# 
# ******************************************************************************
# *                                                                            *
# *                   Copyright (C) 2004-2010, Nangate Inc.                    *
# *                           All rights reserved.                             *
# *                                                                            *
# * Nangate and the Nangate logo are trademarks of Nangate Inc.                *
# *                                                                            *
# * All trademarks, logos, software marks, and trade names (collectively the   *
# * "Marks") in this program are proprietary to Nangate or other respective    *
# * owners that have granted Nangate the right and license to use such Marks.  *
# * You are not permitted to use the Marks without the prior written consent   *
# * of Nangate or such third party that may own the Marks.                     *
# *                                                                            *
# * This file has been provided pursuant to a License Agreement containing     *
# * restrictions on its use. This file contains valuable trade secrets and     *
# * proprietary information of Nangate Inc., and is protected by U.S. and      *
# * international laws and/or treaties.                                        *
# *                                                                            *
# * The copyright notice(s) in this file does not indicate actual or intended  *
# * publication of this file.                                                  *
# *                                                                            *
# *     NGLibraryCreator, v2010.08-HR32-SP3-2010-08-05 - build 1009061800      *
# *                                                                            *
# ******************************************************************************
# 
# 
# Running on brazil06.nangate.com.br for user Giancarlo Franciscatto (gfr).
# Local time is now Fri, 3 Dec 2010, 19:32:18.
# Main process id is 27821.

VERSION 5.6 ;
BUSBITCHARS "[]" ;
DIVIDERCHAR "/" ;

UNITS
  DATABASE MICRONS 2000 ;
END UNITS

MANUFACTURINGGRID 0.0050 ;

LAYER poly
  TYPE MASTERSLICE ;
END poly

LAYER active
  TYPE MASTERSLICE ;
END active

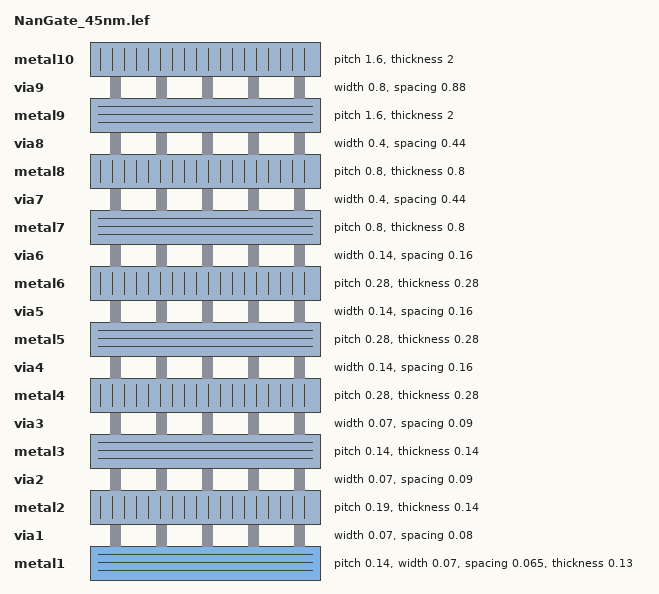
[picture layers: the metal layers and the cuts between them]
LAYER metal1
  TYPE ROUTING ;
  SPACING 0.065 ;
  WIDTH 0.07 ;
  PITCH 0.14 ;
  DIRECTION HORIZONTAL ;
  OFFSET 0.095 0.07 ;
  RESISTANCE RPERSQ 0.38 ;
  THICKNESS 0.13 ;
  HEIGHT 0.37 ;
  CAPACITANCE CPERSQDIST 7.7161e-05 ;
  EDGECAPACITANCE 2.7365e-05 ;
END metal1

LAYER via1
  TYPE CUT ;
  SPACING 0.08 ;
  WIDTH 0.07 ;
  RESISTANCE 5 ;
END via1

LAYER metal2
  TYPE ROUTING ;
  SPACINGTABLE 
    PARALLELRUNLENGTH    0.0000     0.3000     0.9000     1.8000     2.7000     4.0000     
      WIDTH 0.0000       0.0700     0.0700     0.0700     0.0700     0.0700     0.0700     
      WIDTH 0.0900       0.0700     0.0900     0.0900     0.0900     0.0900     0.0900     
      WIDTH 0.2700       0.0700     0.0900     0.2700     0.2700     0.2700     0.2700     
      WIDTH 0.5000       0.0700     0.0900     0.2700     0.5000     0.5000     0.5000     
      WIDTH 0.9000       0.0700     0.0900     0.2700     0.5000     0.9000     0.9000     
      WIDTH 1.5000       0.0700     0.0900     0.2700     0.5000     0.9000     1.5000      ;
  WIDTH 0.07 ;
  PITCH 0.19 ;
  DIRECTION VERTICAL ;
  OFFSET 0.095 0.07 ;
  RESISTANCE RPERSQ 0.25 ;
  THICKNESS 0.14 ;
  HEIGHT 0.62 ;
  CAPACITANCE CPERSQDIST 4.0896e-05 ;
  EDGECAPACITANCE 2.5157e-05 ;
END metal2

LAYER via2
  TYPE CUT ;
  SPACING 0.09 ;
  WIDTH 0.07 ;
  RESISTANCE 5 ;
END via2

LAYER metal3
  TYPE ROUTING ;
  SPACINGTABLE 
    PARALLELRUNLENGTH    0.0000     0.3000     0.9000     1.8000     2.7000     4.0000     
      WIDTH 0.0000       0.0700     0.0700     0.0700     0.0700     0.0700     0.0700     
      WIDTH 0.0900       0.0700     0.0900     0.0900     0.0900     0.0900     0.0900     
      WIDTH 0.2700       0.0700     0.0900     0.2700     0.2700     0.2700     0.2700     
      WIDTH 0.5000       0.0700     0.0900     0.2700     0.5000     0.5000     0.5000     
      WIDTH 0.9000       0.0700     0.0900     0.2700     0.5000     0.9000     0.9000     
      WIDTH 1.5000       0.0700     0.0900     0.2700     0.5000     0.9000     1.5000      ;
  WIDTH 0.07 ;
  PITCH 0.14 ;
  DIRECTION HORIZONTAL ;
  OFFSET 0.095 0.07 ;
  RESISTANCE RPERSQ 0.25 ;
  THICKNESS 0.14 ;
  HEIGHT 0.88 ;
  CAPACITANCE CPERSQDIST 2.7745e-05 ;
  EDGECAPACITANCE 2.5157e-05 ;
END metal3

LAYER via3
  TYPE CUT ;
  SPACING 0.09 ;
  WIDTH 0.07 ;
  RESISTANCE 5 ;
END via3

LAYER metal4
  TYPE ROUTING ;
  SPACINGTABLE 
    PARALLELRUNLENGTH    0.0000     0.9000     1.8000     2.7000     4.0000     
      WIDTH 0.0000       0.1400     0.1400     0.1400     0.1400     0.1400     
      WIDTH 0.2700       0.1400     0.2700     0.2700     0.2700     0.2700     
      WIDTH 0.5000       0.1400     0.2700     0.5000     0.5000     0.5000     
      WIDTH 0.9000       0.1400     0.2700     0.5000     0.9000     0.9000     
      WIDTH 1.5000       0.1400     0.2700     0.5000     0.9000     1.5000      ;
  WIDTH 0.14 ;
  PITCH 0.28 ;
  DIRECTION VERTICAL ;
  OFFSET 0.095 0.07 ;
  RESISTANCE RPERSQ 0.21 ;
  THICKNESS 0.28 ;
  HEIGHT 1.14 ;
  CAPACITANCE CPERSQDIST 2.0743e-05 ;
  EDGECAPACITANCE 3.0908e-05 ;
END metal4

LAYER via4
  TYPE CUT ;
  SPACING 0.16 ;
  WIDTH 0.14 ;
  RESISTANCE 3 ;
END via4

LAYER metal5
  TYPE ROUTING ;
  SPACINGTABLE 
    PARALLELRUNLENGTH    0.0000     0.9000     1.8000     2.7000     4.0000     
      WIDTH 0.0000       0.1400     0.1400     0.1400     0.1400     0.1400     
      WIDTH 0.2700       0.1400     0.2700     0.2700     0.2700     0.2700     
      WIDTH 0.5000       0.1400     0.2700     0.5000     0.5000     0.5000     
      WIDTH 0.9000       0.1400     0.2700     0.5000     0.9000     0.9000     
      WIDTH 1.5000       0.1400     0.2700     0.5000     0.9000     1.5000      ;
  WIDTH 0.14 ;
  PITCH 0.28 ;
  DIRECTION HORIZONTAL ;
  OFFSET 0.095 0.07 ;
  RESISTANCE RPERSQ 0.21 ;
  THICKNESS 0.28 ;
  HEIGHT 1.71 ;
  CAPACITANCE CPERSQDIST 1.3527e-05 ;
  EDGECAPACITANCE 2.3863e-06 ;
END metal5

LAYER via5
  TYPE CUT ;
  SPACING 0.16 ;
  WIDTH 0.14 ;
  RESISTANCE 3 ;
END via5

LAYER metal6
  TYPE ROUTING ;
  SPACINGTABLE 
    PARALLELRUNLENGTH    0.0000     0.9000     1.8000     2.7000     4.0000     
      WIDTH 0.0000       0.1400     0.1400     0.1400     0.1400     0.1400     
      WIDTH 0.2700       0.1400     0.2700     0.2700     0.2700     0.2700     
      WIDTH 0.5000       0.1400     0.2700     0.5000     0.5000     0.5000     
      WIDTH 0.9000       0.1400     0.2700     0.5000     0.9000     0.9000     
      WIDTH 1.5000       0.1400     0.2700     0.5000     0.9000     1.5000      ;
  WIDTH 0.14 ;
  PITCH 0.28 ;
  DIRECTION VERTICAL ;
  OFFSET 0.095 0.07 ;
  RESISTANCE RPERSQ 0.21 ;
  THICKNESS 0.28 ;
  HEIGHT 2.28 ;
  CAPACITANCE CPERSQDIST 1.0036e-05 ;
  EDGECAPACITANCE 2.3863e-05 ;
END metal6

LAYER via6
  TYPE CUT ;
  SPACING 0.16 ;
  WIDTH 0.14 ;
  RESISTANCE 3 ;
END via6

LAYER metal7
  TYPE ROUTING ;
  SPACINGTABLE 
    PARALLELRUNLENGTH    0.0000     1.8000     2.7000     4.0000     
      WIDTH 0.0000       0.4000     0.4000     0.4000     0.4000     
      WIDTH 0.5000       0.4000     0.5000     0.5000     0.5000     
      WIDTH 0.9000       0.4000     0.5000     0.9000     0.9000     
      WIDTH 1.5000       0.4000     0.5000     0.9000     1.5000      ;
  WIDTH 0.4 ;
  PITCH 0.8 ;
  DIRECTION HORIZONTAL ;
  OFFSET 0.095 0.07 ;
  RESISTANCE RPERSQ 0.075 ;
  THICKNESS 0.8 ;
  HEIGHT 2.85 ;
  CAPACITANCE CPERSQDIST 7.9771e-06 ;
  EDGECAPACITANCE 3.2577e-05 ;
END metal7

LAYER via7
  TYPE CUT ;
  SPACING 0.44 ;
  WIDTH 0.4 ;
  RESISTANCE 1 ;
END via7

LAYER metal8
  TYPE ROUTING ;
  SPACINGTABLE 
    PARALLELRUNLENGTH    0.0000     1.8000     2.7000     4.0000     
      WIDTH 0.0000       0.4000     0.4000     0.4000     0.4000     
      WIDTH 0.5000       0.4000     0.5000     0.5000     0.5000     
      WIDTH 0.9000       0.4000     0.5000     0.9000     0.9000     
      WIDTH 1.5000       0.4000     0.5000     0.9000     1.5000      ;
  WIDTH 0.4 ;
  PITCH 0.8 ;
  DIRECTION VERTICAL ;
  OFFSET 0.095 0.07 ;
  RESISTANCE RPERSQ 0.075 ;
  THICKNESS 0.8 ;
  HEIGHT 4.47 ;
  CAPACITANCE CPERSQDIST 5.0391e-06 ;
  EDGECAPACITANCE 2.3932e-05 ;
END metal8

LAYER via8
  TYPE CUT ;
  SPACING 0.44 ;
  WIDTH 0.4 ;
  RESISTANCE 1 ;
END via8

LAYER metal9
  TYPE ROUTING ;
  SPACINGTABLE 
    PARALLELRUNLENGTH    0.0000     2.7000     4.0000     
      WIDTH 0.0000       0.8000     0.8000     0.8000     
      WIDTH 0.9000       0.8000     0.9000     0.9000     
      WIDTH 1.5000       0.8000     0.9000     1.5000      ;
  WIDTH 0.8 ;
  PITCH 1.6 ;
  DIRECTION HORIZONTAL ;
  OFFSET 0.095 0.07 ;
  RESISTANCE RPERSQ 0.03 ;
  THICKNESS 2 ;
  HEIGHT 6.09 ;
  CAPACITANCE CPERSQDIST 3.6827e-06 ;
  EDGECAPACITANCE 3.0803e-05 ;
END metal9

LAYER via9
  TYPE CUT ;
  SPACING 0.88 ;
  WIDTH 0.8 ;
  RESISTANCE 0.5 ;
END via9

LAYER metal10
  TYPE ROUTING ;
  SPACINGTABLE 
    PARALLELRUNLENGTH    0.0000     2.7000     4.0000     
      WIDTH 0.0000       0.8000     0.8000     0.8000     
      WIDTH 0.9000       0.8000     0.9000     0.9000     
      WIDTH 1.5000       0.8000     0.9000     1.5000      ;
  WIDTH 0.8 ;
  PITCH 1.6 ;
  DIRECTION VERTICAL ;
  OFFSET 0.095 0.07 ;
  RESISTANCE RPERSQ 0.03 ;
  THICKNESS 2 ;
  HEIGHT 10.09 ;
  CAPACITANCE CPERSQDIST 2.2124e-06 ;
  EDGECAPACITANCE 2.3667e-05 ;
END metal10

LAYER OVERLAP
  TYPE OVERLAP ;
END OVERLAP

VIA via1_4 DEFAULT
  LAYER via1 ;
    RECT -0.035 -0.035 0.035 0.035 ;
  LAYER metal1 ;
    RECT -0.035 -0.07 0.035 0.07 ;
  LAYER metal2 ;
    RECT -0.035 -0.07 0.035 0.07 ;
END via1_4

VIA via1_0 DEFAULT
  LAYER via1 ;
    RECT -0.035 -0.035 0.035 0.035 ;
  LAYER metal1 ;
    RECT -0.07 -0.07 0.07 0.07 ;
  LAYER metal2 ;
    RECT -0.07 -0.07 0.07 0.07 ;
END via1_0

VIA via1_1 DEFAULT
  LAYER via1 ;
    RECT -0.035 -0.035 0.035 0.035 ;
  LAYER metal1 ;
    RECT -0.07 -0.07 0.07 0.07 ;
  LAYER metal2 ;
    RECT -0.035 -0.07 0.035 0.07 ;
END via1_1

VIA via1_2 DEFAULT
  LAYER via1 ;
    RECT -0.035 -0.035 0.035 0.035 ;
  LAYER metal1 ;
    RECT -0.07 -0.07 0.07 0.07 ;
  LAYER metal2 ;
    RECT -0.07 -0.035 0.07 0.035 ;
END via1_2

VIA via1_3 DEFAULT
  LAYER via1 ;
    RECT -0.035 -0.035 0.035 0.035 ;
  LAYER metal1 ;
    RECT -0.035 -0.07 0.035 0.07 ;
  LAYER metal2 ;
    RECT -0.07 -0.07 0.07 0.07 ;
END via1_3

VIA via1_5 DEFAULT
  LAYER via1 ;
    RECT -0.035 -0.035 0.035 0.035 ;
  LAYER metal1 ;
    RECT -0.035 -0.07 0.035 0.07 ;
  LAYER metal2 ;
    RECT -0.07 -0.035 0.07 0.035 ;
END via1_5

VIA via1_6 DEFAULT
  LAYER via1 ;
    RECT -0.035 -0.035 0.035 0.035 ;
  LAYER metal1 ;
    RECT -0.07 -0.035 0.07 0.035 ;
  LAYER metal2 ;
    RECT -0.07 -0.07 0.07 0.07 ;
END via1_6

VIA via1_7 DEFAULT
  LAYER via1 ;
    RECT -0.035 -0.035 0.035 0.035 ;
  LAYER metal1 ;
    RECT -0.07 -0.035 0.07 0.035 ;
  LAYER metal2 ;
    RECT -0.035 -0.07 0.035 0.07 ;
END via1_7

VIA via1_8 DEFAULT
  LAYER via1 ;
    RECT -0.035 -0.035 0.035 0.035 ;
  LAYER metal1 ;
    RECT -0.07 -0.035 0.07 0.035 ;
  LAYER metal2 ;
    RECT -0.07 -0.035 0.07 0.035 ;
END via1_8

VIA via2_8 DEFAULT
  LAYER via2 ;
    RECT -0.035 -0.035 0.035 0.035 ;
  LAYER metal2 ;
    RECT -0.07 -0.035 0.07 0.035 ;
  LAYER metal3 ;
    RECT -0.07 -0.035 0.07 0.035 ;
END via2_8

VIA via2_4 DEFAULT
  LAYER via2 ;
    RECT -0.035 -0.035 0.035 0.035 ;
  LAYER metal2 ;
    RECT -0.035 -0.07 0.035 0.07 ;
  LAYER metal3 ;
    RECT -0.035 -0.07 0.035 0.07 ;
END via2_4

VIA via2_5 DEFAULT
  LAYER via2 ;
    RECT -0.035 -0.035 0.035 0.035 ;
  LAYER metal2 ;
    RECT -0.035 -0.07 0.035 0.07 ;
  LAYER metal3 ;
    RECT -0.07 -0.035 0.07 0.035 ;
END via2_5

VIA via2_7 DEFAULT
  LAYER via2 ;
    RECT -0.035 -0.035 0.035 0.035 ;
  LAYER metal2 ;
    RECT -0.07 -0.035 0.07 0.035 ;
  LAYER metal3 ;
    RECT -0.035 -0.07 0.035 0.07 ;
END via2_7

VIA via2_6 DEFAULT
  LAYER via2 ;
    RECT -0.035 -0.035 0.035 0.035 ;
  LAYER metal2 ;
    RECT -0.07 -0.035 0.07 0.035 ;
  LAYER metal3 ;
    RECT -0.07 -0.07 0.07 0.07 ;
END via2_6

VIA via2_0 DEFAULT
  LAYER via2 ;
    RECT -0.035 -0.035 0.035 0.035 ;
  LAYER metal2 ;
    RECT -0.07 -0.07 0.07 0.07 ;
  LAYER metal3 ;
    RECT -0.07 -0.07 0.07 0.07 ;
END via2_0

VIA via2_1 DEFAULT
  LAYER via2 ;
    RECT -0.035 -0.035 0.035 0.035 ;
  LAYER metal2 ;
    RECT -0.07 -0.07 0.07 0.07 ;
  LAYER metal3 ;
    RECT -0.035 -0.07 0.035 0.07 ;
END via2_1

VIA via2_2 DEFAULT
  LAYER via2 ;
    RECT -0.035 -0.035 0.035 0.035 ;
  LAYER metal2 ;
    RECT -0.07 -0.07 0.07 0.07 ;
  LAYER metal3 ;
    RECT -0.07 -0.035 0.07 0.035 ;
END via2_2

VIA via2_3 DEFAULT
  LAYER via2 ;
    RECT -0.035 -0.035 0.035 0.035 ;
  LAYER metal2 ;
    RECT -0.035 -0.07 0.035 0.07 ;
  LAYER metal3 ;
    RECT -0.07 -0.07 0.07 0.07 ;
END via2_3

VIA via3_2 DEFAULT
  LAYER via3 ;
    RECT -0.035 -0.035 0.035 0.035 ;
  LAYER metal3 ;
    RECT -0.07 -0.035 0.07 0.035 ;
  LAYER metal4 ;
    RECT -0.07 -0.07 0.07 0.07 ;
END via3_2

VIA via3_0 DEFAULT
  LAYER via3 ;
    RECT -0.035 -0.035 0.035 0.035 ;
  LAYER metal3 ;
    RECT -0.07 -0.07 0.07 0.07 ;
  LAYER metal4 ;
    RECT -0.07 -0.07 0.07 0.07 ;
END via3_0

VIA via3_1 DEFAULT
  LAYER via3 ;
    RECT -0.035 -0.035 0.035 0.035 ;
  LAYER metal3 ;
    RECT -0.035 -0.07 0.035 0.07 ;
  LAYER metal4 ;
    RECT -0.07 -0.07 0.07 0.07 ;
END via3_1

VIA via4_0 DEFAULT
  LAYER via4 ;
    RECT -0.07 -0.07 0.07 0.07 ;
  LAYER metal4 ;
    RECT -0.07 -0.07 0.07 0.07 ;
  LAYER metal5 ;
    RECT -0.07 -0.07 0.07 0.07 ;
END via4_0

VIA via5_0 DEFAULT
  LAYER via5 ;
    RECT -0.07 -0.07 0.07 0.07 ;
  LAYER metal5 ;
    RECT -0.07 -0.07 0.07 0.07 ;
  LAYER metal6 ;
    RECT -0.07 -0.07 0.07 0.07 ;
END via5_0

VIA via6_0 DEFAULT
  LAYER via6 ;
    RECT -0.07 -0.07 0.07 0.07 ;
  LAYER metal6 ;
    RECT -0.07 -0.07 0.07 0.07 ;
  LAYER metal7 ;
    RECT -0.2 -0.2 0.2 0.2 ;
END via6_0

VIA via7_0 DEFAULT
  LAYER via7 ;
    RECT -0.2 -0.2 0.2 0.2 ;
  LAYER metal7 ;
    RECT -0.2 -0.2 0.2 0.2 ;
  LAYER metal8 ;
    RECT -0.2 -0.2 0.2 0.2 ;
END via7_0

VIA via8_0 DEFAULT
  LAYER via8 ;
    RECT -0.2 -0.2 0.2 0.2 ;
  LAYER metal8 ;
    RECT -0.2 -0.2 0.2 0.2 ;
  LAYER metal9 ;
    RECT -0.4 -0.4 0.4 0.4 ;
END via8_0

VIA via9_0 DEFAULT
  LAYER via9 ;
    RECT -0.4 -0.4 0.4 0.4 ;
  LAYER metal9 ;
    RECT -0.4 -0.4 0.4 0.4 ;
  LAYER metal10 ;
    RECT -0.4 -0.4 0.4 0.4 ;
END via9_0

VIARULE Via1Array-0 GENERATE
  LAYER metal1 ;
    ENCLOSURE 0.035 0.035 ;
  LAYER metal2 ;
    ENCLOSURE 0.035 0.035 ;
  LAYER via1 ;
    RECT -0.035 -0.035 0.035 0.035 ;
    SPACING 0.15 BY 0.15 ;
END Via1Array-0

VIARULE Via1Array-1 GENERATE
  LAYER metal1 ;
    ENCLOSURE 0 0.035 ;
  LAYER metal2 ;
    ENCLOSURE 0 0.035 ;
  LAYER via1 ;
    RECT -0.035 -0.035 0.035 0.035 ;
    SPACING 0.15 BY 0.15 ;
END Via1Array-1

VIARULE Via1Array-2 GENERATE
  LAYER metal1 ;
    ENCLOSURE 0.035 0 ;
  LAYER metal2 ;
    ENCLOSURE 0.035 0 ;
  LAYER via1 ;
    RECT -0.035 -0.035 0.035 0.035 ;
    SPACING 0.15 BY 0.15 ;
END Via1Array-2

VIARULE Via1Array-3 GENERATE
  LAYER metal1 ;
    ENCLOSURE 0 0.035 ;
  LAYER metal2 ;
    ENCLOSURE 0.035 0 ;
  LAYER via1 ;
    RECT -0.035 -0.035 0.035 0.035 ;
    SPACING 0.15 BY 0.15 ;
END Via1Array-3

VIARULE Via1Array-4 GENERATE
  LAYER metal1 ;
    ENCLOSURE 0.035 0 ;
  LAYER metal2 ;
    ENCLOSURE 0 0.035 ;
  LAYER via1 ;
    RECT -0.035 -0.035 0.035 0.035 ;
    SPACING 0.15 BY 0.15 ;
END Via1Array-4

VIARULE Via2Array-0 GENERATE
  LAYER metal2 ;
    ENCLOSURE 0.035 0.035 ;
  LAYER metal3 ;
    ENCLOSURE 0.035 0.035 ;
  LAYER via2 ;
    RECT -0.035 -0.035 0.035 0.035 ;
    SPACING 0.16 BY 0.16 ;
END Via2Array-0

VIARULE Via2Array-1 GENERATE
  LAYER metal2 ;
    ENCLOSURE 0 0.035 ;
  LAYER metal3 ;
    ENCLOSURE 0 0.035 ;
  LAYER via2 ;
    RECT -0.035 -0.035 0.035 0.035 ;
    SPACING 0.16 BY 0.16 ;
END Via2Array-1

VIARULE Via2Array-2 GENERATE
  LAYER metal2 ;
    ENCLOSURE 0.035 0 ;
  LAYER metal3 ;
    ENCLOSURE 0.035 0 ;
  LAYER via2 ;
    RECT -0.035 -0.035 0.035 0.035 ;
    SPACING 0.16 BY 0.16 ;
END Via2Array-2

VIARULE Via2Array-3 GENERATE
  LAYER metal2 ;
    ENCLOSURE 0 0.035 ;
  LAYER metal3 ;
    ENCLOSURE 0.035 0 ;
  LAYER via2 ;
    RECT -0.035 -0.035 0.035 0.035 ;
    SPACING 0.16 BY 0.16 ;
END Via2Array-3

VIARULE Via2Array-4 GENERATE
  LAYER metal2 ;
    ENCLOSURE 0.035 0 ;
  LAYER metal3 ;
    ENCLOSURE 0 0.035 ;
  LAYER via2 ;
    RECT -0.035 -0.035 0.035 0.035 ;
    SPACING 0.16 BY 0.16 ;
END Via2Array-4

VIARULE Via3Array-0 GENERATE
  LAYER metal3 ;
    ENCLOSURE 0.035 0.035 ;
  LAYER metal4 ;
    ENCLOSURE 0.035 0.035 ;
  LAYER via3 ;
    RECT -0.035 -0.035 0.035 0.035 ;
    SPACING 0.16 BY 0.16 ;
END Via3Array-0

VIARULE Via3Array-1 GENERATE
  LAYER metal3 ;
    ENCLOSURE 0 0.035 ;
  LAYER metal4 ;
    ENCLOSURE 0.035 0.035 ;
  LAYER via3 ;
    RECT -0.035 -0.035 0.035 0.035 ;
    SPACING 0.16 BY 0.16 ;
END Via3Array-1

VIARULE Via3Array-2 GENERATE
  LAYER metal3 ;
    ENCLOSURE 0.035 0 ;
  LAYER metal4 ;
    ENCLOSURE 0.035 0.035 ;
  LAYER via3 ;
    RECT -0.035 -0.035 0.035 0.035 ;
    SPACING 0.16 BY 0.16 ;
END Via3Array-2

VIARULE Via4Array-0 GENERATE
  LAYER metal4 ;
    ENCLOSURE 0 0 ;
  LAYER metal5 ;
    ENCLOSURE 0 0 ;
  LAYER via4 ;
    RECT -0.07 -0.07 0.07 0.07 ;
    SPACING 0.3 BY 0.3 ;
END Via4Array-0

VIARULE Via5Array-0 GENERATE
  LAYER metal5 ;
    ENCLOSURE 0 0 ;
  LAYER metal6 ;
    ENCLOSURE 0 0 ;
  LAYER via5 ;
    RECT -0.07 -0.07 0.07 0.07 ;
    SPACING 0.3 BY 0.3 ;
END Via5Array-0

VIARULE Via6Array-0 GENERATE
  LAYER metal6 ;
    ENCLOSURE 0 0 ;
  LAYER metal7 ;
    ENCLOSURE 0.13 0.13 ;
  LAYER via6 ;
    RECT -0.07 -0.07 0.07 0.07 ;
    SPACING 0.3 BY 0.3 ;
END Via6Array-0

VIARULE Via7Array-0 GENERATE
  LAYER metal7 ;
    ENCLOSURE 0 0 ;
  LAYER metal8 ;
    ENCLOSURE 0 0 ;
  LAYER via7 ;
    RECT -0.2 -0.2 0.2 0.2 ;
    SPACING 0.84 BY 0.84 ;
END Via7Array-0

VIARULE Via8Array-0 GENERATE
  LAYER metal8 ;
    ENCLOSURE 0 0 ;
  LAYER metal9 ;
    ENCLOSURE 0.2 0.2 ;
  LAYER via8 ;
    RECT -0.2 -0.2 0.2 0.2 ;
    SPACING 0.84 BY 0.84 ;
END Via8Array-0

VIARULE Via9Array-0 GENERATE
  LAYER metal10 ;
    ENCLOSURE 0 0 ;
  LAYER metal9 ;
    ENCLOSURE 0 0 ;
  LAYER via9 ;
    RECT -0.4 -0.4 0.4 0.4 ;
    SPACING 1.68 BY 1.68 ;
END Via9Array-0

SPACING
  SAMENET metal1 metal1 0.065 ;
  SAMENET metal2 metal2 0.07 ;
  SAMENET metal3 metal3 0.07 ;
  SAMENET metal4 metal4 0.14 ;
  SAMENET metal5 metal5 0.14 ;
  SAMENET metal6 metal6 0.14 ;
  SAMENET metal7 metal7 0.4 ;
  SAMENET metal8 metal8 0.4 ;
  SAMENET metal9 metal9 0.8 ;
  SAMENET metal10 metal10 0.8 ;
  SAMENET via1 via1 0.08 ;
  SAMENET via2 via2 0.09 ;
  SAMENET via3 via3 0.09 ;
  SAMENET via4 via4 0.16 ;
  SAMENET via5 via5 0.16 ;
  SAMENET via6 via6 0.16 ;
  SAMENET via7 via7 0.44 ;
  SAMENET via8 via8 0.44 ;
  SAMENET via9 via9 0.88 ;
  SAMENET via1 via2 0.0 STACK ;
  SAMENET via2 via3 0.0 STACK ;
  SAMENET via3 via4 0.0 STACK ;
  SAMENET via4 via5 0.0 STACK ;
  SAMENET via5 via6 0.0 STACK ;
  SAMENET via6 via7 0.0 STACK ;
  SAMENET via7 via8 0.0 STACK ;
  SAMENET via8 via9 0.0 STACK ;
END SPACING

SITE FreePDK45_38x28_10R_NP_162NW_34O
  SYMMETRY y ;
  CLASS core ;
  SIZE 0.19 BY 1.4 ;
END FreePDK45_38x28_10R_NP_162NW_34O


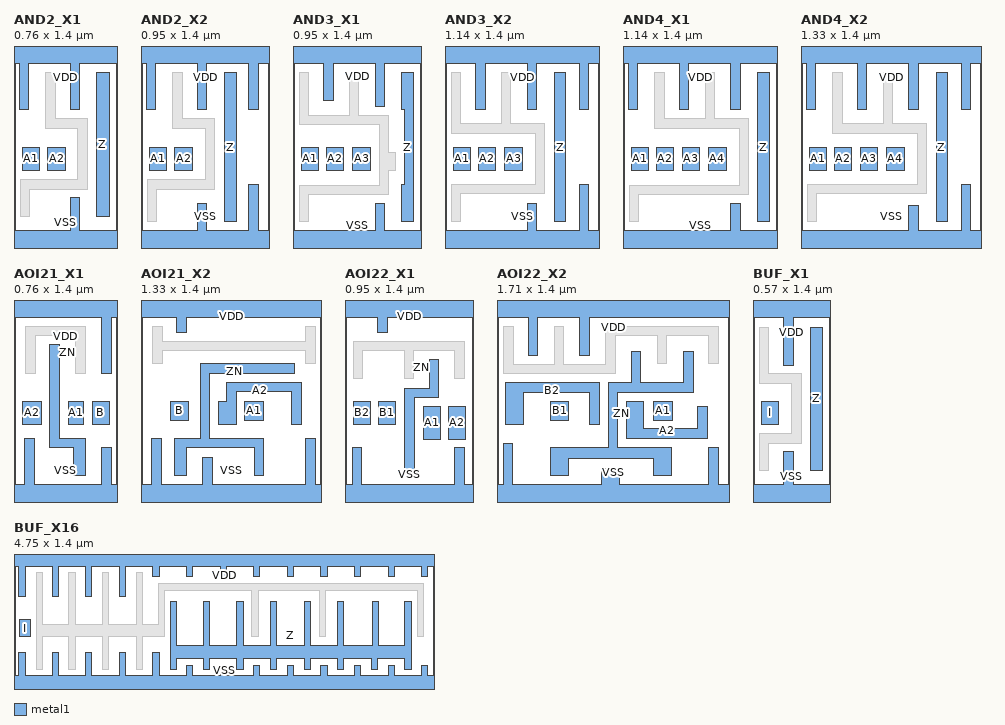
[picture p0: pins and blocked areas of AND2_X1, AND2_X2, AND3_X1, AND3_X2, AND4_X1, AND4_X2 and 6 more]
MACRO AND2_X1
  CLASS core ;
  FOREIGN AND2_X1 0.0 0.0 ;
  ORIGIN 0 0 ;
  SYMMETRY X Y ;
  SITE FreePDK45_38x28_10R_NP_162NW_34O ;
  SIZE 0.76 BY 1.4 ;
  PIN A1
    DIRECTION INPUT ;
    ANTENNAPARTIALMETALAREA 0.021875 LAYER metal1 ;
    ANTENNAPARTIALMETALSIDEAREA 0.078 LAYER metal1 ;
    ANTENNAGATEAREA 0.02625 ;
    PORT
      LAYER metal1 ;
        POLYGON 0.06 0.525 0.185 0.525 0.185 0.7 0.06 0.7  ;
    END
  END A1
  PIN A2
    DIRECTION INPUT ;
    ANTENNAPARTIALMETALAREA 0.02275 LAYER metal1 ;
    ANTENNAPARTIALMETALSIDEAREA 0.0793 LAYER metal1 ;
    ANTENNAGATEAREA 0.02625 ;
    PORT
      LAYER metal1 ;
        POLYGON 0.25 0.525 0.38 0.525 0.38 0.7 0.25 0.7  ;
    END
  END A2
  PIN Z
    DIRECTION OUTPUT ;
    ANTENNAPARTIALMETALAREA 0.0954 LAYER metal1 ;
    ANTENNAPARTIALMETALSIDEAREA 0.299 LAYER metal1 ;
    ANTENNADIFFAREA 0.109725 ;
    PORT
      LAYER metal1 ;
        POLYGON 0.61 0.19 0.7 0.19 0.7 1.25 0.61 1.25  ;
    END
  END Z
  PIN VDD
    DIRECTION INOUT ;
    USE power ;
    SHAPE ABUTMENT ;
    PORT
      LAYER metal1 ;
        POLYGON 0 1.315 0.04 1.315 0.04 0.975 0.11 0.975 0.11 1.315 0.415 1.315 0.415 0.975 0.485 0.975 0.485 1.315 0.54 1.315 0.76 1.315 0.76 1.485 0.54 1.485 0 1.485  ;
    END
  END VDD
  PIN VSS
    DIRECTION INOUT ;
    USE ground ;
    SHAPE ABUTMENT ;
    PORT
      LAYER metal1 ;
        POLYGON 0 -0.085 0.76 -0.085 0.76 0.085 0.485 0.085 0.485 0.325 0.415 0.325 0.415 0.085 0 0.085  ;
    END
  END VSS
  OBS
      LAYER metal1 ;
        POLYGON 0.235 0.84 0.47 0.84 0.47 0.46 0.045 0.46 0.045 0.19 0.115 0.19 0.115 0.39 0.54 0.39 0.54 0.91 0.305 0.91 0.305 1.25 0.235 1.25  ;
  END
END AND2_X1

MACRO AND2_X2
  CLASS core ;
  FOREIGN AND2_X2 0.0 0.0 ;
  ORIGIN 0 0 ;
  SYMMETRY X Y ;
  SITE FreePDK45_38x28_10R_NP_162NW_34O ;
  SIZE 0.95 BY 1.4 ;
  PIN A1
    DIRECTION INPUT ;
    ANTENNAPARTIALMETALAREA 0.021875 LAYER metal1 ;
    ANTENNAPARTIALMETALSIDEAREA 0.078 LAYER metal1 ;
    ANTENNAGATEAREA 0.05225 ;
    PORT
      LAYER metal1 ;
        POLYGON 0.06 0.525 0.185 0.525 0.185 0.7 0.06 0.7  ;
    END
  END A1
  PIN A2
    DIRECTION INPUT ;
    ANTENNAPARTIALMETALAREA 0.02275 LAYER metal1 ;
    ANTENNAPARTIALMETALSIDEAREA 0.0793 LAYER metal1 ;
    ANTENNAGATEAREA 0.05225 ;
    PORT
      LAYER metal1 ;
        POLYGON 0.25 0.525 0.38 0.525 0.38 0.7 0.25 0.7  ;
    END
  END A2
  PIN Z
    DIRECTION OUTPUT ;
    ANTENNAPARTIALMETALAREA 0.0935 LAYER metal1 ;
    ANTENNAPARTIALMETALSIDEAREA 0.3081 LAYER metal1 ;
    ANTENNADIFFAREA 0.1463 ;
    PORT
      LAYER metal1 ;
        POLYGON 0.615 0.15 0.7 0.15 0.7 1.25 0.615 1.25  ;
    END
  END Z
  PIN VDD
    DIRECTION INOUT ;
    USE power ;
    SHAPE ABUTMENT ;
    PORT
      LAYER metal1 ;
        POLYGON 0 1.315 0.04 1.315 0.04 0.975 0.11 0.975 0.11 1.315 0.415 1.315 0.415 0.975 0.485 0.975 0.485 1.315 0.545 1.315 0.795 1.315 0.795 0.975 0.865 0.975 0.865 1.315 0.95 1.315 0.95 1.485 0.545 1.485 0 1.485  ;
    END
  END VDD
  PIN VSS
    DIRECTION INOUT ;
    USE ground ;
    SHAPE ABUTMENT ;
    PORT
      LAYER metal1 ;
        POLYGON 0 -0.085 0.95 -0.085 0.95 0.085 0.865 0.085 0.865 0.425 0.795 0.425 0.795 0.085 0.485 0.085 0.485 0.285 0.415 0.285 0.415 0.085 0 0.085  ;
    END
  END VSS
  OBS
      LAYER metal1 ;
        POLYGON 0.235 0.84 0.475 0.84 0.475 0.46 0.045 0.46 0.045 0.15 0.115 0.15 0.115 0.39 0.545 0.39 0.545 0.91 0.305 0.91 0.305 1.25 0.235 1.25  ;
  END
END AND2_X2

MACRO AND3_X1
  CLASS core ;
  FOREIGN AND3_X1 0.0 0.0 ;
  ORIGIN 0 0 ;
  SYMMETRY X Y ;
  SITE FreePDK45_38x28_10R_NP_162NW_34O ;
  SIZE 0.95 BY 1.4 ;
  PIN A1
    DIRECTION INPUT ;
    ANTENNAPARTIALMETALAREA 0.021875 LAYER metal1 ;
    ANTENNAPARTIALMETALSIDEAREA 0.078 LAYER metal1 ;
    ANTENNAGATEAREA 0.02625 ;
    PORT
      LAYER metal1 ;
        POLYGON 0.06 0.525 0.185 0.525 0.185 0.7 0.06 0.7  ;
    END
  END A1
  PIN A2
    DIRECTION INPUT ;
    ANTENNAPARTIALMETALAREA 0.021875 LAYER metal1 ;
    ANTENNAPARTIALMETALSIDEAREA 0.078 LAYER metal1 ;
    ANTENNAGATEAREA 0.02625 ;
    PORT
      LAYER metal1 ;
        POLYGON 0.25 0.525 0.375 0.525 0.375 0.7 0.25 0.7  ;
    END
  END A2
  PIN A3
    DIRECTION INPUT ;
    ANTENNAPARTIALMETALAREA 0.02275 LAYER metal1 ;
    ANTENNAPARTIALMETALSIDEAREA 0.0793 LAYER metal1 ;
    ANTENNAGATEAREA 0.02625 ;
    PORT
      LAYER metal1 ;
        POLYGON 0.44 0.525 0.57 0.525 0.57 0.7 0.44 0.7  ;
    END
  END A3
  PIN Z
    DIRECTION OUTPUT ;
    ANTENNAPARTIALMETALAREA 0.088 LAYER metal1 ;
    ANTENNAPARTIALMETALSIDEAREA 0.3146 LAYER metal1 ;
    ANTENNADIFFAREA 0.109725 ;
    PORT
      LAYER metal1 ;
        POLYGON 0.8 0.975 0.82 0.975 0.82 0.425 0.8 0.425 0.8 0.15 0.89 0.15 0.89 1.25 0.8 1.25  ;
    END
  END Z
  PIN VDD
    DIRECTION INOUT ;
    USE power ;
    SHAPE ABUTMENT ;
    PORT
      LAYER metal1 ;
        POLYGON 0 1.315 0.225 1.315 0.225 1.04 0.295 1.04 0.295 1.315 0.605 1.315 0.605 1 0.675 1 0.675 1.315 0.755 1.315 0.95 1.315 0.95 1.485 0.755 1.485 0 1.485  ;
    END
  END VDD
  PIN VSS
    DIRECTION INOUT ;
    USE ground ;
    SHAPE ABUTMENT ;
    PORT
      LAYER metal1 ;
        POLYGON 0 -0.085 0.95 -0.085 0.95 0.085 0.675 0.085 0.675 0.285 0.605 0.285 0.605 0.085 0 0.085  ;
    END
  END VSS
  OBS
      LAYER metal1 ;
        POLYGON 0.045 0.865 0.635 0.865 0.635 0.42 0.045 0.42 0.045 0.15 0.115 0.15 0.115 0.35 0.705 0.35 0.705 0.525 0.755 0.525 0.755 0.66 0.705 0.66 0.705 0.935 0.485 0.935 0.485 1.25 0.415 1.25 0.415 0.935 0.115 0.935 0.115 1.25 0.045 1.25  ;
  END
END AND3_X1

MACRO AND3_X2
  CLASS core ;
  FOREIGN AND3_X2 0.0 0.0 ;
  ORIGIN 0 0 ;
  SYMMETRY X Y ;
  SITE FreePDK45_38x28_10R_NP_162NW_34O ;
  SIZE 1.14 BY 1.4 ;
  PIN A1
    DIRECTION INPUT ;
    ANTENNAPARTIALMETALAREA 0.021875 LAYER metal1 ;
    ANTENNAPARTIALMETALSIDEAREA 0.078 LAYER metal1 ;
    ANTENNAGATEAREA 0.05225 ;
    PORT
      LAYER metal1 ;
        POLYGON 0.06 0.525 0.185 0.525 0.185 0.7 0.06 0.7  ;
    END
  END A1
  PIN A2
    DIRECTION INPUT ;
    ANTENNAPARTIALMETALAREA 0.021875 LAYER metal1 ;
    ANTENNAPARTIALMETALSIDEAREA 0.078 LAYER metal1 ;
    ANTENNAGATEAREA 0.05225 ;
    PORT
      LAYER metal1 ;
        POLYGON 0.25 0.525 0.375 0.525 0.375 0.7 0.25 0.7  ;
    END
  END A2
  PIN A3
    DIRECTION INPUT ;
    ANTENNAPARTIALMETALAREA 0.02275 LAYER metal1 ;
    ANTENNAPARTIALMETALSIDEAREA 0.0793 LAYER metal1 ;
    ANTENNAGATEAREA 0.05225 ;
    PORT
      LAYER metal1 ;
        POLYGON 0.44 0.525 0.57 0.525 0.57 0.7 0.44 0.7  ;
    END
  END A3
  PIN Z
    DIRECTION OUTPUT ;
    ANTENNAPARTIALMETALAREA 0.0935 LAYER metal1 ;
    ANTENNAPARTIALMETALSIDEAREA 0.3081 LAYER metal1 ;
    ANTENNADIFFAREA 0.1463 ;
    PORT
      LAYER metal1 ;
        POLYGON 0.805 0.15 0.89 0.15 0.89 1.25 0.805 1.25  ;
    END
  END Z
  PIN VDD
    DIRECTION INOUT ;
    USE power ;
    SHAPE ABUTMENT ;
    PORT
      LAYER metal1 ;
        POLYGON 0 1.315 0.225 1.315 0.225 0.975 0.295 0.975 0.295 1.315 0.605 1.315 0.605 0.975 0.675 0.975 0.675 1.315 0.735 1.315 0.99 1.315 0.99 0.975 1.06 0.975 1.06 1.315 1.14 1.315 1.14 1.485 0.735 1.485 0 1.485  ;
    END
  END VDD
  PIN VSS
    DIRECTION INOUT ;
    USE ground ;
    SHAPE ABUTMENT ;
    PORT
      LAYER metal1 ;
        POLYGON 0 -0.085 1.14 -0.085 1.14 0.085 1.06 0.085 1.06 0.425 0.99 0.425 0.99 0.085 0.675 0.085 0.675 0.285 0.605 0.285 0.605 0.085 0 0.085  ;
    END
  END VSS
  OBS
      LAYER metal1 ;
        POLYGON 0.045 0.8 0.665 0.8 0.665 0.425 0.045 0.425 0.045 0.15 0.115 0.15 0.115 0.355 0.735 0.355 0.735 0.87 0.485 0.87 0.485 1.25 0.415 1.25 0.415 0.87 0.115 0.87 0.115 1.25 0.045 1.25  ;
  END
END AND3_X2

MACRO AND4_X1
  CLASS core ;
  FOREIGN AND4_X1 0.0 0.0 ;
  ORIGIN 0 0 ;
  SYMMETRY X Y ;
  SITE FreePDK45_38x28_10R_NP_162NW_34O ;
  SIZE 1.14 BY 1.4 ;
  PIN A1
    DIRECTION INPUT ;
    ANTENNAPARTIALMETALAREA 0.021875 LAYER metal1 ;
    ANTENNAPARTIALMETALSIDEAREA 0.078 LAYER metal1 ;
    ANTENNAGATEAREA 0.02625 ;
    PORT
      LAYER metal1 ;
        POLYGON 0.06 0.525 0.185 0.525 0.185 0.7 0.06 0.7  ;
    END
  END A1
  PIN A2
    DIRECTION INPUT ;
    ANTENNAPARTIALMETALAREA 0.021875 LAYER metal1 ;
    ANTENNAPARTIALMETALSIDEAREA 0.078 LAYER metal1 ;
    ANTENNAGATEAREA 0.02625 ;
    PORT
      LAYER metal1 ;
        POLYGON 0.25 0.525 0.375 0.525 0.375 0.7 0.25 0.7  ;
    END
  END A2
  PIN A3
    DIRECTION INPUT ;
    ANTENNAPARTIALMETALAREA 0.021875 LAYER metal1 ;
    ANTENNAPARTIALMETALSIDEAREA 0.078 LAYER metal1 ;
    ANTENNAGATEAREA 0.02625 ;
    PORT
      LAYER metal1 ;
        POLYGON 0.44 0.525 0.565 0.525 0.565 0.7 0.44 0.7  ;
    END
  END A3
  PIN A4
    DIRECTION INPUT ;
    ANTENNAPARTIALMETALAREA 0.02275 LAYER metal1 ;
    ANTENNAPARTIALMETALSIDEAREA 0.0793 LAYER metal1 ;
    ANTENNAGATEAREA 0.02625 ;
    PORT
      LAYER metal1 ;
        POLYGON 0.63 0.525 0.76 0.525 0.76 0.7 0.63 0.7  ;
    END
  END A4
  PIN Z
    DIRECTION OUTPUT ;
    ANTENNAPARTIALMETALAREA 0.099 LAYER metal1 ;
    ANTENNAPARTIALMETALSIDEAREA 0.3094 LAYER metal1 ;
    ANTENNADIFFAREA 0.109725 ;
    PORT
      LAYER metal1 ;
        POLYGON 0.99 0.15 1.08 0.15 1.08 1.25 0.99 1.25  ;
    END
  END Z
  PIN VDD
    DIRECTION INOUT ;
    USE power ;
    SHAPE ABUTMENT ;
    PORT
      LAYER metal1 ;
        POLYGON 0 1.315 0.04 1.315 0.04 0.975 0.11 0.975 0.11 1.315 0.415 1.315 0.415 0.975 0.485 0.975 0.485 1.315 0.795 1.315 0.795 0.975 0.865 0.975 0.865 1.315 0.925 1.315 1.14 1.315 1.14 1.485 0.925 1.485 0 1.485  ;
    END
  END VDD
  PIN VSS
    DIRECTION INOUT ;
    USE ground ;
    SHAPE ABUTMENT ;
    PORT
      LAYER metal1 ;
        POLYGON 0 -0.085 1.14 -0.085 1.14 0.085 0.865 0.085 0.865 0.285 0.795 0.285 0.795 0.085 0 0.085  ;
    END
  END VSS
  OBS
      LAYER metal1 ;
        POLYGON 0.235 0.84 0.855 0.84 0.855 0.42 0.045 0.42 0.045 0.15 0.115 0.15 0.115 0.35 0.925 0.35 0.925 0.91 0.675 0.91 0.675 1.25 0.605 1.25 0.605 0.91 0.305 0.91 0.305 1.25 0.235 1.25  ;
  END
END AND4_X1

MACRO AND4_X2
  CLASS core ;
  FOREIGN AND4_X2 0.0 0.0 ;
  ORIGIN 0 0 ;
  SYMMETRY X Y ;
  SITE FreePDK45_38x28_10R_NP_162NW_34O ;
  SIZE 1.33 BY 1.4 ;
  PIN A1
    DIRECTION INPUT ;
    ANTENNAPARTIALMETALAREA 0.021875 LAYER metal1 ;
    ANTENNAPARTIALMETALSIDEAREA 0.078 LAYER metal1 ;
    ANTENNAGATEAREA 0.05225 ;
    PORT
      LAYER metal1 ;
        POLYGON 0.06 0.525 0.185 0.525 0.185 0.7 0.06 0.7  ;
    END
  END A1
  PIN A2
    DIRECTION INPUT ;
    ANTENNAPARTIALMETALAREA 0.021875 LAYER metal1 ;
    ANTENNAPARTIALMETALSIDEAREA 0.078 LAYER metal1 ;
    ANTENNAGATEAREA 0.05225 ;
    PORT
      LAYER metal1 ;
        POLYGON 0.25 0.525 0.375 0.525 0.375 0.7 0.25 0.7  ;
    END
  END A2
  PIN A3
    DIRECTION INPUT ;
    ANTENNAPARTIALMETALAREA 0.021875 LAYER metal1 ;
    ANTENNAPARTIALMETALSIDEAREA 0.078 LAYER metal1 ;
    ANTENNAGATEAREA 0.05225 ;
    PORT
      LAYER metal1 ;
        POLYGON 0.44 0.525 0.565 0.525 0.565 0.7 0.44 0.7  ;
    END
  END A3
  PIN A4
    DIRECTION INPUT ;
    ANTENNAPARTIALMETALAREA 0.02275 LAYER metal1 ;
    ANTENNAPARTIALMETALSIDEAREA 0.0793 LAYER metal1 ;
    ANTENNAGATEAREA 0.05225 ;
    PORT
      LAYER metal1 ;
        POLYGON 0.63 0.525 0.76 0.525 0.76 0.7 0.63 0.7  ;
    END
  END A4
  PIN Z
    DIRECTION OUTPUT ;
    ANTENNAPARTIALMETALAREA 0.0935 LAYER metal1 ;
    ANTENNAPARTIALMETALSIDEAREA 0.3081 LAYER metal1 ;
    ANTENNADIFFAREA 0.1463 ;
    PORT
      LAYER metal1 ;
        POLYGON 0.995 0.15 1.08 0.15 1.08 1.25 0.995 1.25  ;
    END
  END Z
  PIN VDD
    DIRECTION INOUT ;
    USE power ;
    SHAPE ABUTMENT ;
    PORT
      LAYER metal1 ;
        POLYGON 0 1.315 0.04 1.315 0.04 0.975 0.11 0.975 0.11 1.315 0.415 1.315 0.415 0.975 0.485 0.975 0.485 1.315 0.795 1.315 0.795 0.975 0.865 0.975 0.865 1.315 0.925 1.315 1.18 1.315 1.18 0.975 1.25 0.975 1.25 1.315 1.33 1.315 1.33 1.485 0.925 1.485 0 1.485  ;
    END
  END VDD
  PIN VSS
    DIRECTION INOUT ;
    USE ground ;
    SHAPE ABUTMENT ;
    PORT
      LAYER metal1 ;
        POLYGON 0 -0.085 1.33 -0.085 1.33 0.085 1.25 0.085 1.25 0.425 1.18 0.425 1.18 0.085 0.865 0.085 0.865 0.27 0.795 0.27 0.795 0.085 0 0.085  ;
    END
  END VSS
  OBS
      LAYER metal1 ;
        POLYGON 0.235 0.8 0.855 0.8 0.855 0.425 0.045 0.425 0.045 0.15 0.115 0.15 0.115 0.355 0.925 0.355 0.925 0.87 0.675 0.87 0.675 1.25 0.605 1.25 0.605 0.87 0.305 0.87 0.305 1.25 0.235 1.25  ;
  END
END AND4_X2

MACRO AOI21_X1
  CLASS core ;
  FOREIGN AOI21_X1 0.0 0.0 ;
  ORIGIN 0 0 ;
  SYMMETRY X Y ;
  SITE FreePDK45_38x28_10R_NP_162NW_34O ;
  SIZE 0.76 BY 1.4 ;
  PIN B
    DIRECTION INPUT ;
    ANTENNAPARTIALMETALAREA 0.021875 LAYER metal1 ;
    ANTENNAPARTIALMETALSIDEAREA 0.078 LAYER metal1 ;
    ANTENNAGATEAREA 0.05225 ;
    PORT
      LAYER metal1 ;
        POLYGON 0.575 0.525 0.7 0.525 0.7 0.7 0.575 0.7  ;
    END
  END B
  PIN A1
    DIRECTION INPUT ;
    ANTENNAPARTIALMETALAREA 0.01925 LAYER metal1 ;
    ANTENNAPARTIALMETALSIDEAREA 0.0741 LAYER metal1 ;
    ANTENNAGATEAREA 0.05225 ;
    PORT
      LAYER metal1 ;
        POLYGON 0.4 0.525 0.51 0.525 0.51 0.7 0.4 0.7  ;
    END
  END A1
  PIN A2
    DIRECTION INPUT ;
    ANTENNAPARTIALMETALAREA 0.0245 LAYER metal1 ;
    ANTENNAPARTIALMETALSIDEAREA 0.0819 LAYER metal1 ;
    ANTENNAGATEAREA 0.05225 ;
    PORT
      LAYER metal1 ;
        POLYGON 0.06 0.525 0.2 0.525 0.2 0.7 0.06 0.7  ;
    END
  END A2
  PIN ZN
    DIRECTION OUTPUT ;
    ANTENNAPARTIALMETALAREA 0.083925 LAYER metal1 ;
    ANTENNAPARTIALMETALSIDEAREA 0.3185 LAYER metal1 ;
    ANTENNADIFFAREA 0.1463 ;
    PORT
      LAYER metal1 ;
        POLYGON 0.265 0.355 0.44 0.355 0.44 0.15 0.525 0.15 0.525 0.425 0.335 0.425 0.335 1.115 0.265 1.115  ;
    END
  END ZN
  PIN VDD
    DIRECTION INOUT ;
    USE power ;
    SHAPE ABUTMENT ;
    PORT
      LAYER metal1 ;
        POLYGON 0 1.315 0.525 1.315 0.645 1.315 0.645 0.905 0.715 0.905 0.715 1.315 0.76 1.315 0.76 1.485 0.525 1.485 0 1.485  ;
    END
  END VDD
  PIN VSS
    DIRECTION INOUT ;
    USE ground ;
    SHAPE ABUTMENT ;
    PORT
      LAYER metal1 ;
        POLYGON 0 -0.085 0.76 -0.085 0.76 0.085 0.715 0.085 0.715 0.355 0.645 0.355 0.645 0.085 0.15 0.085 0.15 0.425 0.08 0.425 0.08 0.085 0 0.085  ;
    END
  END VSS
  OBS
      LAYER metal1 ;
        POLYGON 0.085 0.905 0.155 0.905 0.155 1.18 0.455 1.18 0.455 0.905 0.525 0.905 0.525 1.25 0.085 1.25  ;
  END
END AOI21_X1

MACRO AOI21_X2
  CLASS core ;
  FOREIGN AOI21_X2 0.0 0.0 ;
  ORIGIN 0 0 ;
  SYMMETRY X Y ;
  SITE FreePDK45_38x28_10R_NP_162NW_34O ;
  SIZE 1.33 BY 1.4 ;
  PIN B
    DIRECTION INPUT ;
    ANTENNAPARTIALMETALAREA 0.0189 LAYER metal1 ;
    ANTENNAPARTIALMETALSIDEAREA 0.0715 LAYER metal1 ;
    ANTENNAGATEAREA 0.1045 ;
    PORT
      LAYER metal1 ;
        POLYGON 0.215 0.56 0.35 0.56 0.35 0.7 0.215 0.7  ;
    END
  END B
  PIN A1
    DIRECTION INPUT ;
    ANTENNAPARTIALMETALAREA 0.0189 LAYER metal1 ;
    ANTENNAPARTIALMETALSIDEAREA 0.0715 LAYER metal1 ;
    ANTENNAGATEAREA 0.1045 ;
    PORT
      LAYER metal1 ;
        POLYGON 0.765 0.56 0.9 0.56 0.9 0.7 0.765 0.7  ;
    END
  END A1
  PIN A2
    DIRECTION INPUT ;
    ANTENNAPARTIALMETALAREA 0.0833 LAYER metal1 ;
    ANTENNAPARTIALMETALSIDEAREA 0.3042 LAYER metal1 ;
    ANTENNAGATEAREA 0.1045 ;
    PORT
      LAYER metal1 ;
        POLYGON 0.57 0.525 0.7 0.525 0.7 0.77 1.11 0.77 1.11 0.525 1.18 0.525 1.18 0.84 0.63 0.84 0.63 0.7 0.57 0.7  ;
    END
  END A2
  PIN ZN
    DIRECTION OUTPUT ;
    ANTENNAPARTIALMETALAREA 0.159875 LAYER metal1 ;
    ANTENNAPARTIALMETALSIDEAREA 0.6006 LAYER metal1 ;
    ANTENNADIFFAREA 0.2926 ;
    PORT
      LAYER metal1 ;
        POLYGON 0.505 0.905 1.13 0.905 1.13 0.975 0.435 0.975 0.435 0.425 0.25 0.425 0.25 0.15 0.335 0.15 0.335 0.355 0.835 0.355 0.835 0.15 0.905 0.15 0.905 0.425 0.505 0.425  ;
    END
  END ZN
  PIN VDD
    DIRECTION INOUT ;
    USE power ;
    SHAPE ABUTMENT ;
    PORT
      LAYER metal1 ;
        POLYGON 0 1.315 0.265 1.315 0.265 1.205 0.335 1.205 0.335 1.315 1.285 1.315 1.33 1.315 1.33 1.485 1.285 1.485 0 1.485  ;
    END
  END VDD
  PIN VSS
    DIRECTION INOUT ;
    USE ground ;
    SHAPE ABUTMENT ;
    PORT
      LAYER metal1 ;
        POLYGON 0 -0.085 1.33 -0.085 1.33 0.085 1.285 0.085 1.285 0.425 1.215 0.425 1.215 0.085 0.525 0.085 0.525 0.285 0.455 0.285 0.455 0.085 0.15 0.085 0.15 0.425 0.08 0.425 0.08 0.085 0 0.085  ;
    END
  END VSS
  OBS
      LAYER metal1 ;
        POLYGON 0.085 0.975 0.155 0.975 0.155 1.07 1.215 1.07 1.215 0.975 1.285 0.975 1.285 1.25 1.215 1.25 1.215 1.14 0.155 1.14 0.155 1.25 0.085 1.25  ;
  END
END AOI21_X2

MACRO AOI22_X1
  CLASS core ;
  FOREIGN AOI22_X1 0.0 0.0 ;
  ORIGIN 0 0 ;
  SYMMETRY X Y ;
  SITE FreePDK45_38x28_10R_NP_162NW_34O ;
  SIZE 0.95 BY 1.4 ;
  PIN A1
    DIRECTION INPUT ;
    ANTENNAPARTIALMETALAREA 0.03 LAYER metal1 ;
    ANTENNAPARTIALMETALSIDEAREA 0.0949 LAYER metal1 ;
    ANTENNAGATEAREA 0.05225 ;
    PORT
      LAYER metal1 ;
        POLYGON 0.575 0.42 0.7 0.42 0.7 0.66 0.575 0.66  ;
    END
  END A1
  PIN A2
    DIRECTION INPUT ;
    ANTENNAPARTIALMETALAREA 0.03 LAYER metal1 ;
    ANTENNAPARTIALMETALSIDEAREA 0.0949 LAYER metal1 ;
    ANTENNAGATEAREA 0.05225 ;
    PORT
      LAYER metal1 ;
        POLYGON 0.765 0.42 0.89 0.42 0.89 0.66 0.765 0.66  ;
    END
  END A2
  PIN B1
    DIRECTION INPUT ;
    ANTENNAPARTIALMETALAREA 0.021875 LAYER metal1 ;
    ANTENNAPARTIALMETALSIDEAREA 0.078 LAYER metal1 ;
    ANTENNAGATEAREA 0.05225 ;
    PORT
      LAYER metal1 ;
        POLYGON 0.25 0.525 0.375 0.525 0.375 0.7 0.25 0.7  ;
    END
  END B1
  PIN B2
    DIRECTION INPUT ;
    ANTENNAPARTIALMETALAREA 0.021875 LAYER metal1 ;
    ANTENNAPARTIALMETALSIDEAREA 0.078 LAYER metal1 ;
    ANTENNAGATEAREA 0.05225 ;
    PORT
      LAYER metal1 ;
        POLYGON 0.06 0.525 0.185 0.525 0.185 0.7 0.06 0.7  ;
    END
  END B2
  PIN ZN
    DIRECTION OUTPUT ;
    ANTENNAPARTIALMETALAREA 0.07245 LAYER metal1 ;
    ANTENNAPARTIALMETALSIDEAREA 0.2873 LAYER metal1 ;
    ANTENNADIFFAREA 0.1463 ;
    PORT
      LAYER metal1 ;
        POLYGON 0.44 0.15 0.51 0.15 0.51 0.725 0.69 0.725 0.69 1.005 0.62 1.005 0.62 0.795 0.44 0.795  ;
    END
  END ZN
  PIN VDD
    DIRECTION INOUT ;
    USE power ;
    SHAPE ABUTMENT ;
    PORT
      LAYER metal1 ;
        POLYGON 0 1.315 0.24 1.315 0.24 1.205 0.31 1.205 0.31 1.315 0.88 1.315 0.95 1.315 0.95 1.485 0.88 1.485 0 1.485  ;
    END
  END VDD
  PIN VSS
    DIRECTION INOUT ;
    USE ground ;
    SHAPE ABUTMENT ;
    PORT
      LAYER metal1 ;
        POLYGON 0 -0.085 0.95 -0.085 0.95 0.085 0.88 0.085 0.88 0.355 0.81 0.355 0.81 0.085 0.125 0.085 0.125 0.355 0.055 0.355 0.055 0.085 0 0.085  ;
    END
  END VSS
  OBS
      LAYER metal1 ;
        POLYGON 0.06 0.865 0.13 0.865 0.13 1.07 0.435 1.07 0.435 0.865 0.505 0.865 0.505 1.07 0.81 1.07 0.81 0.865 0.88 0.865 0.88 1.14 0.06 1.14  ;
  END
END AOI22_X1

MACRO AOI22_X2
  CLASS core ;
  FOREIGN AOI22_X2 0.0 0.0 ;
  ORIGIN 0 0 ;
  SYMMETRY X Y ;
  SITE FreePDK45_38x28_10R_NP_162NW_34O ;
  SIZE 1.71 BY 1.4 ;
  PIN A1
    DIRECTION INPUT ;
    ANTENNAPARTIALMETALAREA 0.0189 LAYER metal1 ;
    ANTENNAPARTIALMETALSIDEAREA 0.0715 LAYER metal1 ;
    ANTENNAGATEAREA 0.1045 ;
    PORT
      LAYER metal1 ;
        POLYGON 1.155 0.56 1.29 0.56 1.29 0.7 1.155 0.7  ;
    END
  END A1
  PIN A2
    DIRECTION INPUT ;
    ANTENNAPARTIALMETALAREA 0.078825 LAYER metal1 ;
    ANTENNAPARTIALMETALSIDEAREA 0.2691 LAYER metal1 ;
    ANTENNAGATEAREA 0.1045 ;
    PORT
      LAYER metal1 ;
        POLYGON 0.955 0.425 1.55 0.425 1.55 0.66 1.48 0.66 1.48 0.495 1.08 0.495 1.08 0.7 0.955 0.7  ;
    END
  END A2
  PIN B1
    DIRECTION INPUT ;
    ANTENNAPARTIALMETALAREA 0.0189 LAYER metal1 ;
    ANTENNAPARTIALMETALSIDEAREA 0.0715 LAYER metal1 ;
    ANTENNAGATEAREA 0.1045 ;
    PORT
      LAYER metal1 ;
        POLYGON 0.395 0.56 0.53 0.56 0.53 0.7 0.395 0.7  ;
    END
  END B1
  PIN B2
    DIRECTION INPUT ;
    ANTENNAPARTIALMETALAREA 0.09785 LAYER metal1 ;
    ANTENNAPARTIALMETALSIDEAREA 0.3237 LAYER metal1 ;
    ANTENNAGATEAREA 0.1045 ;
    PORT
      LAYER metal1 ;
        POLYGON 0.06 0.525 0.195 0.525 0.195 0.765 0.685 0.765 0.685 0.525 0.755 0.525 0.755 0.835 0.06 0.835  ;
    END
  END B2
  PIN ZN
    DIRECTION OUTPUT ;
    ANTENNAPARTIALMETALAREA 0.2065 LAYER metal1 ;
    ANTENNAPARTIALMETALSIDEAREA 0.7072 LAYER metal1 ;
    ANTENNADIFFAREA 0.2926 ;
    PORT
      LAYER metal1 ;
        POLYGON 0.89 0.765 1.445 0.765 1.445 1.065 1.375 1.065 1.375 0.835 1.06 0.835 1.06 1.065 0.99 1.065 0.99 0.835 0.82 0.835 0.82 0.355 0.395 0.355 0.395 0.15 0.53 0.15 0.53 0.28 1.15 0.28 1.15 0.15 1.285 0.15 1.285 0.355 0.89 0.355  ;
    END
  END ZN
  PIN VDD
    DIRECTION INOUT ;
    USE power ;
    SHAPE ABUTMENT ;
    PORT
      LAYER metal1 ;
        POLYGON 0 1.315 0.23 1.315 0.23 1.035 0.3 1.035 0.3 1.315 0.61 1.315 0.61 1.035 0.68 1.035 0.68 1.315 1.63 1.315 1.71 1.315 1.71 1.485 1.63 1.485 0 1.485  ;
    END
  END VDD
  PIN VSS
    DIRECTION INOUT ;
    USE ground ;
    SHAPE ABUTMENT ;
    PORT
      LAYER metal1 ;
        POLYGON 0 -0.085 1.71 -0.085 1.71 0.085 1.63 0.085 1.63 0.36 1.56 0.36 1.56 0.085 0.905 0.085 0.905 0.205 0.77 0.205 0.77 0.085 0.115 0.085 0.115 0.39 0.045 0.39 0.045 0.085 0 0.085  ;
    END
  END VSS
  OBS
      LAYER metal1 ;
        POLYGON 0.05 0.9 0.87 0.9 0.87 1.18 1.18 1.18 1.18 0.975 1.25 0.975 1.25 1.18 1.56 1.18 1.56 0.975 1.63 0.975 1.63 1.25 0.8 1.25 0.8 0.97 0.49 0.97 0.49 1.25 0.42 1.25 0.42 0.97 0.12 0.97 0.12 1.25 0.05 1.25  ;
  END
END AOI22_X2

MACRO BUF_X1
  CLASS core ;
  FOREIGN BUF_X1 0.0 0.0 ;
  ORIGIN 0 0 ;
  SYMMETRY X Y ;
  SITE FreePDK45_38x28_10R_NP_162NW_34O ;
  SIZE 0.57 BY 1.4 ;
  PIN I
    DIRECTION INPUT ;
    ANTENNAPARTIALMETALAREA 0.02275 LAYER metal1 ;
    ANTENNAPARTIALMETALSIDEAREA 0.0793 LAYER metal1 ;
    ANTENNAGATEAREA 0.02625 ;
    PORT
      LAYER metal1 ;
        POLYGON 0.06 0.525 0.19 0.525 0.19 0.7 0.06 0.7  ;
    END
  END I
  PIN Z
    DIRECTION OUTPUT ;
    ANTENNAPARTIALMETALAREA 0.0945 LAYER metal1 ;
    ANTENNAPARTIALMETALSIDEAREA 0.2964 LAYER metal1 ;
    ANTENNADIFFAREA 0.109725 ;
    PORT
      LAYER metal1 ;
        POLYGON 0.42 0.19 0.51 0.19 0.51 1.24 0.42 1.24  ;
    END
  END Z
  PIN VDD
    DIRECTION INOUT ;
    USE power ;
    SHAPE ABUTMENT ;
    PORT
      LAYER metal1 ;
        POLYGON 0 1.315 0.225 1.315 0.225 0.965 0.295 0.965 0.295 1.315 0.355 1.315 0.57 1.315 0.57 1.485 0.355 1.485 0 1.485  ;
    END
  END VDD
  PIN VSS
    DIRECTION INOUT ;
    USE ground ;
    SHAPE ABUTMENT ;
    PORT
      LAYER metal1 ;
        POLYGON 0 -0.085 0.57 -0.085 0.57 0.085 0.295 0.085 0.295 0.325 0.225 0.325 0.225 0.085 0 0.085  ;
    END
  END VSS
  OBS
      LAYER metal1 ;
        POLYGON 0.045 0.83 0.285 0.83 0.285 0.46 0.045 0.46 0.045 0.19 0.115 0.19 0.115 0.39 0.355 0.39 0.355 0.9 0.115 0.9 0.115 1.24 0.045 1.24  ;
  END
END BUF_X1

MACRO BUF_X16
  CLASS core ;
  FOREIGN BUF_X16 0.0 0.0 ;
  ORIGIN 0 0 ;
  SYMMETRY X Y ;
  SITE FreePDK45_38x28_10R_NP_162NW_34O ;
  SIZE 4.75 BY 1.4 ;
  PIN I
    DIRECTION INPUT ;
    ANTENNAPARTIALMETALAREA 0.02375 LAYER metal1 ;
    ANTENNAPARTIALMETALSIDEAREA 0.0819 LAYER metal1 ;
    ANTENNAGATEAREA 0.418 ;
    PORT
      LAYER metal1 ;
        POLYGON 0.06 0.525 0.185 0.525 0.185 0.715 0.06 0.715  ;
    END
  END I
  PIN Z
    DIRECTION OUTPUT ;
    ANTENNAPARTIALMETALAREA 0.7364 LAYER metal1 ;
    ANTENNAPARTIALMETALSIDEAREA 2.0644 LAYER metal1 ;
    ANTENNADIFFAREA 1.1704 ;
    PORT
      LAYER metal1 ;
        POLYGON 1.77 0.15 1.84 0.15 1.84 0.28 2.14 0.28 2.14 0.15 2.21 0.15 2.21 0.28 2.52 0.28 2.52 0.15 2.59 0.15 2.59 0.28 2.9 0.28 2.9 0.15 2.97 0.15 2.97 0.28 3.28 0.28 3.28 0.15 3.35 0.15 3.35 0.28 3.66 0.28 3.66 0.15 3.73 0.15 3.73 0.28 4.04 0.28 4.04 0.15 4.11 0.15 4.11 0.28 4.42 0.28 4.42 0.15 4.49 0.15 4.49 0.925 4.42 0.925 4.42 0.42 4.12 0.42 4.12 0.925 4.05 0.925 4.05 0.42 3.73 0.42 3.73 0.925 3.66 0.925 3.66 0.42 3.35 0.42 3.35 0.925 3.28 0.925 3.28 0.42 2.97 0.42 2.97 0.925 2.9 0.925 2.9 0.42 2.59 0.42 2.59 0.925 2.52 0.925 2.52 0.42 2.21 0.42 2.21 0.925 2.14 0.925 2.14 0.42 1.84 0.42 1.84 0.925 1.77 0.925  ;
    END
  END Z
  PIN VDD
    DIRECTION INOUT ;
    USE power ;
    SHAPE ABUTMENT ;
    PORT
      LAYER metal1 ;
        POLYGON 0 1.315 0.055 1.315 0.055 0.975 0.125 0.975 0.125 1.315 0.43 1.315 0.43 0.975 0.5 0.975 0.5 1.315 0.81 1.315 0.81 0.975 0.88 0.975 0.88 1.315 1.19 1.315 1.19 0.975 1.26 0.975 1.26 1.315 1.57 1.315 1.57 1.205 1.64 1.205 1.64 1.315 1.95 1.315 1.95 1.205 2.02 1.205 2.02 1.315 2.33 1.315 2.33 1.205 2.4 1.205 2.4 1.315 2.71 1.315 2.71 1.205 2.78 1.205 2.78 1.315 3.09 1.315 3.09 1.205 3.16 1.205 3.16 1.315 3.47 1.315 3.47 1.205 3.54 1.205 3.54 1.315 3.85 1.315 3.85 1.205 3.92 1.205 3.92 1.315 4.23 1.315 4.23 1.205 4.3 1.205 4.3 1.315 4.61 1.315 4.61 1.205 4.63 1.205 4.68 1.205 4.68 1.315 4.75 1.315 4.75 1.485 4.63 1.485 0 1.485  ;
    END
  END VDD
  PIN VSS
    DIRECTION INOUT ;
    USE ground ;
    SHAPE ABUTMENT ;
    PORT
      LAYER metal1 ;
        POLYGON 0 -0.085 4.75 -0.085 4.75 0.085 4.68 0.085 4.68 0.2 4.61 0.2 4.61 0.085 4.3 0.085 4.3 0.2 4.23 0.2 4.23 0.085 3.92 0.085 3.92 0.2 3.85 0.2 3.85 0.085 3.54 0.085 3.54 0.2 3.47 0.2 3.47 0.085 3.16 0.085 3.16 0.2 3.09 0.2 3.09 0.085 2.78 0.085 2.78 0.2 2.71 0.2 2.71 0.085 2.4 0.085 2.4 0.2 2.33 0.2 2.33 0.085 2.02 0.085 2.02 0.2 1.95 0.2 1.95 0.085 1.64 0.085 1.64 0.34 1.57 0.34 1.57 0.085 1.26 0.085 1.26 0.34 1.19 0.34 1.19 0.085 0.88 0.085 0.88 0.34 0.81 0.34 0.81 0.085 0.5 0.085 0.5 0.34 0.43 0.34 0.43 0.085 0.125 0.085 0.125 0.34 0.055 0.34 0.055 0.085 0 0.085  ;
    END
  END VSS
  OBS
      LAYER metal1 ;
        POLYGON 0.25 0.15 0.32 0.15 0.32 0.525 0.62 0.525 0.62 0.15 0.69 0.15 0.69 0.525 1 0.525 1 0.15 1.07 0.15 1.07 0.525 1.38 0.525 1.38 0.15 1.45 0.15 1.45 0.525 1.705 0.525 1.705 1.05 2.69 1.05 2.69 0.525 2.76 0.525 2.76 1.05 3.45 1.05 3.45 0.525 3.52 0.525 3.52 1.05 4.56 1.05 4.56 0.525 4.63 0.525 4.63 1.12 1.635 1.12 1.635 0.66 1.45 0.66 1.45 1.25 1.38 1.25 1.38 0.66 1.07 0.66 1.07 1.25 1 1.25 1 0.66 0.69 0.66 0.69 1.25 0.62 1.25 0.62 0.66 0.32 0.66 0.32 1.25 0.25 1.25  ;
  END
END BUF_X16

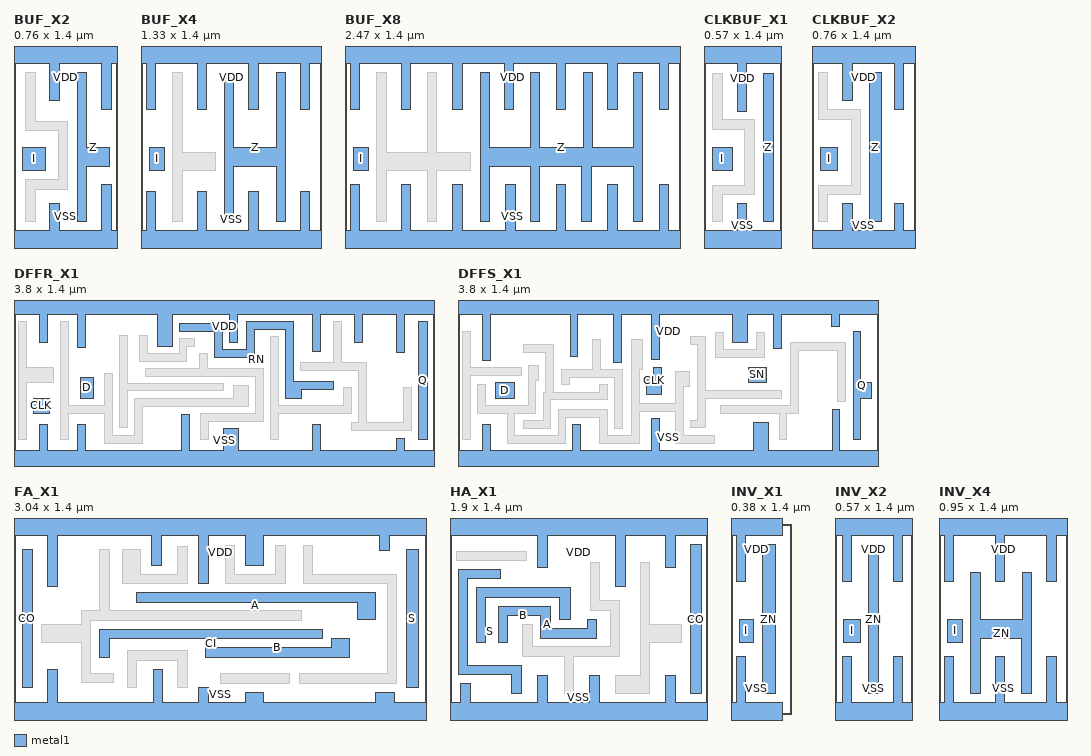
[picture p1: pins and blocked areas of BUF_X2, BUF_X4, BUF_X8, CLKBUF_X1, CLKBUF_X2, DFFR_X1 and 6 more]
MACRO BUF_X2
  CLASS core ;
  FOREIGN BUF_X2 0.0 0.0 ;
  ORIGIN 0 0 ;
  SYMMETRY X Y ;
  SITE FreePDK45_38x28_10R_NP_162NW_34O ;
  SIZE 0.76 BY 1.4 ;
  PIN I
    DIRECTION INPUT ;
    ANTENNAPARTIALMETALAREA 0.02975 LAYER metal1 ;
    ANTENNAPARTIALMETALSIDEAREA 0.0897 LAYER metal1 ;
    ANTENNAGATEAREA 0.05225 ;
    PORT
      LAYER metal1 ;
        POLYGON 0.06 0.525 0.23 0.525 0.23 0.7 0.06 0.7  ;
    END
  END I
  PIN Z
    DIRECTION OUTPUT ;
    ANTENNAPARTIALMETALAREA 0.1001 LAYER metal1 ;
    ANTENNAPARTIALMETALSIDEAREA 0.3471 LAYER metal1 ;
    ANTENNADIFFAREA 0.1463 ;
    PORT
      LAYER metal1 ;
        POLYGON 0.465 0.15 0.535 0.15 0.535 0.56 0.7 0.56 0.7 0.7 0.535 0.7 0.535 1.25 0.465 1.25  ;
    END
  END Z
  PIN VDD
    DIRECTION INOUT ;
    USE power ;
    SHAPE ABUTMENT ;
    PORT
      LAYER metal1 ;
        POLYGON 0 1.315 0.265 1.315 0.265 1.04 0.335 1.04 0.335 1.315 0.395 1.315 0.645 1.315 0.645 0.975 0.715 0.975 0.715 1.315 0.76 1.315 0.76 1.485 0.395 1.485 0 1.485  ;
    END
  END VDD
  PIN VSS
    DIRECTION INOUT ;
    USE ground ;
    SHAPE ABUTMENT ;
    PORT
      LAYER metal1 ;
        POLYGON 0 -0.085 0.76 -0.085 0.76 0.085 0.715 0.085 0.715 0.425 0.645 0.425 0.645 0.085 0.335 0.085 0.335 0.285 0.265 0.285 0.265 0.085 0 0.085  ;
    END
  END VSS
  OBS
      LAYER metal1 ;
        POLYGON 0.085 0.82 0.325 0.82 0.325 0.46 0.085 0.46 0.085 0.15 0.155 0.15 0.155 0.39 0.395 0.39 0.395 0.89 0.155 0.89 0.155 1.25 0.085 1.25  ;
  END
END BUF_X2

MACRO BUF_X4
  CLASS core ;
  FOREIGN BUF_X4 0.0 0.0 ;
  ORIGIN 0 0 ;
  SYMMETRY X Y ;
  SITE FreePDK45_38x28_10R_NP_162NW_34O ;
  SIZE 1.33 BY 1.4 ;
  PIN I
    DIRECTION INPUT ;
    ANTENNAPARTIALMETALAREA 0.01925 LAYER metal1 ;
    ANTENNAPARTIALMETALSIDEAREA 0.0741 LAYER metal1 ;
    ANTENNAGATEAREA 0.1045 ;
    PORT
      LAYER metal1 ;
        POLYGON 0.06 0.525 0.17 0.525 0.17 0.7 0.06 0.7  ;
    END
  END I
  PIN Z
    DIRECTION OUTPUT ;
    ANTENNAPARTIALMETALAREA 0.1974 LAYER metal1 ;
    ANTENNAPARTIALMETALSIDEAREA 0.6526 LAYER metal1 ;
    ANTENNADIFFAREA 0.2926 ;
    PORT
      LAYER metal1 ;
        POLYGON 0.615 0.15 0.685 0.15 0.685 0.56 0.995 0.56 0.995 0.15 1.065 0.15 1.065 1.25 0.995 1.25 0.995 0.7 0.685 0.7 0.685 1.25 0.615 1.25  ;
    END
  END Z
  PIN VDD
    DIRECTION INOUT ;
    USE power ;
    SHAPE ABUTMENT ;
    PORT
      LAYER metal1 ;
        POLYGON 0 1.315 0.04 1.315 0.04 0.975 0.11 0.975 0.11 1.315 0.415 1.315 0.415 0.975 0.485 0.975 0.485 1.315 0.55 1.315 0.795 1.315 0.795 0.975 0.865 0.975 0.865 1.315 1.175 1.315 1.175 0.975 1.245 0.975 1.245 1.315 1.33 1.315 1.33 1.485 0.55 1.485 0 1.485  ;
    END
  END VDD
  PIN VSS
    DIRECTION INOUT ;
    USE ground ;
    SHAPE ABUTMENT ;
    PORT
      LAYER metal1 ;
        POLYGON 0 -0.085 1.33 -0.085 1.33 0.085 1.245 0.085 1.245 0.37 1.175 0.37 1.175 0.085 0.865 0.085 0.865 0.37 0.795 0.37 0.795 0.085 0.485 0.085 0.485 0.37 0.415 0.37 0.415 0.085 0.11 0.085 0.11 0.37 0.04 0.37 0.04 0.085 0 0.085  ;
    END
  END VSS
  OBS
      LAYER metal1 ;
        POLYGON 0.235 0.15 0.305 0.15 0.305 0.525 0.55 0.525 0.55 0.66 0.305 0.66 0.305 1.25 0.235 1.25  ;
  END
END BUF_X4

MACRO BUF_X8
  CLASS core ;
  FOREIGN BUF_X8 0.0 0.0 ;
  ORIGIN 0 0 ;
  SYMMETRY X Y ;
  SITE FreePDK45_38x28_10R_NP_162NW_34O ;
  SIZE 2.47 BY 1.4 ;
  PIN I
    DIRECTION INPUT ;
    ANTENNAPARTIALMETALAREA 0.01925 LAYER metal1 ;
    ANTENNAPARTIALMETALSIDEAREA 0.0741 LAYER metal1 ;
    ANTENNAGATEAREA 0.209 ;
    PORT
      LAYER metal1 ;
        POLYGON 0.06 0.525 0.17 0.525 0.17 0.7 0.06 0.7  ;
    END
  END I
  PIN Z
    DIRECTION OUTPUT ;
    ANTENNAPARTIALMETALAREA 0.4368 LAYER metal1 ;
    ANTENNAPARTIALMETALSIDEAREA 1.3468 LAYER metal1 ;
    ANTENNADIFFAREA 0.5852 ;
    PORT
      LAYER metal1 ;
        POLYGON 0.995 0.15 1.065 0.15 1.065 0.56 1.365 0.56 1.365 0.15 1.435 0.15 1.435 0.56 1.745 0.56 1.745 0.15 1.815 0.15 1.815 0.56 2.125 0.56 2.125 0.15 2.195 0.15 2.195 1.25 2.125 1.25 2.125 0.7 1.825 0.7 1.825 1.25 1.755 1.25 1.755 0.7 1.435 0.7 1.435 1.25 1.365 1.25 1.365 0.7 1.065 0.7 1.065 1.25 0.995 1.25  ;
    END
  END Z
  PIN VDD
    DIRECTION INOUT ;
    USE power ;
    SHAPE ABUTMENT ;
    PORT
      LAYER metal1 ;
        POLYGON 0 1.315 0.04 1.315 0.04 0.975 0.11 0.975 0.11 1.315 0.415 1.315 0.415 0.975 0.485 0.975 0.485 1.315 0.795 1.315 0.795 0.975 0.865 0.975 0.865 1.315 0.925 1.315 1.175 1.315 1.175 0.975 1.245 0.975 1.245 1.315 1.555 1.315 1.555 0.975 1.625 0.975 1.625 1.315 1.935 1.315 1.935 0.975 2.005 0.975 2.005 1.315 2.315 1.315 2.315 0.975 2.385 0.975 2.385 1.315 2.47 1.315 2.47 1.485 0.925 1.485 0 1.485  ;
    END
  END VDD
  PIN VSS
    DIRECTION INOUT ;
    USE ground ;
    SHAPE ABUTMENT ;
    PORT
      LAYER metal1 ;
        POLYGON 0 -0.085 2.47 -0.085 2.47 0.085 2.385 0.085 2.385 0.425 2.315 0.425 2.315 0.085 2.005 0.085 2.005 0.425 1.935 0.425 1.935 0.085 1.625 0.085 1.625 0.425 1.555 0.425 1.555 0.085 1.255 0.085 1.255 0.425 1.185 0.425 1.185 0.085 0.865 0.085 0.865 0.425 0.795 0.425 0.795 0.085 0.485 0.085 0.485 0.425 0.415 0.425 0.415 0.085 0.11 0.085 0.11 0.425 0.04 0.425 0.04 0.085 0 0.085  ;
    END
  END VSS
  OBS
      LAYER metal1 ;
        POLYGON 0.235 0.15 0.305 0.15 0.305 0.525 0.605 0.525 0.605 0.15 0.675 0.15 0.675 0.525 0.925 0.525 0.925 0.66 0.675 0.66 0.675 1.25 0.605 1.25 0.605 0.66 0.305 0.66 0.305 1.25 0.235 1.25  ;
  END
END BUF_X8

MACRO CLKBUF_X1
  CLASS core ;
  FOREIGN CLKBUF_X1 0.0 0.0 ;
  ORIGIN 0 0 ;
  SYMMETRY X Y ;
  SITE FreePDK45_38x28_10R_NP_162NW_34O ;
  SIZE 0.57 BY 1.4 ;
  PIN I
    DIRECTION INPUT ;
    ANTENNAPARTIALMETALAREA 0.02625 LAYER metal1 ;
    ANTENNAPARTIALMETALSIDEAREA 0.0845 LAYER metal1 ;
    ANTENNAGATEAREA 0.0205 ;
    PORT
      LAYER metal1 ;
        POLYGON 0.06 0.525 0.21 0.525 0.21 0.7 0.06 0.7  ;
    END
  END I
  PIN Z
    DIRECTION OUTPUT ;
    ANTENNAPARTIALMETALAREA 0.0763 LAYER metal1 ;
    ANTENNAPARTIALMETALSIDEAREA 0.3016 LAYER metal1 ;
    ANTENNADIFFAREA 0.086625 ;
    PORT
      LAYER metal1 ;
        POLYGON 0.44 0.15 0.51 0.15 0.51 1.24 0.44 1.24  ;
    END
  END Z
  PIN VDD
    DIRECTION INOUT ;
    USE power ;
    SHAPE ABUTMENT ;
    PORT
      LAYER metal1 ;
        POLYGON 0 1.315 0.245 1.315 0.245 0.965 0.315 0.965 0.315 1.315 0.37 1.315 0.57 1.315 0.57 1.485 0.37 1.485 0 1.485  ;
    END
  END VDD
  PIN VSS
    DIRECTION INOUT ;
    USE ground ;
    SHAPE ABUTMENT ;
    PORT
      LAYER metal1 ;
        POLYGON 0 -0.085 0.57 -0.085 0.57 0.085 0.315 0.085 0.315 0.285 0.245 0.285 0.245 0.085 0 0.085  ;
    END
  END VSS
  OBS
      LAYER metal1 ;
        POLYGON 0.065 0.83 0.3 0.83 0.3 0.42 0.065 0.42 0.065 0.15 0.135 0.15 0.135 0.35 0.37 0.35 0.37 0.9 0.135 0.9 0.135 1.24 0.065 1.24  ;
  END
END CLKBUF_X1

MACRO CLKBUF_X2
  CLASS core ;
  FOREIGN CLKBUF_X2 0.0 0.0 ;
  ORIGIN 0 0 ;
  SYMMETRY X Y ;
  SITE FreePDK45_38x28_10R_NP_162NW_34O ;
  SIZE 0.76 BY 1.4 ;
  PIN I
    DIRECTION INPUT ;
    ANTENNAPARTIALMETALAREA 0.02275 LAYER metal1 ;
    ANTENNAPARTIALMETALSIDEAREA 0.0793 LAYER metal1 ;
    ANTENNAGATEAREA 0.04125 ;
    PORT
      LAYER metal1 ;
        POLYGON 0.06 0.525 0.19 0.525 0.19 0.7 0.06 0.7  ;
    END
  END I
  PIN Z
    DIRECTION OUTPUT ;
    ANTENNAPARTIALMETALAREA 0.0935 LAYER metal1 ;
    ANTENNAPARTIALMETALSIDEAREA 0.3081 LAYER metal1 ;
    ANTENNADIFFAREA 0.1155 ;
    PORT
      LAYER metal1 ;
        POLYGON 0.425 0.15 0.51 0.15 0.51 1.25 0.425 1.25  ;
    END
  END Z
  PIN VDD
    DIRECTION INOUT ;
    USE power ;
    SHAPE ABUTMENT ;
    PORT
      LAYER metal1 ;
        POLYGON 0 1.315 0.225 1.315 0.225 1.04 0.295 1.04 0.295 1.315 0.36 1.315 0.605 1.315 0.605 0.975 0.675 0.975 0.675 1.315 0.76 1.315 0.76 1.485 0.36 1.485 0 1.485  ;
    END
  END VDD
  PIN VSS
    DIRECTION INOUT ;
    USE ground ;
    SHAPE ABUTMENT ;
    PORT
      LAYER metal1 ;
        POLYGON 0 -0.085 0.76 -0.085 0.76 0.085 0.675 0.085 0.675 0.285 0.605 0.285 0.605 0.085 0.295 0.085 0.295 0.285 0.225 0.285 0.225 0.085 0 0.085  ;
    END
  END VSS
  OBS
      LAYER metal1 ;
        POLYGON 0.045 0.905 0.29 0.905 0.29 0.42 0.045 0.42 0.045 0.15 0.115 0.15 0.115 0.35 0.36 0.35 0.36 0.975 0.115 0.975 0.115 1.25 0.045 1.25  ;
  END
END CLKBUF_X2

MACRO DFFR_X1
  CLASS core ;
  FOREIGN DFFR_X1 0.0 0.0 ;
  ORIGIN 0 0 ;
  SYMMETRY X Y ;
  SITE FreePDK45_38x28_10R_NP_162NW_34O ;
  SIZE 3.8 BY 1.4 ;
  PIN D
    DIRECTION INPUT ;
    ANTENNAPARTIALMETALAREA 0.0222 LAYER metal1 ;
    ANTENNAPARTIALMETALSIDEAREA 0.0793 LAYER metal1 ;
    ANTENNAGATEAREA 0.03475 ;
    PORT
      LAYER metal1 ;
        POLYGON 0.6 0.56 0.72 0.56 0.72 0.745 0.6 0.745  ;
    END
  END D
  PIN RN
    DIRECTION INPUT ;
    ANTENNAPARTIALMETALAREA 0.181 LAYER metal1 ;
    ANTENNAPARTIALMETALSIDEAREA 0.6682 LAYER metal1 ;
    ANTENNAGATEAREA 0.03525 ;
    PORT
      LAYER metal1 ;
        POLYGON 1.495 1.165 1.63 1.165 1.815 1.165 1.815 0.93 2.175 0.93 2.175 1.18 2.255 1.18 2.455 1.18 2.455 0.56 2.6 0.56 2.6 0.64 2.89 0.64 2.89 0.71 2.525 0.71 2.525 1.25 2.255 1.25 2.105 1.25 2.105 1 1.885 1 1.885 1.235 1.63 1.235 1.495 1.235  ;
    END
  END RN
  PIN CLK
    DIRECTION INPUT ;
    ANTENNAPARTIALMETALAREA 0.0203 LAYER metal1 ;
    ANTENNAPARTIALMETALSIDEAREA 0.0741 LAYER metal1 ;
    ANTENNAGATEAREA 0.02625 ;
    PORT
      LAYER metal1 ;
        POLYGON 0.175 0.42 0.32 0.42 0.32 0.56 0.175 0.56  ;
    END
  END CLK
  PIN Q
    DIRECTION OUTPUT ;
    ANTENNAPARTIALMETALAREA 0.0852 LAYER metal1 ;
    ANTENNAPARTIALMETALSIDEAREA 0.2977 LAYER metal1 ;
    ANTENNADIFFAREA 0.109725 ;
    PORT
      LAYER metal1 ;
        POLYGON 3.66 0.185 3.74 0.185 3.74 1.25 3.66 1.25  ;
    END
  END Q
  PIN VDD
    DIRECTION INOUT ;
    USE power ;
    SHAPE ABUTMENT ;
    PORT
      LAYER metal1 ;
        POLYGON 0 1.315 0.23 1.315 0.23 1.065 0.3 1.065 0.3 1.315 0.355 1.315 0.575 1.315 0.575 1.015 0.645 1.015 0.645 1.315 1.295 1.315 1.295 1.03 1.43 1.03 1.43 1.315 1.63 1.315 1.95 1.315 1.95 1.065 2.02 1.065 2.02 1.315 2.255 1.315 2.7 1.315 2.7 0.98 2.77 0.98 2.77 1.315 3.08 1.315 3.08 1.065 3.15 1.065 3.15 1.315 3.465 1.315 3.465 0.975 3.535 0.975 3.535 1.315 3.595 1.315 3.8 1.315 3.8 1.485 3.595 1.485 2.255 1.485 1.63 1.485 0.355 1.485 0 1.485  ;
    END
  END VDD
  PIN VSS
    DIRECTION INOUT ;
    USE ground ;
    SHAPE ABUTMENT ;
    PORT
      LAYER metal1 ;
        POLYGON 0 -0.085 3.8 -0.085 3.8 0.085 3.535 0.085 3.535 0.195 3.465 0.195 3.465 0.085 2.77 0.085 2.77 0.32 2.7 0.32 2.7 0.085 2.03 0.085 2.03 0.285 1.895 0.285 1.895 0.085 1.585 0.085 1.585 0.41 1.515 0.41 1.515 0.085 0.645 0.085 0.645 0.32 0.575 0.32 0.575 0.085 0.3 0.085 0.3 0.32 0.23 0.32 0.23 0.085 0 0.085  ;
    END
  END VSS
  OBS
      LAYER metal1 ;
        POLYGON 0.04 0.185 0.11 0.185 0.11 0.7 0.355 0.7 0.355 0.835 0.11 0.835 0.11 1.25 0.04 1.25  ;
        POLYGON 1.135 0.895 1.565 0.895 1.565 1.025 1.63 1.025 1.63 1.095 1.495 1.095 1.495 0.965 1.205 0.965 1.205 1.125 1.135 1.125  ;
        POLYGON 0.955 0.29 1.025 0.29 1.025 0.625 1.895 0.625 1.895 0.695 1.025 0.695 1.025 1.125 0.955 1.125  ;
        POLYGON 0.42 0.185 0.49 0.185 0.49 0.425 0.82 0.425 0.82 0.15 1.16 0.15 1.16 0.485 2.12 0.485 2.12 0.67 1.985 0.67 1.985 0.555 1.09 0.555 1.09 0.22 0.89 0.22 0.89 0.785 0.82 0.785 0.82 0.495 0.49 0.495 0.49 1.25 0.42 1.25  ;
        POLYGON 1.19 0.76 2.185 0.76 2.185 0.42 1.69 0.42 1.69 0.185 1.76 0.185 1.76 0.35 2.255 0.35 2.255 0.83 1.75 0.83 1.75 0.96 1.68 0.96 1.68 0.83 1.19 0.83  ;
        POLYGON 2.32 0.185 2.39 0.185 2.39 0.425 3.05 0.425 3.05 0.66 2.98 0.66 2.98 0.495 2.39 0.495 2.39 1.115 2.32 1.115  ;
        POLYGON 2.59 0.81 3.115 0.81 3.115 0.335 3.05 0.335 3.05 0.265 3.595 0.265 3.595 0.66 3.525 0.66 3.525 0.335 3.185 0.335 3.185 0.88 2.96 0.88 2.96 1.25 2.89 1.25 2.89 0.88 2.59 0.88  ;
  END
END DFFR_X1

MACRO DFFS_X1
  CLASS core ;
  FOREIGN DFFS_X1 0.0 0.0 ;
  ORIGIN 0 0 ;
  SYMMETRY X Y ;
  SITE FreePDK45_38x28_10R_NP_162NW_34O ;
  SIZE 3.8 BY 1.4 ;
  PIN D
    DIRECTION INPUT ;
    ANTENNAPARTIALMETALAREA 0.0238 LAYER metal1 ;
    ANTENNAPARTIALMETALSIDEAREA 0.0806 LAYER metal1 ;
    ANTENNAGATEAREA 0.03475 ;
    PORT
      LAYER metal1 ;
        POLYGON 0.34 0.56 0.51 0.56 0.51 0.7 0.34 0.7  ;
    END
  END D
  PIN SN
    DIRECTION INPUT ;
    ANTENNAPARTIALMETALAREA 0.0231 LAYER metal1 ;
    ANTENNAPARTIALMETALSIDEAREA 0.0793 LAYER metal1 ;
    ANTENNAGATEAREA 0.03525 ;
    PORT
      LAYER metal1 ;
        POLYGON 2.625 0.7 2.79 0.7 2.79 0.84 2.625 0.84  ;
    END
  END SN
  PIN CLK
    DIRECTION INPUT ;
    ANTENNAPARTIALMETALAREA 0.026275 LAYER metal1 ;
    ANTENNAPARTIALMETALSIDEAREA 0.1001 LAYER metal1 ;
    ANTENNAGATEAREA 0.02625 ;
    PORT
      LAYER metal1 ;
        POLYGON 1.705 0.59 1.84 0.59 1.84 0.84 1.77 0.84 1.77 0.725 1.705 0.725  ;
    END
  END CLK
  PIN Q
    DIRECTION OUTPUT ;
    ANTENNAPARTIALMETALAREA 0.08155 LAYER metal1 ;
    ANTENNAPARTIALMETALSIDEAREA 0.2964 LAYER metal1 ;
    ANTENNADIFFAREA 0.109725 ;
    PORT
      LAYER metal1 ;
        POLYGON 3.575 0.185 3.645 0.185 3.645 0.56 3.74 0.56 3.74 0.7 3.645 0.7 3.645 1.16 3.575 1.16  ;
    END
  END Q
  PIN VDD
    DIRECTION INOUT ;
    USE power ;
    SHAPE ABUTMENT ;
    PORT
      LAYER metal1 ;
        POLYGON 0 1.315 0.225 1.315 0.225 0.9 0.295 0.9 0.295 1.315 0.57 1.315 1.015 1.315 1.015 0.94 1.085 0.94 1.085 1.315 1.41 1.315 1.41 0.885 1.48 0.885 1.48 1.315 1.485 1.315 1.755 1.315 1.755 0.905 1.825 0.905 1.825 1.315 2.48 1.315 2.48 1.065 2.615 1.065 2.615 1.315 2.77 1.315 2.855 1.315 2.855 1.005 2.925 1.005 2.925 1.315 3.38 1.315 3.38 1.205 3.45 1.205 3.45 1.315 3.505 1.315 3.8 1.315 3.8 1.485 3.505 1.485 2.925 1.485 2.77 1.485 1.485 1.485 0.57 1.485 0 1.485  ;
    END
  END VDD
  PIN VSS
    DIRECTION INOUT ;
    USE ground ;
    SHAPE ABUTMENT ;
    PORT
      LAYER metal1 ;
        POLYGON 0 -0.085 3.8 -0.085 3.8 0.085 3.455 0.085 3.455 0.46 3.385 0.46 3.385 0.085 2.805 0.085 2.805 0.34 2.67 0.34 2.67 0.085 1.82 0.085 1.82 0.375 1.75 0.375 1.75 0.085 1.11 0.085 1.11 0.32 1.04 0.32 1.04 0.085 0.295 0.085 0.295 0.32 0.225 0.32 0.225 0.085 0 0.085  ;
    END
  END VSS
  OBS
      LAYER metal1 ;
        POLYGON 0.04 0.185 0.11 0.185 0.11 0.765 0.57 0.765 0.57 0.835 0.11 0.835 0.11 1.16 0.04 1.16  ;
        POLYGON 0.59 0.975 0.795 0.975 0.795 0.615 0.77 0.615 0.77 0.355 0.59 0.355 0.59 0.285 0.84 0.285 0.84 0.545 1.35 0.545 1.35 0.685 1.28 0.685 1.28 0.615 0.865 0.615 0.865 1.045 0.59 1.045  ;
        POLYGON 0.94 0.685 1.01 0.685 1.01 0.75 1.415 0.75 1.415 0.285 1.485 0.285 1.485 0.82 1.29 0.82 1.29 1.09 1.22 1.09 1.22 0.82 0.94 0.82  ;
        POLYGON 0.175 0.42 0.445 0.42 0.445 0.15 0.975 0.15 0.975 0.385 1.28 0.385 1.28 0.15 1.64 0.15 1.64 0.44 1.97 0.44 1.97 0.15 2.32 0.15 2.32 0.22 2.04 0.22 2.04 0.665 2.095 0.665 2.095 0.8 1.97 0.8 1.97 0.51 1.64 0.51 1.64 0.815 1.67 0.815 1.67 1.09 1.57 1.09 1.57 0.22 1.35 0.22 1.35 0.455 0.905 0.455 0.905 0.22 0.515 0.22 0.515 0.42 0.705 0.42 0.705 0.72 0.73 0.72 0.73 0.855 0.635 0.855 0.635 0.49 0.245 0.49 0.245 0.685 0.175 0.685  ;
        POLYGON 2.33 0.93 2.77 0.93 2.77 1.15 2.7 1.15 2.7 1 2.4 1 2.4 1.15 2.33 1.15  ;
        POLYGON 2.105 1.045 2.17 1.045 2.17 0.36 2.105 0.36 2.105 0.29 2.24 0.29 2.24 0.56 2.925 0.56 2.925 0.63 2.24 0.63 2.24 1.115 2.105 1.115  ;
        POLYGON 2.375 0.42 2.905 0.42 2.905 0.185 2.975 0.185 2.975 0.42 3.08 0.42 3.08 0.995 3.435 0.995 3.435 0.525 3.505 0.525 3.505 1.065 3.01 1.065 3.01 0.49 2.375 0.49  ;
  END
END DFFS_X1

MACRO FA_X1
  CLASS core ;
  FOREIGN FA_X1 0.0 0.0 ;
  ORIGIN 0 0 ;
  SYMMETRY X Y ;
  SITE FreePDK45_38x28_10R_NP_162NW_34O ;
  SIZE 3.04 BY 1.4 ;
  PIN A
    DIRECTION INPUT ;
    ANTENNAPARTIALMETALAREA 0.1391 LAYER metal1 ;
    ANTENNAPARTIALMETALSIDEAREA 0.507 LAYER metal1 ;
    ANTENNAGATEAREA 0.105 ;
    PORT
      LAYER metal1 ;
        POLYGON 0.905 0.825 2.115 0.825 2.53 0.825 2.53 0.7 2.66 0.7 2.66 0.895 2.115 0.895 0.905 0.895  ;
    END
  END A
  PIN B
    DIRECTION INPUT ;
    ANTENNAPARTIALMETALAREA 0.0833 LAYER metal1 ;
    ANTENNAPARTIALMETALSIDEAREA 0.312 LAYER metal1 ;
    ANTENNAGATEAREA 0.105 ;
    PORT
      LAYER metal1 ;
        POLYGON 1.41 0.42 2.03 0.42 2.47 0.42 2.47 0.56 2.34 0.56 2.34 0.49 2.03 0.49 1.41 0.49  ;
    END
  END B
  PIN CI
    DIRECTION INPUT ;
    ANTENNAPARTIALMETALAREA 0.1246 LAYER metal1 ;
    ANTENNAPARTIALMETALSIDEAREA 0.481 LAYER metal1 ;
    ANTENNAGATEAREA 0.07875 ;
    PORT
      LAYER metal1 ;
        POLYGON 0.63 0.42 0.7 0.42 0.7 0.555 1.275 0.555 2.03 0.555 2.275 0.555 2.275 0.625 2.03 0.625 1.275 0.625 0.63 0.625  ;
    END
  END CI
  PIN CO
    DIRECTION OUTPUT ;
    ANTENNAPARTIALMETALAREA 0.0765 LAYER metal1 ;
    ANTENNAPARTIALMETALSIDEAREA 0.2847 LAYER metal1 ;
    ANTENNADIFFAREA 0.109725 ;
    PORT
      LAYER metal1 ;
        POLYGON 0.06 0.195 0.135 0.195 0.135 1.215 0.06 1.215  ;
    END
  END CO
  PIN S
    DIRECTION OUTPUT ;
    ANTENNAPARTIALMETALAREA 0.0918 LAYER metal1 ;
    ANTENNAPARTIALMETALSIDEAREA 0.2886 LAYER metal1 ;
    ANTENNADIFFAREA 0.109725 ;
    PORT
      LAYER metal1 ;
        POLYGON 2.89 0.195 2.98 0.195 2.98 1.215 2.89 1.215  ;
    END
  END S
  PIN VDD
    DIRECTION INOUT ;
    USE power ;
    SHAPE ABUTMENT ;
    PORT
      LAYER metal1 ;
        POLYGON 0 1.315 0.25 1.315 0.25 0.94 0.32 0.94 0.32 1.315 1.015 1.315 1.015 1.095 1.085 1.095 1.085 1.315 1.275 1.315 1.36 1.315 1.36 0.965 1.43 0.965 1.43 1.315 1.705 1.315 1.705 1.095 1.84 1.095 1.84 1.315 2 1.315 2.115 1.315 2.695 1.315 2.695 1.205 2.765 1.205 2.765 1.315 2.82 1.315 3.04 1.315 3.04 1.485 2.82 1.485 2.115 1.485 2 1.485 1.275 1.485 0 1.485  ;
    END
  END VDD
  PIN VSS
    DIRECTION INOUT ;
    USE ground ;
    SHAPE ABUTMENT ;
    PORT
      LAYER metal1 ;
        POLYGON 0 -0.085 3.04 -0.085 3.04 0.085 2.8 0.085 2.8 0.16 2.665 0.16 2.665 0.085 1.84 0.085 1.84 0.16 1.705 0.16 1.705 0.085 1.43 0.085 1.43 0.195 1.36 0.195 1.36 0.085 1.095 0.085 1.095 0.33 1.025 0.33 1.025 0.085 0.32 0.085 0.32 0.33 0.25 0.33 0.25 0.085 0 0.085  ;
    END
  END VSS
  OBS
      LAYER metal1 ;
        POLYGON 0.835 0.195 0.905 0.195 0.905 0.395 1.205 0.395 1.205 0.195 1.275 0.195 1.275 0.465 0.835 0.465  ;
        POLYGON 0.8 0.96 1.275 0.96 1.275 1.235 1.205 1.235 1.205 1.03 0.935 1.03 0.935 1.215 0.8 1.215  ;
        POLYGON 1.555 0.96 2 0.96 2 1.24 1.93 1.24 1.93 1.03 1.625 1.03 1.625 1.24 1.555 1.24  ;
        POLYGON 1.52 0.225 2.03 0.225 2.03 0.295 1.52 0.295  ;
        POLYGON 0.565 0.69 2.115 0.69 2.115 0.76 0.7 0.76 0.7 1.215 0.63 1.215 0.63 0.76 0.495 0.76 0.495 0.66 0.205 0.66 0.205 0.525 0.495 0.525 0.495 0.23 0.735 0.23 0.735 0.3 0.565 0.3  ;
        POLYGON 2.13 0.96 2.75 0.96 2.75 0.295 2.1 0.295 2.1 0.225 2.82 0.225 2.82 1.03 2.2 1.03 2.2 1.24 2.13 1.24  ;
  END
END FA_X1

MACRO HA_X1
  CLASS core ;
  FOREIGN HA_X1 0.0 0.0 ;
  ORIGIN 0 0 ;
  SYMMETRY X Y ;
  SITE FreePDK45_38x28_10R_NP_162NW_34O ;
  SIZE 1.9 BY 1.4 ;
  PIN A
    DIRECTION INPUT ;
    ANTENNAPARTIALMETALAREA 0.0812 LAYER metal1 ;
    ANTENNAPARTIALMETALSIDEAREA 0.3198 LAYER metal1 ;
    ANTENNAGATEAREA 0.10475 ;
    PORT
      LAYER metal1 ;
        POLYGON 0.355 0.525 0.425 0.525 0.425 0.725 0.67 0.725 0.67 0.56 1.08 0.56 1.08 0.7 1.01 0.7 1.01 0.63 0.74 0.63 0.74 0.795 0.355 0.795  ;
    END
  END A
  PIN B
    DIRECTION INPUT ;
    ANTENNAPARTIALMETALAREA 0.0857 LAYER metal1 ;
    ANTENNAPARTIALMETALSIDEAREA 0.3276 LAYER metal1 ;
    ANTENNAGATEAREA 0.10475 ;
    PORT
      LAYER metal1 ;
        POLYGON 0.195 0.525 0.265 0.525 0.265 0.86 0.805 0.86 0.805 0.7 0.89 0.7 0.89 0.93 0.195 0.93  ;
    END
  END B
  PIN CO
    DIRECTION OUTPUT ;
    ANTENNAPARTIALMETALAREA 0.088 LAYER metal1 ;
    ANTENNAPARTIALMETALSIDEAREA 0.3068 LAYER metal1 ;
    ANTENNADIFFAREA 0.109725 ;
    PORT
      LAYER metal1 ;
        POLYGON 1.77 0.15 1.85 0.15 1.85 1.25 1.77 1.25  ;
    END
  END CO
  PIN S
    DIRECTION OUTPUT ;
    ANTENNAPARTIALMETALAREA 0.1085 LAYER metal1 ;
    ANTENNAPARTIALMETALSIDEAREA 0.4212 LAYER metal1 ;
    ANTENNADIFFAREA 0.1463 ;
    PORT
      LAYER metal1 ;
        POLYGON 0.06 0.29 0.455 0.29 0.455 0.15 0.525 0.15 0.525 0.36 0.13 0.36 0.13 0.995 0.37 0.995 0.37 1.065 0.06 1.065  ;
    END
  END S
  PIN VDD
    DIRECTION INOUT ;
    USE power ;
    SHAPE ABUTMENT ;
    PORT
      LAYER metal1 ;
        POLYGON 0 1.315 0.56 1.315 0.645 1.315 0.645 1.08 0.715 1.08 0.715 1.315 1.22 1.315 1.22 0.94 1.25 0.94 1.29 0.94 1.29 1.315 1.59 1.315 1.59 1.08 1.66 1.08 1.66 1.315 1.705 1.315 1.9 1.315 1.9 1.485 1.705 1.485 1.25 1.485 0.56 1.485 0 1.485  ;
    END
  END VDD
  PIN VSS
    DIRECTION INOUT ;
    USE ground ;
    SHAPE ABUTMENT ;
    PORT
      LAYER metal1 ;
        POLYGON 0 -0.085 1.9 -0.085 1.9 0.085 1.66 0.085 1.66 0.285 1.59 0.285 1.59 0.085 1.1 0.085 1.1 0.285 1.03 0.285 1.03 0.085 0.715 0.085 0.715 0.285 0.645 0.285 0.645 0.085 0.15 0.085 0.15 0.225 0.08 0.225 0.08 0.085 0 0.085  ;
    END
  END VSS
  OBS
      LAYER metal1 ;
        POLYGON 0.05 1.13 0.56 1.13 0.56 1.2 0.05 1.2  ;
        POLYGON 1.035 0.765 1.18 0.765 1.18 0.495 0.605 0.495 0.605 0.66 0.535 0.66 0.535 0.425 0.84 0.425 0.84 0.15 0.91 0.15 0.91 0.425 1.25 0.425 1.25 0.835 1.105 0.835 1.105 1.115 1.035 1.115  ;
        POLYGON 1.22 0.15 1.47 0.15 1.47 0.525 1.705 0.525 1.705 0.66 1.47 0.66 1.47 1.115 1.4 1.115 1.4 0.285 1.22 0.285  ;
  END
END HA_X1

MACRO INV_X1
  CLASS core ;
  FOREIGN INV_X1 0.0 0.0 ;
  ORIGIN 0 0 ;
  SYMMETRY X Y ;
  SITE FreePDK45_38x28_10R_NP_162NW_34O ;
  SIZE 0.38 BY 1.4 ;
  PIN I
    DIRECTION INPUT ;
    ANTENNAPARTIALMETALAREA 0.018375 LAYER metal1 ;
    ANTENNAPARTIALMETALSIDEAREA 0.0728 LAYER metal1 ;
    ANTENNAGATEAREA 0.05225 ;
    PORT
      LAYER metal1 ;
        POLYGON 0.06 0.525 0.165 0.525 0.165 0.7 0.06 0.7  ;
    END
  END I
  PIN ZN
    DIRECTION OUTPUT ;
    ANTENNAPARTIALMETALAREA 0.1045 LAYER metal1 ;
    ANTENNAPARTIALMETALSIDEAREA 0.3107 LAYER metal1 ;
    ANTENNADIFFAREA 0.109725 ;
    PORT
      LAYER metal1 ;
        POLYGON 0.23 0.15 0.325 0.15 0.325 1.25 0.23 1.25  ;
    END
  END ZN
  PIN VDD
    DIRECTION INOUT ;
    USE power ;
    SHAPE ABUTMENT ;
    PORT
      LAYER metal1 ;
        POLYGON 0 1.315 0.04 1.315 0.04 0.975 0.11 0.975 0.11 1.315 0.38 1.315 0.38 1.485 0 1.485  ;
    END
  END VDD
  PIN VSS
    DIRECTION INOUT ;
    USE ground ;
    SHAPE ABUTMENT ;
    PORT
      LAYER metal1 ;
        POLYGON 0 -0.085 0.38 -0.085 0.38 0.085 0.11 0.085 0.11 0.425 0.04 0.425 0.04 0.085 0 0.085  ;
    END
  END VSS
END INV_X1

MACRO INV_X2
  CLASS core ;
  FOREIGN INV_X2 0.0 0.0 ;
  ORIGIN 0 0 ;
  SYMMETRY X Y ;
  SITE FreePDK45_38x28_10R_NP_162NW_34O ;
  SIZE 0.57 BY 1.4 ;
  PIN I
    DIRECTION INPUT ;
    ANTENNAPARTIALMETALAREA 0.021875 LAYER metal1 ;
    ANTENNAPARTIALMETALSIDEAREA 0.078 LAYER metal1 ;
    ANTENNAGATEAREA 0.1045 ;
    PORT
      LAYER metal1 ;
        POLYGON 0.06 0.525 0.185 0.525 0.185 0.7 0.06 0.7  ;
    END
  END I
  PIN ZN
    DIRECTION OUTPUT ;
    ANTENNAPARTIALMETALAREA 0.077 LAYER metal1 ;
    ANTENNAPARTIALMETALSIDEAREA 0.3042 LAYER metal1 ;
    ANTENNADIFFAREA 0.1463 ;
    PORT
      LAYER metal1 ;
        POLYGON 0.25 0.15 0.32 0.15 0.32 1.25 0.25 1.25  ;
    END
  END ZN
  PIN VDD
    DIRECTION INOUT ;
    USE power ;
    SHAPE ABUTMENT ;
    PORT
      LAYER metal1 ;
        POLYGON 0 1.315 0.055 1.315 0.055 0.975 0.125 0.975 0.125 1.315 0.43 1.315 0.43 0.975 0.5 0.975 0.5 1.315 0.57 1.315 0.57 1.485 0 1.485  ;
    END
  END VDD
  PIN VSS
    DIRECTION INOUT ;
    USE ground ;
    SHAPE ABUTMENT ;
    PORT
      LAYER metal1 ;
        POLYGON 0 -0.085 0.57 -0.085 0.57 0.085 0.5 0.085 0.5 0.425 0.43 0.425 0.43 0.085 0.125 0.085 0.125 0.425 0.055 0.425 0.055 0.085 0 0.085  ;
    END
  END VSS
END INV_X2

MACRO INV_X4
  CLASS core ;
  FOREIGN INV_X4 0.0 0.0 ;
  ORIGIN 0 0 ;
  SYMMETRY X Y ;
  SITE FreePDK45_38x28_10R_NP_162NW_34O ;
  SIZE 0.95 BY 1.4 ;
  PIN I
    DIRECTION INPUT ;
    ANTENNAPARTIALMETALAREA 0.01925 LAYER metal1 ;
    ANTENNAPARTIALMETALSIDEAREA 0.0741 LAYER metal1 ;
    ANTENNAGATEAREA 0.209 ;
    PORT
      LAYER metal1 ;
        POLYGON 0.06 0.525 0.17 0.525 0.17 0.7 0.06 0.7  ;
    END
  END I
  PIN ZN
    DIRECTION OUTPUT ;
    ANTENNAPARTIALMETALAREA 0.17005 LAYER metal1 ;
    ANTENNAPARTIALMETALSIDEAREA 0.5434 LAYER metal1 ;
    ANTENNADIFFAREA 0.2926 ;
    PORT
      LAYER metal1 ;
        POLYGON 0.235 0.15 0.305 0.15 0.305 0.56 0.61 0.56 0.61 0.15 0.685 0.15 0.685 1.04 0.615 1.04 0.615 0.7 0.305 0.7 0.305 1.04 0.235 1.04  ;
    END
  END ZN
  PIN VDD
    DIRECTION INOUT ;
    USE power ;
    SHAPE ABUTMENT ;
    PORT
      LAYER metal1 ;
        POLYGON 0 1.315 0.04 1.315 0.04 0.98 0.11 0.98 0.11 1.315 0.415 1.315 0.415 0.98 0.485 0.98 0.485 1.315 0.795 1.315 0.795 0.98 0.865 0.98 0.865 1.315 0.95 1.315 0.95 1.485 0 1.485  ;
    END
  END VDD
  PIN VSS
    DIRECTION INOUT ;
    USE ground ;
    SHAPE ABUTMENT ;
    PORT
      LAYER metal1 ;
        POLYGON 0 -0.085 0.95 -0.085 0.95 0.085 0.865 0.085 0.865 0.425 0.795 0.425 0.795 0.085 0.485 0.085 0.485 0.425 0.415 0.425 0.415 0.085 0.11 0.085 0.11 0.425 0.04 0.425 0.04 0.085 0 0.085  ;
    END
  END VSS
END INV_X4

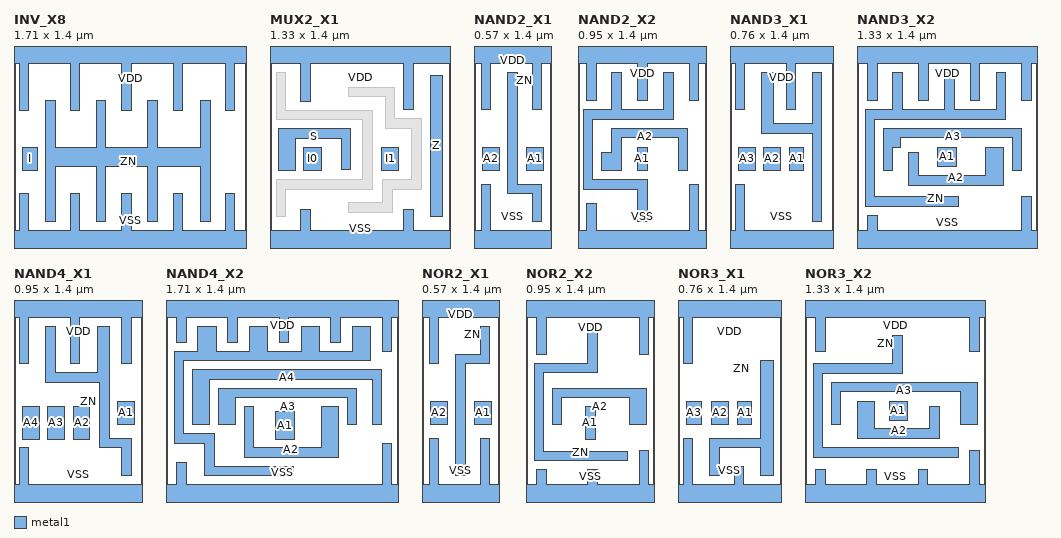
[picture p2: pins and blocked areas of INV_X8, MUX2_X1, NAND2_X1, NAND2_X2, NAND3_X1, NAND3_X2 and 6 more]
MACRO INV_X8
  CLASS core ;
  FOREIGN INV_X8 0.0 0.0 ;
  ORIGIN 0 0 ;
  SYMMETRY X Y ;
  SITE FreePDK45_38x28_10R_NP_162NW_34O ;
  SIZE 1.71 BY 1.4 ;
  PIN I
    DIRECTION INPUT ;
    ANTENNAPARTIALMETALAREA 0.01925 LAYER metal1 ;
    ANTENNAPARTIALMETALSIDEAREA 0.0741 LAYER metal1 ;
    ANTENNAGATEAREA 0.418 ;
    PORT
      LAYER metal1 ;
        POLYGON 0.06 0.525 0.17 0.525 0.17 0.7 0.06 0.7  ;
    END
  END I
  PIN ZN
    DIRECTION OUTPUT ;
    ANTENNAPARTIALMETALAREA 0.3794 LAYER metal1 ;
    ANTENNAPARTIALMETALSIDEAREA 1.131 LAYER metal1 ;
    ANTENNADIFFAREA 0.5852 ;
    PORT
      LAYER metal1 ;
        POLYGON 0.235 0.15 0.305 0.15 0.305 0.56 0.605 0.56 0.605 0.15 0.675 0.15 0.675 0.56 0.985 0.56 0.985 0.15 1.055 0.15 1.055 0.56 1.375 0.56 1.375 0.15 1.445 0.15 1.445 1.04 1.375 1.04 1.375 0.7 1.055 0.7 1.055 1.04 0.985 1.04 0.985 0.7 0.675 0.7 0.675 1.04 0.605 1.04 0.605 0.7 0.305 0.7 0.305 1.04 0.235 1.04  ;
    END
  END ZN
  PIN VDD
    DIRECTION INOUT ;
    USE power ;
    SHAPE ABUTMENT ;
    PORT
      LAYER metal1 ;
        POLYGON 0 1.315 0.04 1.315 0.04 0.97 0.11 0.97 0.11 1.315 0.415 1.315 0.415 0.97 0.485 0.97 0.485 1.315 0.795 1.315 0.795 0.97 0.865 0.97 0.865 1.315 1.175 1.315 1.175 0.97 1.245 0.97 1.245 1.315 1.555 1.315 1.555 0.97 1.625 0.97 1.625 1.315 1.71 1.315 1.71 1.485 0 1.485  ;
    END
  END VDD
  PIN VSS
    DIRECTION INOUT ;
    USE ground ;
    SHAPE ABUTMENT ;
    PORT
      LAYER metal1 ;
        POLYGON 0 -0.085 1.71 -0.085 1.71 0.085 1.625 0.085 1.625 0.36 1.555 0.36 1.555 0.085 1.245 0.085 1.245 0.36 1.175 0.36 1.175 0.085 0.865 0.085 0.865 0.36 0.795 0.36 0.795 0.085 0.485 0.085 0.485 0.36 0.415 0.36 0.415 0.085 0.11 0.085 0.11 0.36 0.04 0.36 0.04 0.085 0 0.085  ;
    END
  END VSS
END INV_X8

MACRO MUX2_X1
  CLASS core ;
  FOREIGN MUX2_X1 0.0 0.0 ;
  ORIGIN 0 0 ;
  SYMMETRY X Y ;
  SITE FreePDK45_38x28_10R_NP_162NW_34O ;
  SIZE 1.33 BY 1.4 ;
  PIN I0
    DIRECTION INPUT ;
    ANTENNAPARTIALMETALAREA 0.02275 LAYER metal1 ;
    ANTENNAPARTIALMETALSIDEAREA 0.0793 LAYER metal1 ;
    ANTENNAGATEAREA 0.02625 ;
    PORT
      LAYER metal1 ;
        POLYGON 0.25 0.525 0.38 0.525 0.38 0.7 0.25 0.7  ;
    END
  END I0
  PIN I1
    DIRECTION INPUT ;
    ANTENNAPARTIALMETALAREA 0.02275 LAYER metal1 ;
    ANTENNAPARTIALMETALSIDEAREA 0.0793 LAYER metal1 ;
    ANTENNAGATEAREA 0.02625 ;
    PORT
      LAYER metal1 ;
        POLYGON 0.82 0.525 0.95 0.525 0.95 0.7 0.82 0.7  ;
    END
  END I1
  PIN S
    DIRECTION INPUT ;
    ANTENNAPARTIALMETALAREA 0.08355 LAYER metal1 ;
    ANTENNAPARTIALMETALSIDEAREA 0.2795 LAYER metal1 ;
    ANTENNAGATEAREA 0.0525 ;
    PORT
      LAYER metal1 ;
        POLYGON 0.06 0.525 0.185 0.525 0.185 0.765 0.525 0.765 0.525 0.535 0.595 0.535 0.595 0.835 0.06 0.835  ;
    END
  END S
  PIN Z
    DIRECTION OUTPUT ;
    ANTENNAPARTIALMETALAREA 0.0936 LAYER metal1 ;
    ANTENNAPARTIALMETALSIDEAREA 0.2938 LAYER metal1 ;
    ANTENNADIFFAREA 0.109725 ;
    PORT
      LAYER metal1 ;
        POLYGON 1.18 0.19 1.27 0.19 1.27 1.23 1.18 1.23  ;
    END
  END Z
  PIN VDD
    DIRECTION INOUT ;
    USE power ;
    SHAPE ABUTMENT ;
    PORT
      LAYER metal1 ;
        POLYGON 0 1.315 0.225 1.315 0.225 1.035 0.295 1.035 0.295 1.315 0.985 1.315 0.985 0.975 1.055 0.975 1.055 1.315 1.115 1.315 1.33 1.315 1.33 1.485 1.115 1.485 0 1.485  ;
    END
  END VDD
  PIN VSS
    DIRECTION INOUT ;
    USE ground ;
    SHAPE ABUTMENT ;
    PORT
      LAYER metal1 ;
        POLYGON 0 -0.085 1.33 -0.085 1.33 0.085 1.055 0.085 1.055 0.24 0.985 0.24 0.985 0.085 0.295 0.085 0.295 0.24 0.225 0.24 0.225 0.085 0 0.085  ;
    END
  END VSS
  OBS
      LAYER metal1 ;
        POLYGON 0.045 0.9 0.685 0.9 0.685 0.46 0.045 0.46 0.045 0.19 0.115 0.19 0.115 0.39 0.755 0.39 0.755 0.97 0.115 0.97 0.115 1.25 0.045 1.25  ;
        POLYGON 0.58 1.07 0.85 1.07 0.85 0.84 1.045 0.84 1.045 0.46 0.83 0.46 0.83 0.29 0.58 0.29 0.58 0.22 0.9 0.22 0.9 0.39 1.115 0.39 1.115 0.91 0.92 0.91 0.92 1.14 0.58 1.14  ;
  END
END MUX2_X1

MACRO NAND2_X1
  CLASS core ;
  FOREIGN NAND2_X1 0.0 0.0 ;
  ORIGIN 0 0 ;
  SYMMETRY X Y ;
  SITE FreePDK45_38x28_10R_NP_162NW_34O ;
  SIZE 0.57 BY 1.4 ;
  PIN A1
    DIRECTION INPUT ;
    ANTENNAPARTIALMETALAREA 0.021875 LAYER metal1 ;
    ANTENNAPARTIALMETALSIDEAREA 0.078 LAYER metal1 ;
    ANTENNAGATEAREA 0.05225 ;
    PORT
      LAYER metal1 ;
        POLYGON 0.385 0.525 0.51 0.525 0.51 0.7 0.385 0.7  ;
    END
  END A1
  PIN A2
    DIRECTION INPUT ;
    ANTENNAPARTIALMETALAREA 0.021875 LAYER metal1 ;
    ANTENNAPARTIALMETALSIDEAREA 0.078 LAYER metal1 ;
    ANTENNAGATEAREA 0.05225 ;
    PORT
      LAYER metal1 ;
        POLYGON 0.06 0.525 0.185 0.525 0.185 0.7 0.06 0.7  ;
    END
  END A2
  PIN ZN
    DIRECTION OUTPUT ;
    ANTENNAPARTIALMETALAREA 0.0896 LAYER metal1 ;
    ANTENNAPARTIALMETALSIDEAREA 0.351 LAYER metal1 ;
    ANTENNADIFFAREA 0.131775 ;
    PORT
      LAYER metal1 ;
        POLYGON 0.25 0.355 0.43 0.355 0.43 0.15 0.5 0.15 0.5 0.425 0.32 0.425 0.32 1.25 0.25 1.25  ;
    END
  END ZN
  PIN VDD
    DIRECTION INOUT ;
    USE power ;
    SHAPE ABUTMENT ;
    PORT
      LAYER metal1 ;
        POLYGON 0 1.315 0.055 1.315 0.055 0.975 0.125 0.975 0.125 1.315 0.43 1.315 0.43 0.975 0.5 0.975 0.5 1.315 0.57 1.315 0.57 1.485 0 1.485  ;
    END
  END VDD
  PIN VSS
    DIRECTION INOUT ;
    USE ground ;
    SHAPE ABUTMENT ;
    PORT
      LAYER metal1 ;
        POLYGON 0 -0.085 0.57 -0.085 0.57 0.085 0.125 0.085 0.125 0.425 0.055 0.425 0.055 0.085 0 0.085  ;
    END
  END VSS
END NAND2_X1

MACRO NAND2_X2
  CLASS core ;
  FOREIGN NAND2_X2 0.0 0.0 ;
  ORIGIN 0 0 ;
  SYMMETRY X Y ;
  SITE FreePDK45_38x28_10R_NP_162NW_34O ;
  SIZE 0.95 BY 1.4 ;
  PIN A1
    DIRECTION INPUT ;
    ANTENNAPARTIALMETALAREA 0.01225 LAYER metal1 ;
    ANTENNAPARTIALMETALSIDEAREA 0.0637 LAYER metal1 ;
    ANTENNAGATEAREA 0.1045 ;
    PORT
      LAYER metal1 ;
        POLYGON 0.44 0.525 0.51 0.525 0.51 0.7 0.44 0.7  ;
    END
  END A1
  PIN A2
    DIRECTION INPUT ;
    ANTENNAPARTIALMETALAREA 0.083625 LAYER metal1 ;
    ANTENNAPARTIALMETALSIDEAREA 0.3107 LAYER metal1 ;
    ANTENNAGATEAREA 0.1045 ;
    PORT
      LAYER metal1 ;
        POLYGON 0.175 0.525 0.32 0.525 0.32 0.77 0.74 0.77 0.74 0.525 0.81 0.525 0.81 0.84 0.25 0.84 0.25 0.66 0.175 0.66  ;
    END
  END A2
  PIN ZN
    DIRECTION OUTPUT ;
    ANTENNAPARTIALMETALAREA 0.16555 LAYER metal1 ;
    ANTENNAPARTIALMETALSIDEAREA 0.6331 LAYER metal1 ;
    ANTENNADIFFAREA 0.2345 ;
    PORT
      LAYER metal1 ;
        POLYGON 0.11 0.905 0.7 0.905 0.7 1.25 0.63 1.25 0.63 0.975 0.32 0.975 0.32 1.25 0.25 1.25 0.25 0.975 0.04 0.975 0.04 0.39 0.44 0.39 0.44 0.15 0.51 0.15 0.51 0.46 0.11 0.46  ;
    END
  END ZN
  PIN VDD
    DIRECTION INOUT ;
    USE power ;
    SHAPE ABUTMENT ;
    PORT
      LAYER metal1 ;
        POLYGON 0 1.315 0.065 1.315 0.065 1.04 0.135 1.04 0.135 1.315 0.44 1.315 0.44 1.04 0.51 1.04 0.51 1.315 0.82 1.315 0.82 1.04 0.89 1.04 0.89 1.315 0.95 1.315 0.95 1.485 0 1.485  ;
    END
  END VDD
  PIN VSS
    DIRECTION INOUT ;
    USE ground ;
    SHAPE ABUTMENT ;
    PORT
      LAYER metal1 ;
        POLYGON 0 -0.085 0.95 -0.085 0.95 0.085 0.89 0.085 0.89 0.425 0.82 0.425 0.82 0.085 0.135 0.085 0.135 0.285 0.065 0.285 0.065 0.085 0 0.085  ;
    END
  END VSS
END NAND2_X2

MACRO NAND3_X1
  CLASS core ;
  FOREIGN NAND3_X1 0.0 0.0 ;
  ORIGIN 0 0 ;
  SYMMETRY X Y ;
  SITE FreePDK45_38x28_10R_NP_162NW_34O ;
  SIZE 0.76 BY 1.4 ;
  PIN A1
    DIRECTION INPUT ;
    ANTENNAPARTIALMETALAREA 0.0175 LAYER metal1 ;
    ANTENNAPARTIALMETALSIDEAREA 0.0715 LAYER metal1 ;
    ANTENNAGATEAREA 0.05225 ;
    PORT
      LAYER metal1 ;
        POLYGON 0.44 0.525 0.54 0.525 0.54 0.7 0.44 0.7  ;
    END
  END A1
  PIN A2
    DIRECTION INPUT ;
    ANTENNAPARTIALMETALAREA 0.021875 LAYER metal1 ;
    ANTENNAPARTIALMETALSIDEAREA 0.078 LAYER metal1 ;
    ANTENNAGATEAREA 0.05225 ;
    PORT
      LAYER metal1 ;
        POLYGON 0.25 0.525 0.375 0.525 0.375 0.7 0.25 0.7  ;
    END
  END A2
  PIN A3
    DIRECTION INPUT ;
    ANTENNAPARTIALMETALAREA 0.021875 LAYER metal1 ;
    ANTENNAPARTIALMETALSIDEAREA 0.078 LAYER metal1 ;
    ANTENNAGATEAREA 0.05225 ;
    PORT
      LAYER metal1 ;
        POLYGON 0.06 0.525 0.185 0.525 0.185 0.7 0.06 0.7  ;
    END
  END A3
  PIN ZN
    DIRECTION OUTPUT ;
    ANTENNAPARTIALMETALAREA 0.1352 LAYER metal1 ;
    ANTENNAPARTIALMETALSIDEAREA 0.4992 LAYER metal1 ;
    ANTENNADIFFAREA 0.197925 ;
    PORT
      LAYER metal1 ;
        POLYGON 0.235 0.8 0.605 0.8 0.605 0.15 0.675 0.15 0.675 1.25 0.605 1.25 0.605 0.87 0.32 0.87 0.32 1.25 0.235 1.25  ;
    END
  END ZN
  PIN VDD
    DIRECTION INOUT ;
    USE power ;
    SHAPE ABUTMENT ;
    PORT
      LAYER metal1 ;
        POLYGON 0 1.315 0.04 1.315 0.04 0.975 0.11 0.975 0.11 1.315 0.415 1.315 0.415 0.975 0.485 0.975 0.485 1.315 0.76 1.315 0.76 1.485 0 1.485  ;
    END
  END VDD
  PIN VSS
    DIRECTION INOUT ;
    USE ground ;
    SHAPE ABUTMENT ;
    PORT
      LAYER metal1 ;
        POLYGON 0 -0.085 0.76 -0.085 0.76 0.085 0.11 0.085 0.11 0.425 0.04 0.425 0.04 0.085 0 0.085  ;
    END
  END VSS
END NAND3_X1

MACRO NAND3_X2
  CLASS core ;
  FOREIGN NAND3_X2 0.0 0.0 ;
  ORIGIN 0 0 ;
  SYMMETRY X Y ;
  SITE FreePDK45_38x28_10R_NP_162NW_34O ;
  SIZE 1.33 BY 1.4 ;
  PIN A1
    DIRECTION INPUT ;
    ANTENNAPARTIALMETALAREA 0.0189 LAYER metal1 ;
    ANTENNAPARTIALMETALSIDEAREA 0.0715 LAYER metal1 ;
    ANTENNAGATEAREA 0.1045 ;
    PORT
      LAYER metal1 ;
        POLYGON 0.595 0.56 0.73 0.56 0.73 0.7 0.595 0.7  ;
    END
  END A1
  PIN A2
    DIRECTION INPUT ;
    ANTENNAPARTIALMETALAREA 0.0882 LAYER metal1 ;
    ANTENNAPARTIALMETALSIDEAREA 0.299 LAYER metal1 ;
    ANTENNAGATEAREA 0.1045 ;
    PORT
      LAYER metal1 ;
        POLYGON 0.38 0.42 1.08 0.42 1.08 0.7 0.95 0.7 0.95 0.49 0.45 0.49 0.45 0.66 0.38 0.66  ;
    END
  END A2
  PIN A3
    DIRECTION INPUT ;
    ANTENNAPARTIALMETALAREA 0.10955 LAYER metal1 ;
    ANTENNAPARTIALMETALSIDEAREA 0.4108 LAYER metal1 ;
    ANTENNAGATEAREA 0.1045 ;
    PORT
      LAYER metal1 ;
        POLYGON 0.195 0.525 0.265 0.525 0.265 0.7 0.32 0.7 0.32 0.77 1.145 0.77 1.145 0.525 1.215 0.525 1.215 0.84 0.195 0.84  ;
    END
  END A3
  PIN ZN
    DIRECTION OUTPUT ;
    ANTENNAPARTIALMETALAREA 0.2184 LAYER metal1 ;
    ANTENNAPARTIALMETALSIDEAREA 0.8294 LAYER metal1 ;
    ANTENNADIFFAREA 0.3227 ;
    PORT
      LAYER metal1 ;
        POLYGON 0.13 0.905 1.095 0.905 1.095 1.25 1.025 1.25 1.025 0.975 0.715 0.975 0.715 1.25 0.645 1.25 0.645 0.975 0.335 0.975 0.335 1.25 0.265 1.25 0.265 0.975 0.06 0.975 0.06 0.265 0.75 0.265 0.75 0.335 0.13 0.335  ;
    END
  END ZN
  PIN VDD
    DIRECTION INOUT ;
    USE power ;
    SHAPE ABUTMENT ;
    PORT
      LAYER metal1 ;
        POLYGON 0 1.315 0.08 1.315 0.08 1.04 0.15 1.04 0.15 1.315 0.455 1.315 0.455 1.04 0.525 1.04 0.525 1.315 0.835 1.315 0.835 1.04 0.905 1.04 0.905 1.315 1.215 1.315 1.215 1.04 1.285 1.04 1.285 1.315 1.33 1.315 1.33 1.485 0 1.485  ;
    END
  END VDD
  PIN VSS
    DIRECTION INOUT ;
    USE ground ;
    SHAPE ABUTMENT ;
    PORT
      LAYER metal1 ;
        POLYGON 0 -0.085 1.33 -0.085 1.33 0.085 1.285 0.085 1.285 0.335 1.215 0.335 1.215 0.085 0.15 0.085 0.15 0.195 0.08 0.195 0.08 0.085 0 0.085  ;
    END
  END VSS
END NAND3_X2

MACRO NAND4_X1
  CLASS core ;
  FOREIGN NAND4_X1 0.0 0.0 ;
  ORIGIN 0 0 ;
  SYMMETRY X Y ;
  SITE FreePDK45_38x28_10R_NP_162NW_34O ;
  SIZE 0.95 BY 1.4 ;
  PIN A1
    DIRECTION INPUT ;
    ANTENNAPARTIALMETALAREA 0.021875 LAYER metal1 ;
    ANTENNAPARTIALMETALSIDEAREA 0.078 LAYER metal1 ;
    ANTENNAGATEAREA 0.05225 ;
    PORT
      LAYER metal1 ;
        POLYGON 0.765 0.525 0.89 0.525 0.89 0.7 0.765 0.7  ;
    END
  END A1
  PIN A2
    DIRECTION INPUT ;
    ANTENNAPARTIALMETALAREA 0.0276 LAYER metal1 ;
    ANTENNAPARTIALMETALSIDEAREA 0.0923 LAYER metal1 ;
    ANTENNAGATEAREA 0.05225 ;
    PORT
      LAYER metal1 ;
        POLYGON 0.44 0.42 0.555 0.42 0.555 0.66 0.44 0.66  ;
    END
  END A2
  PIN A3
    DIRECTION INPUT ;
    ANTENNAPARTIALMETALAREA 0.03 LAYER metal1 ;
    ANTENNAPARTIALMETALSIDEAREA 0.0949 LAYER metal1 ;
    ANTENNAGATEAREA 0.05225 ;
    PORT
      LAYER metal1 ;
        POLYGON 0.25 0.42 0.375 0.42 0.375 0.66 0.25 0.66  ;
    END
  END A3
  PIN A4
    DIRECTION INPUT ;
    ANTENNAPARTIALMETALAREA 0.03 LAYER metal1 ;
    ANTENNAPARTIALMETALSIDEAREA 0.0949 LAYER metal1 ;
    ANTENNAGATEAREA 0.05225 ;
    PORT
      LAYER metal1 ;
        POLYGON 0.06 0.42 0.185 0.42 0.185 0.66 0.06 0.66  ;
    END
  END A4
  PIN ZN
    DIRECTION OUTPUT ;
    ANTENNAPARTIALMETALAREA 0.1451 LAYER metal1 ;
    ANTENNAPARTIALMETALSIDEAREA 0.5382 LAYER metal1 ;
    ANTENNADIFFAREA 0.219975 ;
    PORT
      LAYER metal1 ;
        POLYGON 0.235 0.84 0.63 0.84 0.63 0.355 0.795 0.355 0.795 0.15 0.865 0.15 0.865 0.425 0.7 0.425 0.7 1.25 0.615 1.25 0.615 0.91 0.305 0.91 0.305 1.25 0.235 1.25  ;
    END
  END ZN
  PIN VDD
    DIRECTION INOUT ;
    USE power ;
    SHAPE ABUTMENT ;
    PORT
      LAYER metal1 ;
        POLYGON 0 1.315 0.04 1.315 0.04 0.975 0.11 0.975 0.11 1.315 0.415 1.315 0.415 0.975 0.485 0.975 0.485 1.315 0.795 1.315 0.795 0.975 0.865 0.975 0.865 1.315 0.95 1.315 0.95 1.485 0 1.485  ;
    END
  END VDD
  PIN VSS
    DIRECTION INOUT ;
    USE ground ;
    SHAPE ABUTMENT ;
    PORT
      LAYER metal1 ;
        POLYGON 0 -0.085 0.95 -0.085 0.95 0.085 0.11 0.085 0.11 0.355 0.04 0.355 0.04 0.085 0 0.085  ;
    END
  END VSS
END NAND4_X1

MACRO NAND4_X2
  CLASS core ;
  FOREIGN NAND4_X2 0.0 0.0 ;
  ORIGIN 0 0 ;
  SYMMETRY X Y ;
  SITE FreePDK45_38x28_10R_NP_162NW_34O ;
  SIZE 1.71 BY 1.4 ;
  PIN A1
    DIRECTION INPUT ;
    ANTENNAPARTIALMETALAREA 0.027675 LAYER metal1 ;
    ANTENNAPARTIALMETALSIDEAREA 0.0884 LAYER metal1 ;
    ANTENNAGATEAREA 0.1045 ;
    PORT
      LAYER metal1 ;
        POLYGON 0.81 0.42 0.945 0.42 0.945 0.625 0.81 0.625  ;
    END
  END A1
  PIN A2
    DIRECTION INPUT ;
    ANTENNAPARTIALMETALAREA 0.108125 LAYER metal1 ;
    ANTENNAPARTIALMETALSIDEAREA 0.3575 LAYER metal1 ;
    ANTENNAGATEAREA 0.1045 ;
    PORT
      LAYER metal1 ;
        POLYGON 0.575 0.285 1.27 0.285 1.27 0.66 1.145 0.66 1.145 0.355 0.645 0.355 0.645 0.66 0.575 0.66  ;
    END
  END A2
  PIN A3
    DIRECTION INPUT ;
    ANTENNAPARTIALMETALAREA 0.10905 LAYER metal1 ;
    ANTENNAPARTIALMETALSIDEAREA 0.3861 LAYER metal1 ;
    ANTENNAGATEAREA 0.1045 ;
    PORT
      LAYER metal1 ;
        POLYGON 0.39 0.525 0.51 0.525 0.51 0.725 1.335 0.725 1.335 0.525 1.405 0.525 1.405 0.795 0.39 0.795  ;
    END
  END A3
  PIN A4
    DIRECTION INPUT ;
    ANTENNAPARTIALMETALAREA 0.162975 LAYER metal1 ;
    ANTENNAPARTIALMETALSIDEAREA 0.5551 LAYER metal1 ;
    ANTENNAGATEAREA 0.1045 ;
    PORT
      LAYER metal1 ;
        POLYGON 0.195 0.525 0.32 0.525 0.32 0.86 1.52 0.86 1.52 0.525 1.59 0.525 1.59 0.93 0.195 0.93  ;
    END
  END A4
  PIN ZN
    DIRECTION OUTPUT ;
    ANTENNAPARTIALMETALAREA 0.31725 LAYER metal1 ;
    ANTENNAPARTIALMETALSIDEAREA 1.0179 LAYER metal1 ;
    ANTENNADIFFAREA 0.4109 ;
    PORT
      LAYER metal1 ;
        POLYGON 0.13 0.995 1.51 0.995 1.51 1.25 1.375 1.25 1.375 1.065 1.13 1.065 1.13 1.25 0.995 1.25 0.995 1.065 0.75 1.065 0.75 1.25 0.615 1.25 0.615 1.065 0.37 1.065 0.37 1.25 0.235 1.25 0.235 1.065 0.06 1.065 0.06 0.39 0.285 0.39 0.285 0.15 0.94 0.15 0.94 0.22 0.355 0.22 0.355 0.46 0.13 0.46  ;
    END
  END ZN
  PIN VDD
    DIRECTION INOUT ;
    USE power ;
    SHAPE ABUTMENT ;
    PORT
      LAYER metal1 ;
        POLYGON 0 1.315 0.08 1.315 0.08 1.13 0.15 1.13 0.15 1.315 0.455 1.315 0.455 1.13 0.525 1.13 0.525 1.315 0.835 1.315 0.835 1.13 0.905 1.13 0.905 1.315 1.215 1.315 1.215 1.13 1.285 1.13 1.285 1.315 1.595 1.315 1.595 1.065 1.665 1.065 1.665 1.315 1.71 1.315 1.71 1.485 0 1.485  ;
    END
  END VDD
  PIN VSS
    DIRECTION INOUT ;
    USE ground ;
    SHAPE ABUTMENT ;
    PORT
      LAYER metal1 ;
        POLYGON 0 -0.085 1.71 -0.085 1.71 0.085 1.665 0.085 1.665 0.39 1.595 0.39 1.595 0.085 0.15 0.085 0.15 0.25 0.08 0.25 0.08 0.085 0 0.085  ;
    END
  END VSS
END NAND4_X2

MACRO NOR2_X1
  CLASS core ;
  FOREIGN NOR2_X1 0.0 0.0 ;
  ORIGIN 0 0 ;
  SYMMETRY X Y ;
  SITE FreePDK45_38x28_10R_NP_162NW_34O ;
  SIZE 0.57 BY 1.4 ;
  PIN A1
    DIRECTION INPUT ;
    ANTENNAPARTIALMETALAREA 0.021875 LAYER metal1 ;
    ANTENNAPARTIALMETALSIDEAREA 0.078 LAYER metal1 ;
    ANTENNAGATEAREA 0.05225 ;
    PORT
      LAYER metal1 ;
        POLYGON 0.385 0.525 0.51 0.525 0.51 0.7 0.385 0.7  ;
    END
  END A1
  PIN A2
    DIRECTION INPUT ;
    ANTENNAPARTIALMETALAREA 0.021875 LAYER metal1 ;
    ANTENNAPARTIALMETALSIDEAREA 0.078 LAYER metal1 ;
    ANTENNAGATEAREA 0.05225 ;
    PORT
      LAYER metal1 ;
        POLYGON 0.06 0.525 0.185 0.525 0.185 0.7 0.06 0.7  ;
    END
  END A2
  PIN ZN
    DIRECTION OUTPUT ;
    ANTENNAPARTIALMETALAREA 0.0896 LAYER metal1 ;
    ANTENNAPARTIALMETALSIDEAREA 0.351 LAYER metal1 ;
    ANTENNADIFFAREA 0.12425 ;
    PORT
      LAYER metal1 ;
        POLYGON 0.25 0.15 0.32 0.15 0.32 0.975 0.5 0.975 0.5 1.25 0.43 1.25 0.43 1.045 0.25 1.045  ;
    END
  END ZN
  PIN VDD
    DIRECTION INOUT ;
    USE power ;
    SHAPE ABUTMENT ;
    PORT
      LAYER metal1 ;
        POLYGON 0 1.315 0.055 1.315 0.055 0.975 0.125 0.975 0.125 1.315 0.57 1.315 0.57 1.485 0 1.485  ;
    END
  END VDD
  PIN VSS
    DIRECTION INOUT ;
    USE ground ;
    SHAPE ABUTMENT ;
    PORT
      LAYER metal1 ;
        POLYGON 0 -0.085 0.57 -0.085 0.57 0.085 0.5 0.085 0.5 0.425 0.43 0.425 0.43 0.085 0.125 0.085 0.125 0.425 0.055 0.425 0.055 0.085 0 0.085  ;
    END
  END VSS
END NOR2_X1

MACRO NOR2_X2
  CLASS core ;
  FOREIGN NOR2_X2 0.0 0.0 ;
  ORIGIN 0 0 ;
  SYMMETRY X Y ;
  SITE FreePDK45_38x28_10R_NP_162NW_34O ;
  SIZE 0.95 BY 1.4 ;
  PIN A1
    DIRECTION INPUT ;
    ANTENNAPARTIALMETALAREA 0.0168 LAYER metal1 ;
    ANTENNAPARTIALMETALSIDEAREA 0.0806 LAYER metal1 ;
    ANTENNAGATEAREA 0.1045 ;
    PORT
      LAYER metal1 ;
        POLYGON 0.44 0.42 0.51 0.42 0.51 0.66 0.44 0.66  ;
    END
  END A1
  PIN A2
    DIRECTION INPUT ;
    ANTENNAPARTIALMETALAREA 0.08865 LAYER metal1 ;
    ANTENNAPARTIALMETALSIDEAREA 0.3029 LAYER metal1 ;
    ANTENNAGATEAREA 0.1045 ;
    PORT
      LAYER metal1 ;
        POLYGON 0.195 0.525 0.265 0.525 0.265 0.725 0.76 0.725 0.76 0.525 0.89 0.525 0.89 0.795 0.195 0.795  ;
    END
  END A2
  PIN ZN
    DIRECTION OUTPUT ;
    ANTENNAPARTIALMETALAREA 0.14035 LAYER metal1 ;
    ANTENNAPARTIALMETALSIDEAREA 0.5395 LAYER metal1 ;
    ANTENNADIFFAREA 0.2044 ;
    PORT
      LAYER metal1 ;
        POLYGON 0.06 0.26 0.75 0.26 0.75 0.33 0.13 0.33 0.13 0.91 0.525 0.91 0.525 1.25 0.455 1.25 0.455 0.98 0.06 0.98  ;
    END
  END ZN
  PIN VDD
    DIRECTION INOUT ;
    USE power ;
    SHAPE ABUTMENT ;
    PORT
      LAYER metal1 ;
        POLYGON 0 1.315 0.08 1.315 0.08 1.045 0.15 1.045 0.15 1.315 0.835 1.315 0.835 1.045 0.905 1.045 0.905 1.315 0.95 1.315 0.95 1.485 0 1.485  ;
    END
  END VDD
  PIN VSS
    DIRECTION INOUT ;
    USE ground ;
    SHAPE ABUTMENT ;
    PORT
      LAYER metal1 ;
        POLYGON 0 -0.085 0.95 -0.085 0.95 0.085 0.905 0.085 0.905 0.335 0.835 0.335 0.835 0.085 0.525 0.085 0.525 0.195 0.455 0.195 0.455 0.085 0.15 0.085 0.15 0.195 0.08 0.195 0.08 0.085 0 0.085  ;
    END
  END VSS
END NOR2_X2

MACRO NOR3_X1
  CLASS core ;
  FOREIGN NOR3_X1 0.0 0.0 ;
  ORIGIN 0 0 ;
  SYMMETRY X Y ;
  SITE FreePDK45_38x28_10R_NP_162NW_34O ;
  SIZE 0.76 BY 1.4 ;
  PIN A1
    DIRECTION INPUT ;
    ANTENNAPARTIALMETALAREA 0.018375 LAYER metal1 ;
    ANTENNAPARTIALMETALSIDEAREA 0.0728 LAYER metal1 ;
    ANTENNAGATEAREA 0.05225 ;
    PORT
      LAYER metal1 ;
        POLYGON 0.44 0.525 0.545 0.525 0.545 0.7 0.44 0.7  ;
    END
  END A1
  PIN A2
    DIRECTION INPUT ;
    ANTENNAPARTIALMETALAREA 0.021875 LAYER metal1 ;
    ANTENNAPARTIALMETALSIDEAREA 0.078 LAYER metal1 ;
    ANTENNAGATEAREA 0.05225 ;
    PORT
      LAYER metal1 ;
        POLYGON 0.25 0.525 0.375 0.525 0.375 0.7 0.25 0.7  ;
    END
  END A2
  PIN A3
    DIRECTION INPUT ;
    ANTENNAPARTIALMETALAREA 0.020125 LAYER metal1 ;
    ANTENNAPARTIALMETALSIDEAREA 0.0754 LAYER metal1 ;
    ANTENNAGATEAREA 0.05225 ;
    PORT
      LAYER metal1 ;
        POLYGON 0.06 0.525 0.175 0.525 0.175 0.7 0.06 0.7  ;
    END
  END A3
  PIN ZN
    DIRECTION OUTPUT ;
    ANTENNAPARTIALMETALAREA 0.1171 LAYER metal1 ;
    ANTENNAPARTIALMETALSIDEAREA 0.3952 LAYER metal1 ;
    ANTENNADIFFAREA 0.167825 ;
    PORT
      LAYER metal1 ;
        POLYGON 0.235 0.15 0.305 0.15 0.305 0.355 0.61 0.355 0.61 0.15 0.7 0.15 0.7 1 0.61 1 0.61 0.425 0.235 0.425  ;
    END
  END ZN
  PIN VDD
    DIRECTION INOUT ;
    USE power ;
    SHAPE ABUTMENT ;
    PORT
      LAYER metal1 ;
        POLYGON 0 1.315 0.04 1.315 0.04 0.975 0.11 0.975 0.11 1.315 0.76 1.315 0.76 1.485 0 1.485  ;
    END
  END VDD
  PIN VSS
    DIRECTION INOUT ;
    USE ground ;
    SHAPE ABUTMENT ;
    PORT
      LAYER metal1 ;
        POLYGON 0 -0.085 0.76 -0.085 0.76 0.085 0.485 0.085 0.485 0.22 0.415 0.22 0.415 0.085 0.11 0.085 0.11 0.425 0.04 0.425 0.04 0.085 0 0.085  ;
    END
  END VSS
END NOR3_X1

MACRO NOR3_X2
  CLASS core ;
  FOREIGN NOR3_X2 0.0 0.0 ;
  ORIGIN 0 0 ;
  SYMMETRY X Y ;
  SITE FreePDK45_38x28_10R_NP_162NW_34O ;
  SIZE 1.33 BY 1.4 ;
  PIN A1
    DIRECTION INPUT ;
    ANTENNAPARTIALMETALAREA 0.0189 LAYER metal1 ;
    ANTENNAPARTIALMETALSIDEAREA 0.0715 LAYER metal1 ;
    ANTENNAGATEAREA 0.1045 ;
    PORT
      LAYER metal1 ;
        POLYGON 0.62 0.56 0.755 0.56 0.755 0.7 0.62 0.7  ;
    END
  END A1
  PIN A2
    DIRECTION INPUT ;
    ANTENNAPARTIALMETALAREA 0.07815 LAYER metal1 ;
    ANTENNAPARTIALMETALSIDEAREA 0.2704 LAYER metal1 ;
    ANTENNAGATEAREA 0.1045 ;
    PORT
      LAYER metal1 ;
        POLYGON 0.39 0.425 0.99 0.425 0.99 0.66 0.92 0.66 0.92 0.495 0.51 0.495 0.51 0.7 0.39 0.7  ;
    END
  END A2
  PIN A3
    DIRECTION INPUT ;
    ANTENNAPARTIALMETALAREA 0.123025 LAYER metal1 ;
    ANTENNAPARTIALMETALSIDEAREA 0.4251 LAYER metal1 ;
    ANTENNAGATEAREA 0.1045 ;
    PORT
      LAYER metal1 ;
        POLYGON 0.195 0.525 0.265 0.525 0.265 0.77 1.145 0.77 1.145 0.525 1.27 0.525 1.27 0.84 0.195 0.84  ;
    END
  END A3
  PIN ZN
    DIRECTION OUTPUT ;
    ANTENNAPARTIALMETALAREA 0.1736 LAYER metal1 ;
    ANTENNAPARTIALMETALSIDEAREA 0.663 LAYER metal1 ;
    ANTENNADIFFAREA 0.2625 ;
    PORT
      LAYER metal1 ;
        POLYGON 0.06 0.285 1.13 0.285 1.13 0.355 0.13 0.355 0.13 0.905 0.715 0.905 0.715 1.18 0.645 1.18 0.645 0.975 0.06 0.975  ;
    END
  END ZN
  PIN VDD
    DIRECTION INOUT ;
    USE power ;
    SHAPE ABUTMENT ;
    PORT
      LAYER metal1 ;
        POLYGON 0 1.315 0.08 1.315 0.08 1.065 0.15 1.065 0.15 1.315 1.215 1.315 1.215 1.065 1.285 1.065 1.285 1.315 1.33 1.315 1.33 1.485 0 1.485  ;
    END
  END VDD
  PIN VSS
    DIRECTION INOUT ;
    USE ground ;
    SHAPE ABUTMENT ;
    PORT
      LAYER metal1 ;
        POLYGON 0 -0.085 1.33 -0.085 1.33 0.085 1.285 0.085 1.285 0.335 1.215 0.335 1.215 0.085 0.905 0.085 0.905 0.195 0.835 0.195 0.835 0.085 0.525 0.085 0.525 0.195 0.455 0.195 0.455 0.085 0.15 0.085 0.15 0.195 0.08 0.195 0.08 0.085 0 0.085  ;
    END
  END VSS
END NOR3_X2

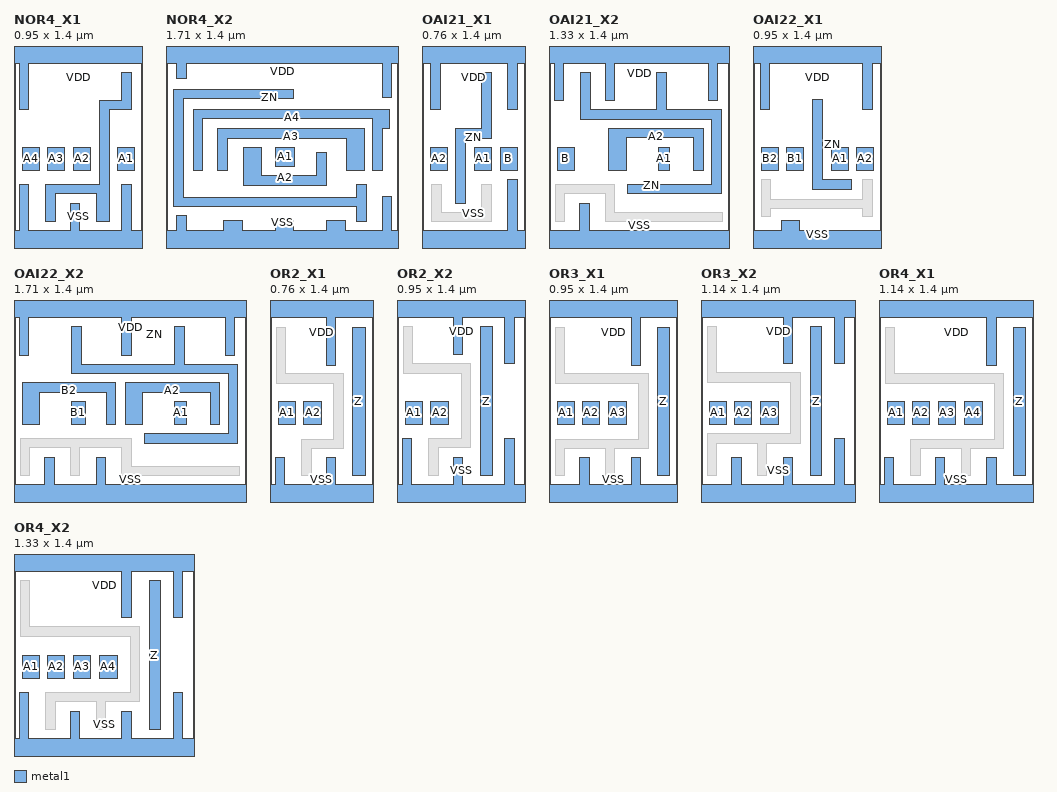
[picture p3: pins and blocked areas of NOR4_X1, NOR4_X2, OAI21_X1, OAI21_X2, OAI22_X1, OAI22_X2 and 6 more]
MACRO NOR4_X1
  CLASS core ;
  FOREIGN NOR4_X1 0.0 0.0 ;
  ORIGIN 0 0 ;
  SYMMETRY X Y ;
  SITE FreePDK45_38x28_10R_NP_162NW_34O ;
  SIZE 0.95 BY 1.4 ;
  PIN A1
    DIRECTION INPUT ;
    ANTENNAPARTIALMETALAREA 0.021875 LAYER metal1 ;
    ANTENNAPARTIALMETALSIDEAREA 0.078 LAYER metal1 ;
    ANTENNAGATEAREA 0.05225 ;
    PORT
      LAYER metal1 ;
        POLYGON 0.765 0.525 0.89 0.525 0.89 0.7 0.765 0.7  ;
    END
  END A1
  PIN A2
    DIRECTION INPUT ;
    ANTENNAPARTIALMETALAREA 0.021875 LAYER metal1 ;
    ANTENNAPARTIALMETALSIDEAREA 0.078 LAYER metal1 ;
    ANTENNAGATEAREA 0.05225 ;
    PORT
      LAYER metal1 ;
        POLYGON 0.44 0.525 0.565 0.525 0.565 0.7 0.44 0.7  ;
    END
  END A2
  PIN A3
    DIRECTION INPUT ;
    ANTENNAPARTIALMETALAREA 0.021875 LAYER metal1 ;
    ANTENNAPARTIALMETALSIDEAREA 0.078 LAYER metal1 ;
    ANTENNAGATEAREA 0.05225 ;
    PORT
      LAYER metal1 ;
        POLYGON 0.25 0.525 0.375 0.525 0.375 0.7 0.25 0.7  ;
    END
  END A3
  PIN A4
    DIRECTION INPUT ;
    ANTENNAPARTIALMETALAREA 0.021875 LAYER metal1 ;
    ANTENNAPARTIALMETALSIDEAREA 0.078 LAYER metal1 ;
    ANTENNAGATEAREA 0.05225 ;
    PORT
      LAYER metal1 ;
        POLYGON 0.06 0.525 0.185 0.525 0.185 0.7 0.06 0.7  ;
    END
  END A4
  PIN ZN
    DIRECTION OUTPUT ;
    ANTENNAPARTIALMETALAREA 0.13465 LAYER metal1 ;
    ANTENNAPARTIALMETALSIDEAREA 0.5031 LAYER metal1 ;
    ANTENNADIFFAREA 0.18235 ;
    PORT
      LAYER metal1 ;
        POLYGON 0.235 0.15 0.305 0.15 0.305 0.355 0.61 0.355 0.61 0.15 0.7 0.15 0.7 0.975 0.865 0.975 0.865 1.25 0.795 1.25 0.795 1.045 0.63 1.045 0.63 0.425 0.235 0.425  ;
    END
  END ZN
  PIN VDD
    DIRECTION INOUT ;
    USE power ;
    SHAPE ABUTMENT ;
    PORT
      LAYER metal1 ;
        POLYGON 0 1.315 0.04 1.315 0.04 0.975 0.11 0.975 0.11 1.315 0.95 1.315 0.95 1.485 0 1.485  ;
    END
  END VDD
  PIN VSS
    DIRECTION INOUT ;
    USE ground ;
    SHAPE ABUTMENT ;
    PORT
      LAYER metal1 ;
        POLYGON 0 -0.085 0.95 -0.085 0.95 0.085 0.865 0.085 0.865 0.425 0.795 0.425 0.795 0.085 0.485 0.085 0.485 0.285 0.415 0.285 0.415 0.085 0.11 0.085 0.11 0.425 0.04 0.425 0.04 0.085 0 0.085  ;
    END
  END VSS
END NOR4_X1

MACRO NOR4_X2
  CLASS core ;
  FOREIGN NOR4_X2 0.0 0.0 ;
  ORIGIN 0 0 ;
  SYMMETRY X Y ;
  SITE FreePDK45_38x28_10R_NP_162NW_34O ;
  SIZE 1.71 BY 1.4 ;
  PIN A1
    DIRECTION INPUT ;
    ANTENNAPARTIALMETALAREA 0.0189 LAYER metal1 ;
    ANTENNAPARTIALMETALSIDEAREA 0.0715 LAYER metal1 ;
    ANTENNAGATEAREA 0.1045 ;
    PORT
      LAYER metal1 ;
        POLYGON 0.81 0.56 0.945 0.56 0.945 0.7 0.81 0.7  ;
    END
  END A1
  PIN A2
    DIRECTION INPUT ;
    ANTENNAPARTIALMETALAREA 0.0819 LAYER metal1 ;
    ANTENNAPARTIALMETALSIDEAREA 0.2756 LAYER metal1 ;
    ANTENNAGATEAREA 0.1045 ;
    PORT
      LAYER metal1 ;
        POLYGON 0.57 0.42 1.18 0.42 1.18 0.66 1.11 0.66 1.11 0.49 0.7 0.49 0.7 0.7 0.57 0.7  ;
    END
  END A2
  PIN A3
    DIRECTION INPUT ;
    ANTENNAPARTIALMETALAREA 0.1236 LAYER metal1 ;
    ANTENNAPARTIALMETALSIDEAREA 0.4238 LAYER metal1 ;
    ANTENNAGATEAREA 0.1045 ;
    PORT
      LAYER metal1 ;
        POLYGON 0.38 0.525 0.45 0.525 0.45 0.765 1.33 0.765 1.33 0.525 1.46 0.525 1.46 0.835 0.38 0.835  ;
    END
  END A3
  PIN A4
    DIRECTION INPUT ;
    ANTENNAPARTIALMETALAREA 0.15925 LAYER metal1 ;
    ANTENNAPARTIALMETALSIDEAREA 0.5954 LAYER metal1 ;
    ANTENNAGATEAREA 0.1045 ;
    PORT
      LAYER metal1 ;
        POLYGON 0.2 0.525 0.27 0.525 0.27 0.91 1.525 0.91 1.525 0.525 1.595 0.525 1.595 0.84 1.65 0.84 1.65 0.98 0.2 0.98  ;
    END
  END A4
  PIN ZN
    DIRECTION OUTPUT ;
    ANTENNAPARTIALMETALAREA 0.230075 LAYER metal1 ;
    ANTENNAPARTIALMETALSIDEAREA 0.858 LAYER metal1 ;
    ANTENNADIFFAREA 0.3206 ;
    PORT
      LAYER metal1 ;
        POLYGON 0.055 0.26 1.405 0.26 1.405 0.15 1.475 0.15 1.475 0.425 1.405 0.425 1.405 0.33 0.13 0.33 0.13 1.055 0.94 1.055 0.94 1.125 0.055 1.125  ;
    END
  END ZN
  PIN VDD
    DIRECTION INOUT ;
    USE power ;
    SHAPE ABUTMENT ;
    PORT
      LAYER metal1 ;
        POLYGON 0 1.315 0.08 1.315 0.08 1.205 0.15 1.205 0.15 1.315 1.595 1.315 1.595 1.065 1.665 1.065 1.665 1.315 1.71 1.315 1.71 1.485 0 1.485  ;
    END
  END VDD
  PIN VSS
    DIRECTION INOUT ;
    USE ground ;
    SHAPE ABUTMENT ;
    PORT
      LAYER metal1 ;
        POLYGON 0 -0.085 1.71 -0.085 1.71 0.085 1.665 0.085 1.665 0.335 1.595 0.335 1.595 0.085 1.32 0.085 1.32 0.16 1.185 0.16 1.185 0.085 0.94 0.085 0.94 0.16 0.805 0.16 0.805 0.085 0.56 0.085 0.56 0.16 0.425 0.16 0.425 0.085 0.15 0.085 0.15 0.195 0.08 0.195 0.08 0.085 0 0.085  ;
    END
  END VSS
END NOR4_X2

MACRO OAI21_X1
  CLASS core ;
  FOREIGN OAI21_X1 0.0 0.0 ;
  ORIGIN 0 0 ;
  SYMMETRY X Y ;
  SITE FreePDK45_38x28_10R_NP_162NW_34O ;
  SIZE 0.76 BY 1.4 ;
  PIN B
    DIRECTION INPUT ;
    ANTENNAPARTIALMETALAREA 0.021875 LAYER metal1 ;
    ANTENNAPARTIALMETALSIDEAREA 0.078 LAYER metal1 ;
    ANTENNAGATEAREA 0.05225 ;
    PORT
      LAYER metal1 ;
        POLYGON 0.575 0.525 0.7 0.525 0.7 0.7 0.575 0.7  ;
    END
  END B
  PIN A1
    DIRECTION INPUT ;
    ANTENNAPARTIALMETALAREA 0.021875 LAYER metal1 ;
    ANTENNAPARTIALMETALSIDEAREA 0.078 LAYER metal1 ;
    ANTENNAGATEAREA 0.05225 ;
    PORT
      LAYER metal1 ;
        POLYGON 0.385 0.525 0.51 0.525 0.51 0.7 0.385 0.7  ;
    END
  END A1
  PIN A2
    DIRECTION INPUT ;
    ANTENNAPARTIALMETALAREA 0.021875 LAYER metal1 ;
    ANTENNAPARTIALMETALSIDEAREA 0.078 LAYER metal1 ;
    ANTENNAGATEAREA 0.05225 ;
    PORT
      LAYER metal1 ;
        POLYGON 0.06 0.525 0.185 0.525 0.185 0.7 0.06 0.7  ;
    END
  END A2
  PIN ZN
    DIRECTION OUTPUT ;
    ANTENNAPARTIALMETALAREA 0.08085 LAYER metal1 ;
    ANTENNAPARTIALMETALSIDEAREA 0.3185 LAYER metal1 ;
    ANTENNADIFFAREA 0.1463 ;
    PORT
      LAYER metal1 ;
        POLYGON 0.25 0.285 0.32 0.285 0.32 0.765 0.51 0.765 0.51 1.25 0.44 1.25 0.44 0.835 0.25 0.835  ;
    END
  END ZN
  PIN VDD
    DIRECTION INOUT ;
    USE power ;
    SHAPE ABUTMENT ;
    PORT
      LAYER metal1 ;
        POLYGON 0 1.315 0.065 1.315 0.065 0.975 0.135 0.975 0.135 1.315 0.51 1.315 0.63 1.315 0.63 0.975 0.7 0.975 0.7 1.315 0.76 1.315 0.76 1.485 0.51 1.485 0 1.485  ;
    END
  END VDD
  PIN VSS
    DIRECTION INOUT ;
    USE ground ;
    SHAPE ABUTMENT ;
    PORT
      LAYER metal1 ;
        POLYGON 0 -0.085 0.76 -0.085 0.76 0.085 0.7 0.085 0.7 0.46 0.63 0.46 0.63 0.085 0 0.085  ;
    END
  END VSS
  OBS
      LAYER metal1 ;
        POLYGON 0.07 0.15 0.51 0.15 0.51 0.425 0.44 0.425 0.44 0.22 0.14 0.22 0.14 0.425 0.07 0.425  ;
  END
END OAI21_X1

MACRO OAI21_X2
  CLASS core ;
  FOREIGN OAI21_X2 0.0 0.0 ;
  ORIGIN 0 0 ;
  SYMMETRY X Y ;
  SITE FreePDK45_38x28_10R_NP_162NW_34O ;
  SIZE 1.33 BY 1.4 ;
  PIN B
    DIRECTION INPUT ;
    ANTENNAPARTIALMETALAREA 0.02275 LAYER metal1 ;
    ANTENNAPARTIALMETALSIDEAREA 0.0793 LAYER metal1 ;
    ANTENNAGATEAREA 0.1045 ;
    PORT
      LAYER metal1 ;
        POLYGON 0.06 0.525 0.19 0.525 0.19 0.7 0.06 0.7  ;
    END
  END B
  PIN A1
    DIRECTION INPUT ;
    ANTENNAPARTIALMETALAREA 0.014875 LAYER metal1 ;
    ANTENNAPARTIALMETALSIDEAREA 0.0676 LAYER metal1 ;
    ANTENNAGATEAREA 0.1045 ;
    PORT
      LAYER metal1 ;
        POLYGON 0.805 0.525 0.89 0.525 0.89 0.7 0.805 0.7  ;
    END
  END A1
  PIN A2
    DIRECTION INPUT ;
    ANTENNAPARTIALMETALAREA 0.09765 LAYER metal1 ;
    ANTENNAPARTIALMETALSIDEAREA 0.3263 LAYER metal1 ;
    ANTENNAGATEAREA 0.1045 ;
    PORT
      LAYER metal1 ;
        POLYGON 0.44 0.525 0.57 0.525 0.57 0.77 1.065 0.77 1.065 0.525 1.135 0.525 1.135 0.84 0.44 0.84  ;
    END
  END A2
  PIN ZN
    DIRECTION OUTPUT ;
    ANTENNAPARTIALMETALAREA 0.19285 LAYER metal1 ;
    ANTENNAPARTIALMETALSIDEAREA 0.7345 LAYER metal1 ;
    ANTENNADIFFAREA 0.2926 ;
    PORT
      LAYER metal1 ;
        POLYGON 0.235 0.905 1.2 0.905 1.2 0.425 0.58 0.425 0.58 0.355 1.27 0.355 1.27 0.975 0.865 0.975 0.865 1.25 0.795 1.25 0.795 0.975 0.305 0.975 0.305 1.25 0.235 1.25  ;
    END
  END ZN
  PIN VDD
    DIRECTION INOUT ;
    USE power ;
    SHAPE ABUTMENT ;
    PORT
      LAYER metal1 ;
        POLYGON 0 1.315 0.04 1.315 0.04 1.04 0.11 1.04 0.11 1.315 0.415 1.315 0.415 1.04 0.485 1.04 0.485 1.315 1.175 1.315 1.175 1.04 1.245 1.04 1.245 1.315 1.28 1.315 1.33 1.315 1.33 1.485 1.28 1.485 0 1.485  ;
    END
  END VDD
  PIN VSS
    DIRECTION INOUT ;
    USE ground ;
    SHAPE ABUTMENT ;
    PORT
      LAYER metal1 ;
        POLYGON 0 -0.085 1.33 -0.085 1.33 0.085 0.295 0.085 0.295 0.285 0.225 0.285 0.225 0.085 0 0.085  ;
    END
  END VSS
  OBS
      LAYER metal1 ;
        POLYGON 0.045 0.15 0.115 0.15 0.115 0.355 0.415 0.355 0.415 0.15 1.28 0.15 1.28 0.22 0.485 0.22 0.485 0.425 0.045 0.425  ;
  END
END OAI21_X2

MACRO OAI22_X1
  CLASS core ;
  FOREIGN OAI22_X1 0.0 0.0 ;
  ORIGIN 0 0 ;
  SYMMETRY X Y ;
  SITE FreePDK45_38x28_10R_NP_162NW_34O ;
  SIZE 0.95 BY 1.4 ;
  PIN A1
    DIRECTION INPUT ;
    ANTENNAPARTIALMETALAREA 0.021875 LAYER metal1 ;
    ANTENNAPARTIALMETALSIDEAREA 0.078 LAYER metal1 ;
    ANTENNAGATEAREA 0.05225 ;
    PORT
      LAYER metal1 ;
        POLYGON 0.575 0.525 0.7 0.525 0.7 0.7 0.575 0.7  ;
    END
  END A1
  PIN A2
    DIRECTION INPUT ;
    ANTENNAPARTIALMETALAREA 0.021875 LAYER metal1 ;
    ANTENNAPARTIALMETALSIDEAREA 0.078 LAYER metal1 ;
    ANTENNAGATEAREA 0.05225 ;
    PORT
      LAYER metal1 ;
        POLYGON 0.765 0.525 0.88 0.525 0.89 0.525 0.89 0.7 0.88 0.7 0.765 0.7  ;
    END
  END A2
  PIN B1
    DIRECTION INPUT ;
    ANTENNAPARTIALMETALAREA 0.021875 LAYER metal1 ;
    ANTENNAPARTIALMETALSIDEAREA 0.078 LAYER metal1 ;
    ANTENNAGATEAREA 0.05225 ;
    PORT
      LAYER metal1 ;
        POLYGON 0.25 0.525 0.375 0.525 0.375 0.7 0.25 0.7  ;
    END
  END B1
  PIN B2
    DIRECTION INPUT ;
    ANTENNAPARTIALMETALAREA 0.021875 LAYER metal1 ;
    ANTENNAPARTIALMETALSIDEAREA 0.078 LAYER metal1 ;
    ANTENNAGATEAREA 0.05225 ;
    PORT
      LAYER metal1 ;
        POLYGON 0.06 0.525 0.185 0.525 0.185 0.7 0.06 0.7  ;
    END
  END B2
  PIN ZN
    DIRECTION OUTPUT ;
    ANTENNAPARTIALMETALAREA 0.06125 LAYER metal1 ;
    ANTENNAPARTIALMETALSIDEAREA 0.2457 LAYER metal1 ;
    ANTENNADIFFAREA 0.1463 ;
    PORT
      LAYER metal1 ;
        POLYGON 0.44 0.39 0.725 0.39 0.725 0.46 0.51 0.46 0.51 1.05 0.44 1.05  ;
    END
  END ZN
  PIN VDD
    DIRECTION INOUT ;
    USE power ;
    SHAPE ABUTMENT ;
    PORT
      LAYER metal1 ;
        POLYGON 0 1.315 0.055 1.315 0.055 0.975 0.125 0.975 0.125 1.315 0.81 1.315 0.81 0.975 0.88 0.975 0.88 1.315 0.95 1.315 0.95 1.485 0.88 1.485 0 1.485  ;
    END
  END VDD
  PIN VSS
    DIRECTION INOUT ;
    USE ground ;
    SHAPE ABUTMENT ;
    PORT
      LAYER metal1 ;
        POLYGON 0 -0.085 0.95 -0.085 0.95 0.085 0.345 0.085 0.345 0.16 0.21 0.16 0.21 0.085 0 0.085  ;
    END
  END VSS
  OBS
      LAYER metal1 ;
        POLYGON 0.06 0.185 0.13 0.185 0.13 0.245 0.81 0.245 0.81 0.185 0.88 0.185 0.88 0.46 0.81 0.46 0.81 0.315 0.13 0.315 0.13 0.46 0.06 0.46  ;
  END
END OAI22_X1

MACRO OAI22_X2
  CLASS core ;
  FOREIGN OAI22_X2 0.0 0.0 ;
  ORIGIN 0 0 ;
  SYMMETRY X Y ;
  SITE FreePDK45_38x28_10R_NP_162NW_34O ;
  SIZE 1.71 BY 1.4 ;
  PIN A1
    DIRECTION INPUT ;
    ANTENNAPARTIALMETALAREA 0.014875 LAYER metal1 ;
    ANTENNAPARTIALMETALSIDEAREA 0.0676 LAYER metal1 ;
    ANTENNAGATEAREA 0.1045 ;
    PORT
      LAYER metal1 ;
        POLYGON 1.185 0.525 1.27 0.525 1.27 0.7 1.185 0.7  ;
    END
  END A1
  PIN A2
    DIRECTION INPUT ;
    ANTENNAPARTIALMETALAREA 0.09665 LAYER metal1 ;
    ANTENNAPARTIALMETALSIDEAREA 0.3237 LAYER metal1 ;
    ANTENNAGATEAREA 0.1045 ;
    PORT
      LAYER metal1 ;
        POLYGON 0.82 0.525 0.95 0.525 0.95 0.765 1.445 0.765 1.445 0.525 1.515 0.525 1.515 0.835 0.82 0.835  ;
    END
  END A2
  PIN B1
    DIRECTION INPUT ;
    ANTENNAPARTIALMETALAREA 0.0175 LAYER metal1 ;
    ANTENNAPARTIALMETALSIDEAREA 0.0715 LAYER metal1 ;
    ANTENNAGATEAREA 0.1045 ;
    PORT
      LAYER metal1 ;
        POLYGON 0.425 0.525 0.525 0.525 0.525 0.7 0.425 0.7  ;
    END
  END B1
  PIN B2
    DIRECTION INPUT ;
    ANTENNAPARTIALMETALAREA 0.0951 LAYER metal1 ;
    ANTENNAPARTIALMETALSIDEAREA 0.3224 LAYER metal1 ;
    ANTENNAGATEAREA 0.1045 ;
    PORT
      LAYER metal1 ;
        POLYGON 0.06 0.525 0.185 0.525 0.185 0.765 0.68 0.765 0.68 0.525 0.75 0.525 0.75 0.835 0.06 0.835  ;
    END
  END B2
  PIN ZN
    DIRECTION OUTPUT ;
    ANTENNAPARTIALMETALAREA 0.20405 LAYER metal1 ;
    ANTENNAPARTIALMETALSIDEAREA 0.7761 LAYER metal1 ;
    ANTENNADIFFAREA 0.2926 ;
    PORT
      LAYER metal1 ;
        POLYGON 0.425 0.9 1.58 0.9 1.58 0.46 0.96 0.46 0.96 0.39 1.65 0.39 1.65 0.97 1.255 0.97 1.255 1.25 1.185 1.25 1.185 0.97 0.495 0.97 0.495 1.25 0.425 1.25  ;
    END
  END ZN
  PIN VDD
    DIRECTION INOUT ;
    USE power ;
    SHAPE ABUTMENT ;
    PORT
      LAYER metal1 ;
        POLYGON 0 1.315 0.04 1.315 0.04 1.035 0.11 1.035 0.11 1.315 0.795 1.315 0.795 1.035 0.865 1.035 0.865 1.315 1.555 1.315 1.555 1.035 1.625 1.035 1.625 1.315 1.66 1.315 1.71 1.315 1.71 1.485 1.66 1.485 0 1.485  ;
    END
  END VDD
  PIN VSS
    DIRECTION INOUT ;
    USE ground ;
    SHAPE ABUTMENT ;
    PORT
      LAYER metal1 ;
        POLYGON 0 -0.085 1.71 -0.085 1.71 0.085 0.675 0.085 0.675 0.285 0.605 0.285 0.605 0.085 0.295 0.085 0.295 0.285 0.225 0.285 0.225 0.085 0 0.085  ;
    END
  END VSS
  OBS
      LAYER metal1 ;
        POLYGON 0.045 0.15 0.115 0.15 0.115 0.355 0.415 0.355 0.415 0.15 0.485 0.15 0.485 0.355 0.795 0.355 0.795 0.15 1.66 0.15 1.66 0.22 0.865 0.22 0.865 0.425 0.045 0.425  ;
  END
END OAI22_X2

MACRO OR2_X1
  CLASS core ;
  FOREIGN OR2_X1 0.0 0.0 ;
  ORIGIN 0 0 ;
  SYMMETRY X Y ;
  SITE FreePDK45_38x28_10R_NP_162NW_34O ;
  SIZE 0.76 BY 1.4 ;
  PIN A1
    DIRECTION INPUT ;
    ANTENNAPARTIALMETALAREA 0.021875 LAYER metal1 ;
    ANTENNAPARTIALMETALSIDEAREA 0.078 LAYER metal1 ;
    ANTENNAGATEAREA 0.02625 ;
    PORT
      LAYER metal1 ;
        POLYGON 0.06 0.525 0.185 0.525 0.185 0.7 0.06 0.7  ;
    END
  END A1
  PIN A2
    DIRECTION INPUT ;
    ANTENNAPARTIALMETALAREA 0.02275 LAYER metal1 ;
    ANTENNAPARTIALMETALSIDEAREA 0.0793 LAYER metal1 ;
    ANTENNAGATEAREA 0.02625 ;
    PORT
      LAYER metal1 ;
        POLYGON 0.25 0.525 0.38 0.525 0.38 0.7 0.25 0.7  ;
    END
  END A2
  PIN Z
    DIRECTION OUTPUT ;
    ANTENNAPARTIALMETALAREA 0.0981 LAYER metal1 ;
    ANTENNAPARTIALMETALSIDEAREA 0.3068 LAYER metal1 ;
    ANTENNADIFFAREA 0.109725 ;
    PORT
      LAYER metal1 ;
        POLYGON 0.61 0.15 0.7 0.15 0.7 1.24 0.61 1.24  ;
    END
  END Z
  PIN VDD
    DIRECTION INOUT ;
    USE power ;
    SHAPE ABUTMENT ;
    PORT
      LAYER metal1 ;
        POLYGON 0 1.315 0.415 1.315 0.415 0.965 0.485 0.965 0.485 1.315 0.54 1.315 0.76 1.315 0.76 1.485 0.54 1.485 0 1.485  ;
    END
  END VDD
  PIN VSS
    DIRECTION INOUT ;
    USE ground ;
    SHAPE ABUTMENT ;
    PORT
      LAYER metal1 ;
        POLYGON 0 -0.085 0.76 -0.085 0.76 0.085 0.485 0.085 0.485 0.285 0.415 0.285 0.415 0.085 0.11 0.085 0.11 0.285 0.04 0.285 0.04 0.085 0 0.085  ;
    END
  END VSS
  OBS
      LAYER metal1 ;
        POLYGON 0.045 0.83 0.47 0.83 0.47 0.42 0.235 0.42 0.235 0.15 0.305 0.15 0.305 0.35 0.54 0.35 0.54 0.9 0.115 0.9 0.115 1.24 0.045 1.24  ;
  END
END OR2_X1

MACRO OR2_X2
  CLASS core ;
  FOREIGN OR2_X2 0.0 0.0 ;
  ORIGIN 0 0 ;
  SYMMETRY X Y ;
  SITE FreePDK45_38x28_10R_NP_162NW_34O ;
  SIZE 0.95 BY 1.4 ;
  PIN A1
    DIRECTION INPUT ;
    ANTENNAPARTIALMETALAREA 0.021875 LAYER metal1 ;
    ANTENNAPARTIALMETALSIDEAREA 0.078 LAYER metal1 ;
    ANTENNAGATEAREA 0.05225 ;
    PORT
      LAYER metal1 ;
        POLYGON 0.06 0.525 0.185 0.525 0.185 0.7 0.06 0.7  ;
    END
  END A1
  PIN A2
    DIRECTION INPUT ;
    ANTENNAPARTIALMETALAREA 0.02275 LAYER metal1 ;
    ANTENNAPARTIALMETALSIDEAREA 0.0793 LAYER metal1 ;
    ANTENNAGATEAREA 0.05225 ;
    PORT
      LAYER metal1 ;
        POLYGON 0.25 0.525 0.38 0.525 0.38 0.7 0.25 0.7  ;
    END
  END A2
  PIN Z
    DIRECTION OUTPUT ;
    ANTENNAPARTIALMETALAREA 0.0935 LAYER metal1 ;
    ANTENNAPARTIALMETALSIDEAREA 0.3081 LAYER metal1 ;
    ANTENNADIFFAREA 0.1463 ;
    PORT
      LAYER metal1 ;
        POLYGON 0.615 0.15 0.7 0.15 0.7 1.25 0.615 1.25  ;
    END
  END Z
  PIN VDD
    DIRECTION INOUT ;
    USE power ;
    SHAPE ABUTMENT ;
    PORT
      LAYER metal1 ;
        POLYGON 0 1.315 0.415 1.315 0.415 1.04 0.485 1.04 0.485 1.315 0.545 1.315 0.795 1.315 0.795 0.975 0.865 0.975 0.865 1.315 0.95 1.315 0.95 1.485 0.545 1.485 0 1.485  ;
    END
  END VDD
  PIN VSS
    DIRECTION INOUT ;
    USE ground ;
    SHAPE ABUTMENT ;
    PORT
      LAYER metal1 ;
        POLYGON 0 -0.085 0.95 -0.085 0.95 0.085 0.865 0.085 0.865 0.425 0.795 0.425 0.795 0.085 0.485 0.085 0.485 0.285 0.415 0.285 0.415 0.085 0.11 0.085 0.11 0.425 0.04 0.425 0.04 0.085 0 0.085  ;
    END
  END VSS
  OBS
      LAYER metal1 ;
        POLYGON 0.045 0.905 0.475 0.905 0.475 0.425 0.235 0.425 0.235 0.15 0.305 0.15 0.305 0.355 0.545 0.355 0.545 0.975 0.115 0.975 0.115 1.25 0.045 1.25  ;
  END
END OR2_X2

MACRO OR3_X1
  CLASS core ;
  FOREIGN OR3_X1 0.0 0.0 ;
  ORIGIN 0 0 ;
  SYMMETRY X Y ;
  SITE FreePDK45_38x28_10R_NP_162NW_34O ;
  SIZE 0.95 BY 1.4 ;
  PIN A1
    DIRECTION INPUT ;
    ANTENNAPARTIALMETALAREA 0.021875 LAYER metal1 ;
    ANTENNAPARTIALMETALSIDEAREA 0.078 LAYER metal1 ;
    ANTENNAGATEAREA 0.02625 ;
    PORT
      LAYER metal1 ;
        POLYGON 0.06 0.525 0.185 0.525 0.185 0.7 0.06 0.7  ;
    END
  END A1
  PIN A2
    DIRECTION INPUT ;
    ANTENNAPARTIALMETALAREA 0.021875 LAYER metal1 ;
    ANTENNAPARTIALMETALSIDEAREA 0.078 LAYER metal1 ;
    ANTENNAGATEAREA 0.02625 ;
    PORT
      LAYER metal1 ;
        POLYGON 0.25 0.525 0.375 0.525 0.375 0.7 0.25 0.7  ;
    END
  END A2
  PIN A3
    DIRECTION INPUT ;
    ANTENNAPARTIALMETALAREA 0.02275 LAYER metal1 ;
    ANTENNAPARTIALMETALSIDEAREA 0.0793 LAYER metal1 ;
    ANTENNAGATEAREA 0.02625 ;
    PORT
      LAYER metal1 ;
        POLYGON 0.44 0.525 0.57 0.525 0.57 0.7 0.44 0.7  ;
    END
  END A3
  PIN Z
    DIRECTION OUTPUT ;
    ANTENNAPARTIALMETALAREA 0.0981 LAYER metal1 ;
    ANTENNAPARTIALMETALSIDEAREA 0.3068 LAYER metal1 ;
    ANTENNADIFFAREA 0.109725 ;
    PORT
      LAYER metal1 ;
        POLYGON 0.8 0.15 0.89 0.15 0.89 1.24 0.8 1.24  ;
    END
  END Z
  PIN VDD
    DIRECTION INOUT ;
    USE power ;
    SHAPE ABUTMENT ;
    PORT
      LAYER metal1 ;
        POLYGON 0 1.315 0.605 1.315 0.605 0.965 0.675 0.965 0.675 1.315 0.73 1.315 0.95 1.315 0.95 1.485 0.73 1.485 0 1.485  ;
    END
  END VDD
  PIN VSS
    DIRECTION INOUT ;
    USE ground ;
    SHAPE ABUTMENT ;
    PORT
      LAYER metal1 ;
        POLYGON 0 -0.085 0.95 -0.085 0.95 0.085 0.675 0.085 0.675 0.285 0.605 0.285 0.605 0.085 0.295 0.085 0.295 0.285 0.225 0.285 0.225 0.085 0 0.085  ;
    END
  END VSS
  OBS
      LAYER metal1 ;
        POLYGON 0.045 0.83 0.66 0.83 0.66 0.42 0.045 0.42 0.045 0.15 0.115 0.15 0.115 0.35 0.415 0.35 0.415 0.15 0.485 0.15 0.485 0.35 0.73 0.35 0.73 0.9 0.115 0.9 0.115 1.24 0.045 1.24  ;
  END
END OR3_X1

MACRO OR3_X2
  CLASS core ;
  FOREIGN OR3_X2 0.0 0.0 ;
  ORIGIN 0 0 ;
  SYMMETRY X Y ;
  SITE FreePDK45_38x28_10R_NP_162NW_34O ;
  SIZE 1.14 BY 1.4 ;
  PIN A1
    DIRECTION INPUT ;
    ANTENNAPARTIALMETALAREA 0.021875 LAYER metal1 ;
    ANTENNAPARTIALMETALSIDEAREA 0.078 LAYER metal1 ;
    ANTENNAGATEAREA 0.05225 ;
    PORT
      LAYER metal1 ;
        POLYGON 0.06 0.525 0.185 0.525 0.185 0.7 0.06 0.7  ;
    END
  END A1
  PIN A2
    DIRECTION INPUT ;
    ANTENNAPARTIALMETALAREA 0.021875 LAYER metal1 ;
    ANTENNAPARTIALMETALSIDEAREA 0.078 LAYER metal1 ;
    ANTENNAGATEAREA 0.05225 ;
    PORT
      LAYER metal1 ;
        POLYGON 0.25 0.525 0.375 0.525 0.375 0.7 0.25 0.7  ;
    END
  END A2
  PIN A3
    DIRECTION INPUT ;
    ANTENNAPARTIALMETALAREA 0.02275 LAYER metal1 ;
    ANTENNAPARTIALMETALSIDEAREA 0.0793 LAYER metal1 ;
    ANTENNAGATEAREA 0.05225 ;
    PORT
      LAYER metal1 ;
        POLYGON 0.44 0.525 0.57 0.525 0.57 0.7 0.44 0.7  ;
    END
  END A3
  PIN Z
    DIRECTION OUTPUT ;
    ANTENNAPARTIALMETALAREA 0.0935 LAYER metal1 ;
    ANTENNAPARTIALMETALSIDEAREA 0.3081 LAYER metal1 ;
    ANTENNADIFFAREA 0.1463 ;
    PORT
      LAYER metal1 ;
        POLYGON 0.805 0.15 0.89 0.15 0.89 1.25 0.805 1.25  ;
    END
  END Z
  PIN VDD
    DIRECTION INOUT ;
    USE power ;
    SHAPE ABUTMENT ;
    PORT
      LAYER metal1 ;
        POLYGON 0 1.315 0.605 1.315 0.605 0.975 0.675 0.975 0.675 1.315 0.73 1.315 0.985 1.315 0.985 0.975 1.055 0.975 1.055 1.315 1.14 1.315 1.14 1.485 0.73 1.485 0 1.485  ;
    END
  END VDD
  PIN VSS
    DIRECTION INOUT ;
    USE ground ;
    SHAPE ABUTMENT ;
    PORT
      LAYER metal1 ;
        POLYGON 0 -0.085 1.14 -0.085 1.14 0.085 1.055 0.085 1.055 0.425 0.985 0.425 0.985 0.085 0.675 0.085 0.675 0.285 0.605 0.285 0.605 0.085 0.295 0.085 0.295 0.285 0.225 0.285 0.225 0.085 0 0.085  ;
    END
  END VSS
  OBS
      LAYER metal1 ;
        POLYGON 0.045 0.84 0.66 0.84 0.66 0.46 0.045 0.46 0.045 0.15 0.115 0.15 0.115 0.39 0.415 0.39 0.415 0.15 0.485 0.15 0.485 0.39 0.73 0.39 0.73 0.91 0.115 0.91 0.115 1.25 0.045 1.25  ;
  END
END OR3_X2

MACRO OR4_X1
  CLASS core ;
  FOREIGN OR4_X1 0.0 0.0 ;
  ORIGIN 0 0 ;
  SYMMETRY X Y ;
  SITE FreePDK45_38x28_10R_NP_162NW_34O ;
  SIZE 1.14 BY 1.4 ;
  PIN A1
    DIRECTION INPUT ;
    ANTENNAPARTIALMETALAREA 0.021875 LAYER metal1 ;
    ANTENNAPARTIALMETALSIDEAREA 0.078 LAYER metal1 ;
    ANTENNAGATEAREA 0.02625 ;
    PORT
      LAYER metal1 ;
        POLYGON 0.06 0.525 0.185 0.525 0.185 0.7 0.06 0.7  ;
    END
  END A1
  PIN A2
    DIRECTION INPUT ;
    ANTENNAPARTIALMETALAREA 0.021875 LAYER metal1 ;
    ANTENNAPARTIALMETALSIDEAREA 0.078 LAYER metal1 ;
    ANTENNAGATEAREA 0.02625 ;
    PORT
      LAYER metal1 ;
        POLYGON 0.25 0.525 0.375 0.525 0.375 0.7 0.25 0.7  ;
    END
  END A2
  PIN A3
    DIRECTION INPUT ;
    ANTENNAPARTIALMETALAREA 0.021875 LAYER metal1 ;
    ANTENNAPARTIALMETALSIDEAREA 0.078 LAYER metal1 ;
    ANTENNAGATEAREA 0.02625 ;
    PORT
      LAYER metal1 ;
        POLYGON 0.44 0.525 0.565 0.525 0.565 0.7 0.44 0.7  ;
    END
  END A3
  PIN A4
    DIRECTION INPUT ;
    ANTENNAPARTIALMETALAREA 0.02275 LAYER metal1 ;
    ANTENNAPARTIALMETALSIDEAREA 0.0793 LAYER metal1 ;
    ANTENNAGATEAREA 0.02625 ;
    PORT
      LAYER metal1 ;
        POLYGON 0.63 0.525 0.76 0.525 0.76 0.7 0.63 0.7  ;
    END
  END A4
  PIN Z
    DIRECTION OUTPUT ;
    ANTENNAPARTIALMETALAREA 0.0981 LAYER metal1 ;
    ANTENNAPARTIALMETALSIDEAREA 0.3068 LAYER metal1 ;
    ANTENNADIFFAREA 0.109725 ;
    PORT
      LAYER metal1 ;
        POLYGON 0.99 0.15 1.08 0.15 1.08 1.24 0.99 1.24  ;
    END
  END Z
  PIN VDD
    DIRECTION INOUT ;
    USE power ;
    SHAPE ABUTMENT ;
    PORT
      LAYER metal1 ;
        POLYGON 0 1.315 0.795 1.315 0.795 0.965 0.865 0.965 0.865 1.315 0.92 1.315 1.14 1.315 1.14 1.485 0.92 1.485 0 1.485  ;
    END
  END VDD
  PIN VSS
    DIRECTION INOUT ;
    USE ground ;
    SHAPE ABUTMENT ;
    PORT
      LAYER metal1 ;
        POLYGON 0 -0.085 1.14 -0.085 1.14 0.085 0.865 0.085 0.865 0.285 0.795 0.285 0.795 0.085 0.485 0.085 0.485 0.285 0.415 0.285 0.415 0.085 0.11 0.085 0.11 0.285 0.04 0.285 0.04 0.085 0 0.085  ;
    END
  END VSS
  OBS
      LAYER metal1 ;
        POLYGON 0.045 0.83 0.85 0.83 0.85 0.42 0.235 0.42 0.235 0.15 0.305 0.15 0.305 0.35 0.605 0.35 0.605 0.15 0.675 0.15 0.675 0.35 0.92 0.35 0.92 0.9 0.115 0.9 0.115 1.24 0.045 1.24  ;
  END
END OR4_X1

MACRO OR4_X2
  CLASS core ;
  FOREIGN OR4_X2 0.0 0.0 ;
  ORIGIN 0 0 ;
  SYMMETRY X Y ;
  SITE FreePDK45_38x28_10R_NP_162NW_34O ;
  SIZE 1.33 BY 1.4 ;
  PIN A1
    DIRECTION INPUT ;
    ANTENNAPARTIALMETALAREA 0.021875 LAYER metal1 ;
    ANTENNAPARTIALMETALSIDEAREA 0.078 LAYER metal1 ;
    ANTENNAGATEAREA 0.05225 ;
    PORT
      LAYER metal1 ;
        POLYGON 0.06 0.525 0.185 0.525 0.185 0.7 0.06 0.7  ;
    END
  END A1
  PIN A2
    DIRECTION INPUT ;
    ANTENNAPARTIALMETALAREA 0.021875 LAYER metal1 ;
    ANTENNAPARTIALMETALSIDEAREA 0.078 LAYER metal1 ;
    ANTENNAGATEAREA 0.05225 ;
    PORT
      LAYER metal1 ;
        POLYGON 0.25 0.525 0.375 0.525 0.375 0.7 0.25 0.7  ;
    END
  END A2
  PIN A3
    DIRECTION INPUT ;
    ANTENNAPARTIALMETALAREA 0.021875 LAYER metal1 ;
    ANTENNAPARTIALMETALSIDEAREA 0.078 LAYER metal1 ;
    ANTENNAGATEAREA 0.05225 ;
    PORT
      LAYER metal1 ;
        POLYGON 0.44 0.525 0.565 0.525 0.565 0.7 0.44 0.7  ;
    END
  END A3
  PIN A4
    DIRECTION INPUT ;
    ANTENNAPARTIALMETALAREA 0.02275 LAYER metal1 ;
    ANTENNAPARTIALMETALSIDEAREA 0.0793 LAYER metal1 ;
    ANTENNAGATEAREA 0.05225 ;
    PORT
      LAYER metal1 ;
        POLYGON 0.63 0.525 0.76 0.525 0.76 0.7 0.63 0.7  ;
    END
  END A4
  PIN Z
    DIRECTION OUTPUT ;
    ANTENNAPARTIALMETALAREA 0.0935 LAYER metal1 ;
    ANTENNAPARTIALMETALSIDEAREA 0.3081 LAYER metal1 ;
    ANTENNADIFFAREA 0.1463 ;
    PORT
      LAYER metal1 ;
        POLYGON 0.995 0.15 1.08 0.15 1.08 1.25 0.995 1.25  ;
    END
  END Z
  PIN VDD
    DIRECTION INOUT ;
    USE power ;
    SHAPE ABUTMENT ;
    PORT
      LAYER metal1 ;
        POLYGON 0 1.315 0.795 1.315 0.795 0.975 0.865 0.975 0.865 1.315 0.925 1.315 1.175 1.315 1.175 0.975 1.245 0.975 1.245 1.315 1.33 1.315 1.33 1.485 0.925 1.485 0 1.485  ;
    END
  END VDD
  PIN VSS
    DIRECTION INOUT ;
    USE ground ;
    SHAPE ABUTMENT ;
    PORT
      LAYER metal1 ;
        POLYGON 0 -0.085 1.33 -0.085 1.33 0.085 1.245 0.085 1.245 0.425 1.175 0.425 1.175 0.085 0.865 0.085 0.865 0.285 0.795 0.285 0.795 0.085 0.485 0.085 0.485 0.285 0.415 0.285 0.415 0.085 0.11 0.085 0.11 0.425 0.04 0.425 0.04 0.085 0 0.085  ;
    END
  END VSS
  OBS
      LAYER metal1 ;
        POLYGON 0.045 0.84 0.855 0.84 0.855 0.425 0.235 0.425 0.235 0.15 0.305 0.15 0.305 0.355 0.605 0.355 0.605 0.15 0.675 0.15 0.675 0.355 0.925 0.355 0.925 0.91 0.115 0.91 0.115 1.25 0.045 1.25  ;
  END
END OR4_X2

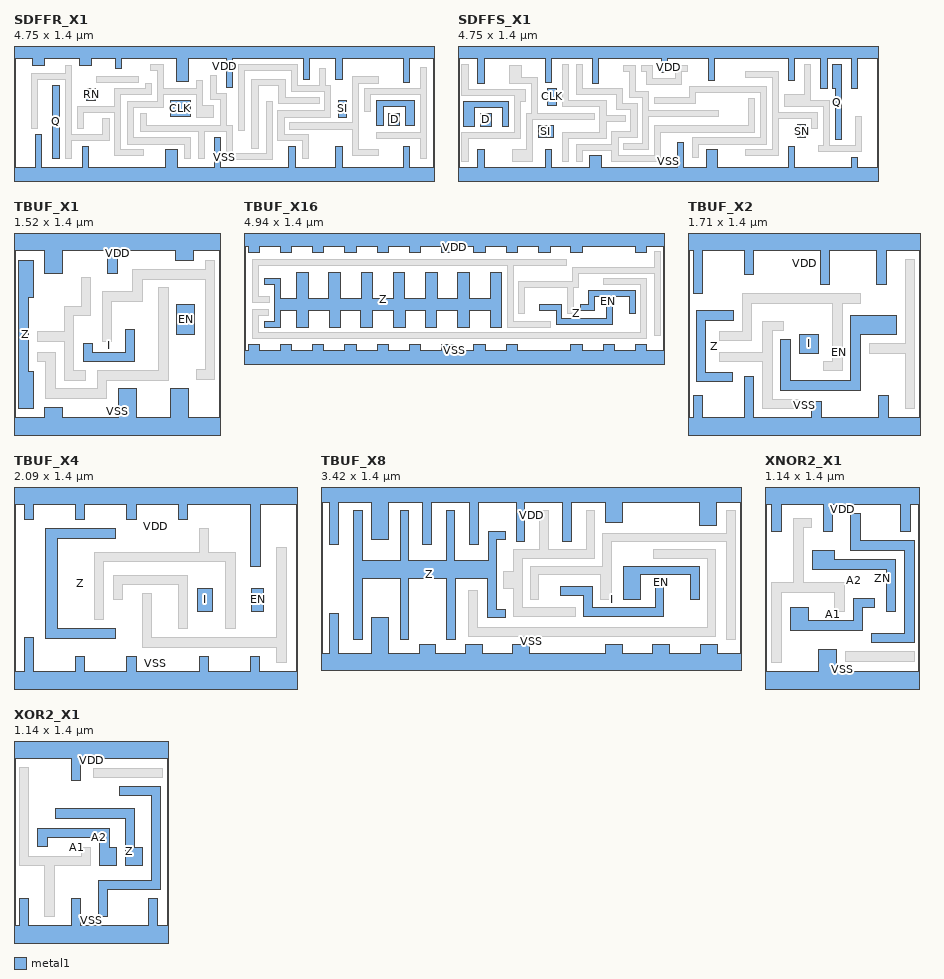
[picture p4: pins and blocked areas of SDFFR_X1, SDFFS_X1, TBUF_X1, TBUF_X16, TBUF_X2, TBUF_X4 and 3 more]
MACRO SDFFR_X1
  CLASS core ;
  FOREIGN SDFFR_X1 0.0 0.0 ;
  ORIGIN 0 0 ;
  SYMMETRY X Y ;
  SITE FreePDK45_38x28_10R_NP_162NW_34O ;
  SIZE 4.75 BY 1.4 ;
  PIN D
    DIRECTION INPUT ;
    ANTENNAPARTIALMETALAREA 0.0175 LAYER metal1 ;
    ANTENNAPARTIALMETALSIDEAREA 0.0689 LAYER metal1 ;
    ANTENNAGATEAREA 0.03475 ;
    PORT
      LAYER metal1 ;
        POLYGON 4.24 0.56 4.365 0.56 4.365 0.7 4.24 0.7  ;
    END
  END D
  PIN RN
    DIRECTION INPUT ;
    ANTENNAPARTIALMETALAREA 0.0147 LAYER metal1 ;
    ANTENNAPARTIALMETALSIDEAREA 0.0637 LAYER metal1 ;
    ANTENNAGATEAREA 0.03525 ;
    PORT
      LAYER metal1 ;
        POLYGON 0.82 0.84 0.925 0.84 0.925 0.98 0.82 0.98  ;
    END
  END RN
  PIN SE
    DIRECTION INPUT ;
    ANTENNAPARTIALMETALAREA 0.0651 LAYER metal1 ;
    ANTENNAPARTIALMETALSIDEAREA 0.2366 LAYER metal1 ;
    ANTENNAGATEAREA 0.05775 ;
    PORT
      LAYER metal1 ;
        POLYGON 4.105 0.565 4.175 0.565 4.175 0.77 4.43 0.77 4.43 0.56 4.53 0.56 4.53 0.84 4.105 0.84  ;
    END
  END SE
  PIN SI
    DIRECTION INPUT ;
    ANTENNAPARTIALMETALAREA 0.017575 LAYER metal1 ;
    ANTENNAPARTIALMETALSIDEAREA 0.0728 LAYER metal1 ;
    ANTENNAGATEAREA 0.02625 ;
    PORT
      LAYER metal1 ;
        POLYGON 3.67 0.655 3.765 0.655 3.765 0.84 3.67 0.84  ;
    END
  END SI
  PIN CLK
    DIRECTION INPUT ;
    ANTENNAPARTIALMETALAREA 0.0405 LAYER metal1 ;
    ANTENNAPARTIALMETALSIDEAREA 0.1053 LAYER metal1 ;
    ANTENNAGATEAREA 0.02625 ;
    PORT
      LAYER metal1 ;
        POLYGON 1.77 0.66 1.995 0.66 1.995 0.84 1.77 0.84  ;
    END
  END CLK
  PIN Q
    DIRECTION OUTPUT ;
    ANTENNAPARTIALMETALAREA 0.06225 LAYER metal1 ;
    ANTENNAPARTIALMETALSIDEAREA 0.2353 LAYER metal1 ;
    ANTENNADIFFAREA 0.109725 ;
    PORT
      LAYER metal1 ;
        POLYGON 0.435 0.185 0.51 0.185 0.51 1.015 0.435 1.015  ;
    END
  END Q
  PIN VDD
    DIRECTION INOUT ;
    USE power ;
    SHAPE ABUTMENT ;
    PORT
      LAYER metal1 ;
        POLYGON 0 1.315 0.21 1.315 0.21 1.24 0.345 1.24 0.345 1.315 0.74 1.315 0.74 1.24 0.875 1.24 0.875 1.315 1.15 1.315 1.15 1.205 1.22 1.205 1.22 1.315 1.41 1.315 1.84 1.315 1.84 1.06 1.975 1.06 1.975 1.315 2.4 1.315 2.4 0.995 2.47 0.995 2.47 1.315 3.27 1.315 3.27 1.08 3.34 1.08 3.34 1.315 3.585 1.315 3.64 1.315 3.64 1.08 3.71 1.08 3.71 1.315 4.125 1.315 4.4 1.315 4.4 1.045 4.47 1.045 4.47 1.315 4.665 1.315 4.75 1.315 4.75 1.485 4.665 1.485 4.125 1.485 3.585 1.485 1.41 1.485 0 1.485  ;
    END
  END VDD
  PIN VSS
    DIRECTION INOUT ;
    USE ground ;
    SHAPE ABUTMENT ;
    PORT
      LAYER metal1 ;
        POLYGON 0 -0.085 4.75 -0.085 4.75 0.085 4.47 0.085 4.47 0.32 4.4 0.32 4.4 0.085 3.71 0.085 3.71 0.32 3.64 0.32 3.64 0.085 3.18 0.085 3.18 0.32 3.11 0.32 3.11 0.085 2.34 0.085 2.34 0.425 2.27 0.425 2.27 0.085 1.845 0.085 1.845 0.285 1.71 0.285 1.71 0.085 0.84 0.085 0.84 0.32 0.77 0.32 0.77 0.085 0.31 0.085 0.31 0.46 0.24 0.46 0.24 0.085 0 0.085  ;
    END
  END VSS
  OBS
      LAYER metal1 ;
        POLYGON 0.195 0.525 0.265 0.525 0.265 1.08 0.585 1.08 0.585 0.185 0.655 0.185 0.655 0.39 1.075 0.39 1.075 0.635 1.005 0.635 1.005 0.46 0.655 0.46 0.655 1.24 0.585 1.24 0.585 1.15 0.195 1.15  ;
        POLYGON 0.935 1.045 1.41 1.045 1.41 1.115 0.935 1.115  ;
        POLYGON 1.21 0.905 1.56 0.905 1.56 1.04 1.49 1.04 1.49 0.975 1.14 0.975 1.14 0.775 0.72 0.775 0.72 0.525 0.79 0.525 0.79 0.705 1.14 0.705 1.14 0.215 1.46 0.215 1.46 0.285 1.21 0.285  ;
        POLYGON 1.35 0.765 1.695 0.765 1.695 0.905 2.065 0.905 2.065 0.655 2.26 0.655 2.26 0.79 2.135 0.79 2.135 1.065 2.065 1.065 2.065 0.975 1.695 0.975 1.695 1.25 1.545 1.25 1.545 1.18 1.625 1.18 1.625 0.835 1.28 0.835 1.28 0.35 1.93 0.35 1.93 0.185 2 0.185 2 0.42 1.35 0.42  ;
        POLYGON 2.22 0.855 2.335 0.855 2.335 0.56 1.5 0.56 1.5 0.7 1.43 0.7 1.43 0.49 2.09 0.49 2.09 0.185 2.16 0.185 2.16 0.49 2.405 0.49 2.405 0.17 2.92 0.17 2.92 0.835 2.85 0.835 2.85 0.24 2.475 0.24 2.475 0.56 2.405 0.56 2.405 0.925 2.29 0.925 2.29 1.13 2.22 1.13  ;
        POLYGON 2.69 0.305 2.76 0.305 2.76 1.015 2.995 1.015 2.995 0.81 3.45 0.81 3.45 0.88 3.065 0.88 3.065 1.085 2.69 1.085  ;
        POLYGON 2.54 0.505 2.61 0.505 2.61 1.18 3.135 1.18 3.135 0.945 3.515 0.945 3.515 0.725 2.985 0.725 2.985 0.385 3.265 0.385 3.265 0.185 3.335 0.185 3.335 0.455 3.055 0.455 3.055 0.655 3.585 0.655 3.585 1.015 3.52 1.015 3.52 1.2 3.45 1.2 3.45 1.015 3.205 1.015 3.205 1.25 2.54 1.25  ;
        POLYGON 3.9 1.04 4.125 1.04 4.125 1.11 3.83 1.11 3.83 0.59 3.12 0.59 3.12 0.52 3.83 0.52 3.83 0.22 4.125 0.22 4.125 0.29 3.9 0.29  ;
        POLYGON 3.965 0.715 4.035 0.715 4.035 0.905 4.595 0.905 4.595 0.485 4.1 0.485 4.1 0.415 4.595 0.415 4.595 0.185 4.665 0.185 4.665 1.22 4.595 1.22 4.595 0.975 3.965 0.975  ;
  END
END SDFFR_X1

MACRO SDFFS_X1
  CLASS core ;
  FOREIGN SDFFS_X1 0.0 0.0 ;
  ORIGIN 0 0 ;
  SYMMETRY X Y ;
  SITE FreePDK45_38x28_10R_NP_162NW_34O ;
  SIZE 4.75 BY 1.4 ;
  PIN D
    DIRECTION INPUT ;
    ANTENNAPARTIALMETALAREA 0.0195 LAYER metal1 ;
    ANTENNAPARTIALMETALSIDEAREA 0.0728 LAYER metal1 ;
    ANTENNAGATEAREA 0.03475 ;
    PORT
      LAYER metal1 ;
        POLYGON 0.25 0.55 0.38 0.55 0.38 0.7 0.25 0.7  ;
    END
  END D
  PIN SE
    DIRECTION INPUT ;
    ANTENNAPARTIALMETALAREA 0.077625 LAYER metal1 ;
    ANTENNAPARTIALMETALSIDEAREA 0.2626 LAYER metal1 ;
    ANTENNAGATEAREA 0.05775 ;
    PORT
      LAYER metal1 ;
        POLYGON 0.06 0.55 0.185 0.55 0.185 0.765 0.5 0.765 0.5 0.55 0.57 0.55 0.57 0.835 0.06 0.835  ;
    END
  END SE
  PIN SI
    DIRECTION INPUT ;
    ANTENNAPARTIALMETALAREA 0.0238 LAYER metal1 ;
    ANTENNAPARTIALMETALSIDEAREA 0.0806 LAYER metal1 ;
    ANTENNAGATEAREA 0.02625 ;
    PORT
      LAYER metal1 ;
        POLYGON 0.91 0.42 1.08 0.42 1.08 0.56 0.91 0.56  ;
    END
  END SI
  PIN SN
    DIRECTION INPUT ;
    ANTENNAPARTIALMETALAREA 0.01395 LAYER metal1 ;
    ANTENNAPARTIALMETALSIDEAREA 0.0637 LAYER metal1 ;
    ANTENNAGATEAREA 0.03525 ;
    PORT
      LAYER metal1 ;
        POLYGON 3.84 0.42 3.93 0.42 3.93 0.575 3.84 0.575  ;
    END
  END SN
  PIN CLK
    DIRECTION INPUT ;
    ANTENNAPARTIALMETALAREA 0.020475 LAYER metal1 ;
    ANTENNAPARTIALMETALSIDEAREA 0.078 LAYER metal1 ;
    ANTENNAGATEAREA 0.02625 ;
    PORT
      LAYER metal1 ;
        POLYGON 1.01 0.785 1.115 0.785 1.115 0.98 1.01 0.98  ;
    END
  END CLK
  PIN Q
    DIRECTION OUTPUT ;
    ANTENNAPARTIALMETALAREA 0.06625 LAYER metal1 ;
    ANTENNAPARTIALMETALSIDEAREA 0.2457 LAYER metal1 ;
    ANTENNADIFFAREA 0.109725 ;
    PORT
      LAYER metal1 ;
        POLYGON 4.24 0.98 4.265 0.98 4.265 0.4 4.335 0.4 4.335 1.25 4.24 1.25  ;
    END
  END Q
  PIN VDD
    DIRECTION INOUT ;
    USE power ;
    SHAPE ABUTMENT ;
    PORT
      LAYER metal1 ;
        POLYGON 0 1.315 0.225 1.315 0.225 1.035 0.295 1.035 0.295 1.315 0.985 1.315 0.985 1.045 1.055 1.045 1.055 1.315 1.52 1.315 1.52 1.04 1.59 1.04 1.59 1.315 2.3 1.315 2.3 1.155 2.37 1.155 2.37 1.315 2.59 1.315 2.83 1.315 2.83 1.07 2.9 1.07 2.9 1.315 3.735 1.315 3.735 1.07 3.805 1.07 3.805 1.315 4.105 1.315 4.105 0.975 4.175 0.975 4.175 1.315 4.445 1.315 4.445 0.975 4.515 0.975 4.515 1.315 4.565 1.315 4.75 1.315 4.75 1.485 4.565 1.485 2.59 1.485 0 1.485  ;
    END
  END VDD
  PIN VSS
    DIRECTION INOUT ;
    USE ground ;
    SHAPE ABUTMENT ;
    PORT
      LAYER metal1 ;
        POLYGON 0 -0.085 4.75 -0.085 4.75 0.085 4.515 0.085 4.515 0.195 4.445 0.195 4.445 0.085 3.805 0.085 3.805 0.32 3.735 0.32 3.735 0.085 2.94 0.085 2.94 0.285 2.805 0.285 2.805 0.085 2.555 0.085 2.555 0.37 2.485 0.37 2.485 0.085 1.625 0.085 1.625 0.215 1.49 0.215 1.49 0.085 1.055 0.085 1.055 0.285 0.985 0.285 0.985 0.085 0.295 0.085 0.295 0.285 0.225 0.285 0.225 0.085 0 0.085  ;
    END
  END VSS
  OBS
      LAYER metal1 ;
        POLYGON 0.045 0.9 0.635 0.9 0.635 0.485 0.045 0.485 0.045 0.15 0.115 0.15 0.115 0.415 0.705 0.415 0.705 0.835 0.765 0.835 0.765 0.97 0.115 0.97 0.115 1.25 0.045 1.25  ;
        POLYGON 0.58 1.035 0.83 1.035 0.83 0.695 0.775 0.695 0.775 0.285 0.615 0.285 0.615 0.15 0.845 0.15 0.845 0.625 1.54 0.625 1.54 0.695 0.9 0.695 0.9 1.105 0.715 1.105 0.715 1.24 0.58 1.24  ;
        POLYGON 1.18 0.77 1.605 0.77 1.605 0.485 1.18 0.485 1.18 0.15 1.25 0.15 1.25 0.415 1.675 0.415 1.675 0.6 1.89 0.6 1.89 0.67 1.675 0.67 1.675 0.84 1.25 0.84 1.25 1.25 1.18 1.25  ;
        POLYGON 2.07 1.17 2.135 1.17 2.135 1.02 2.525 1.02 2.525 1.17 2.59 1.17 2.59 1.24 2.455 1.24 2.455 1.09 2.205 1.09 2.205 1.24 2.07 1.24  ;
        POLYGON 1.87 1.17 1.935 1.17 1.935 0.88 2.09 0.88 2.09 0.355 1.875 0.355 1.875 0.285 2.16 0.285 2.16 0.665 2.945 0.665 2.945 0.735 2.16 0.735 2.16 0.95 2.005 0.95 2.005 1.24 1.87 1.24  ;
        POLYGON 1.34 0.905 1.795 0.905 1.795 0.74 1.955 0.74 1.955 0.49 1.74 0.49 1.74 0.35 1.34 0.35 1.34 0.15 1.41 0.15 1.41 0.28 1.74 0.28 1.74 0.15 2.295 0.15 2.295 0.485 3.355 0.485 3.355 0.86 3.285 0.86 3.285 0.555 2.225 0.555 2.225 0.22 1.81 0.22 1.81 0.42 2.025 0.42 2.025 0.81 1.865 0.81 1.865 0.975 1.41 0.975 1.41 1.25 1.34 1.25  ;
        POLYGON 2.225 0.805 2.685 0.805 2.685 0.93 3.42 0.93 3.42 0.42 2.65 0.42 2.65 0.2 2.72 0.2 2.72 0.35 3.49 0.35 3.49 1 2.615 1 2.615 0.875 2.225 0.875  ;
        POLYGON 3.255 1.1 3.555 1.1 3.555 0.285 3.25 0.285 3.25 0.215 3.625 0.215 3.625 0.64 3.995 0.64 3.995 0.525 4.065 0.525 4.065 0.71 3.625 0.71 3.625 1.17 3.255 1.17  ;
        POLYGON 3.69 0.775 4.13 0.775 4.13 0.335 4.075 0.335 4.075 0.265 4.565 0.265 4.565 0.66 4.495 0.66 4.495 0.335 4.2 0.335 4.2 0.845 3.985 0.845 3.985 1.25 3.915 1.25 3.915 0.915 3.69 0.915  ;
  END
END SDFFS_X1

MACRO TBUF_X1
  CLASS core ;
  FOREIGN TBUF_X1 0.0 0.0 ;
  ORIGIN 0 0 ;
  SYMMETRY X Y ;
  SITE FreePDK45_38x28_10R_NP_162NW_34O ;
  SIZE 1.52 BY 1.4 ;
  PIN I
    DIRECTION INPUT ;
    ANTENNAPARTIALMETALAREA 0.0427 LAYER metal1 ;
    ANTENNAPARTIALMETALSIDEAREA 0.1768 LAYER metal1 ;
    ANTENNAGATEAREA 0.0525 ;
    PORT
      LAYER metal1 ;
        POLYGON 0.51 0.495 0.89 0.495 0.89 0.73 0.82 0.73 0.82 0.565 0.58 0.565 0.58 0.63 0.51 0.63  ;
    END
  END I
  PIN EN
    DIRECTION INPUT ;
    ANTENNAPARTIALMETALAREA 0.02925 LAYER metal1 ;
    ANTENNAPARTIALMETALSIDEAREA 0.0923 LAYER metal1 ;
    ANTENNAGATEAREA 0.0525 ;
    PORT
      LAYER metal1 ;
        POLYGON 1.2 0.695 1.33 0.695 1.33 0.92 1.2 0.92  ;
    END
  END EN
  PIN Z
    DIRECTION OUTPUT ;
    ANTENNAPARTIALMETALAREA 0.0959 LAYER metal1 ;
    ANTENNAPARTIALMETALSIDEAREA 0.3211 LAYER metal1 ;
    ANTENNADIFFAREA 0.093975 ;
    PORT
      LAYER metal1 ;
        POLYGON 0.105 0.97 0.14 0.97 0.14 1.245 0.035 1.245 0.035 0.15 0.14 0.15 0.14 0.425 0.105 0.425  ;
    END
  END Z
  PIN VDD
    DIRECTION INOUT ;
    USE power ;
    SHAPE ABUTMENT ;
    PORT
      LAYER metal1 ;
        POLYGON 0 1.315 0.225 1.315 0.225 1.145 0.36 1.145 0.36 1.315 0.565 1.315 0.69 1.315 0.69 1.145 0.76 1.145 0.76 1.315 1.19 1.315 1.19 1.24 1.325 1.24 1.325 1.315 1.48 1.315 1.52 1.315 1.52 1.485 1.48 1.485 0.565 1.485 0 1.485  ;
    END
  END VDD
  PIN VSS
    DIRECTION INOUT ;
    USE ground ;
    SHAPE ABUTMENT ;
    PORT
      LAYER metal1 ;
        POLYGON 0 -0.085 1.52 -0.085 1.52 0.085 1.285 0.085 1.285 0.295 1.15 0.295 1.15 0.085 0.905 0.085 0.905 0.295 0.77 0.295 0.77 0.085 0.36 0.085 0.36 0.16 0.225 0.16 0.225 0.085 0 0.085  ;
    END
  END VSS
  OBS
      LAYER metal1 ;
        POLYGON 0.44 0.835 0.565 0.835 0.565 1.115 0.495 1.115 0.495 0.905 0.37 0.905 0.37 0.715 0.17 0.715 0.17 0.645 0.37 0.645 0.37 0.36 0.53 0.36 0.53 0.43 0.44 0.43  ;
        POLYGON 0.17 0.495 0.235 0.495 0.235 0.225 0.685 0.225 0.685 0.36 1.135 0.36 1.135 1.04 1.065 1.04 1.065 0.43 0.615 0.43 0.615 0.295 0.305 0.295 0.305 0.565 0.17 0.565  ;
        POLYGON 0.65 0.645 0.72 0.645 0.72 0.94 0.945 0.94 0.945 1.105 1.41 1.105 1.41 0.435 1.345 0.435 1.345 0.365 1.48 0.365 1.48 1.245 1.41 1.245 1.41 1.175 0.875 1.175 0.875 1.01 0.65 1.01  ;
  END
END TBUF_X1

MACRO TBUF_X16
  CLASS core ;
  FOREIGN TBUF_X16 0.0 0.0 ;
  ORIGIN 0 0 ;
  SYMMETRY X Y ;
  SITE FreePDK45_38x28_10R_NP_162NW_34O ;
  SIZE 4.94 BY 1.4 ;
  PIN Z
    DIRECTION INPUT ;
    ANTENNAPARTIALMETALAREA 0.08575 LAYER metal1 ;
    ANTENNAPARTIALMETALSIDEAREA 0.3367 LAYER metal1 ;
    ANTENNAGATEAREA 0.209 ;
    PORT
      LAYER metal1 ;
        POLYGON 3.475 0.555 3.67 0.555 3.67 0.39 4.335 0.39 4.335 0.66 4.265 0.66 4.265 0.46 3.74 0.46 3.74 0.625 3.475 0.625  ;
    END
  END Z
  PIN EN
    DIRECTION INPUT ;
    ANTENNAPARTIALMETALAREA 0.0707 LAYER metal1 ;
    ANTENNAPARTIALMETALSIDEAREA 0.2808 LAYER metal1 ;
    ANTENNAGATEAREA 0.15675 ;
    PORT
      LAYER metal1 ;
        POLYGON 3.955 0.56 4.12 0.56 4.12 0.725 4.53 0.725 4.53 0.525 4.6 0.525 4.6 0.795 4.05 0.795 4.05 0.63 3.955 0.63  ;
    END
  END EN
  PIN Z
    DIRECTION OUTPUT ;
    ANTENNAPARTIALMETALAREA 0.897925 LAYER metal1 ;
    ANTENNAPARTIALMETALSIDEAREA 1.8239 LAYER metal1 ;
    ANTENNADIFFAREA 1.0024 ;
    PORT
      LAYER metal1 ;
        POLYGON 0.24 0.86 0.36 0.86 0.36 0.43 0.24 0.43 0.24 0.36 0.43 0.36 0.43 0.56 0.62 0.56 0.62 0.36 0.755 0.36 0.755 0.56 1 0.56 1 0.36 1.135 0.36 1.135 0.56 1.375 0.56 1.375 0.36 1.51 0.36 1.51 0.56 1.76 0.56 1.76 0.36 1.895 0.36 1.895 0.56 2.135 0.56 2.135 0.36 2.27 0.36 2.27 0.56 2.515 0.56 2.515 0.36 2.65 0.36 2.65 0.56 2.895 0.56 2.895 0.36 3.03 0.36 3.03 1.005 2.895 1.005 2.895 0.7 2.65 0.7 2.65 1.005 2.515 1.005 2.515 0.7 2.275 0.7 2.275 1.005 2.14 1.005 2.14 0.7 1.89 0.7 1.89 1.005 1.755 1.005 1.755 0.7 1.515 0.7 1.515 1.005 1.38 1.005 1.38 0.7 1.13 0.7 1.13 1.005 0.995 1.005 0.995 0.7 0.755 0.7 0.755 1.005 0.62 1.005 0.62 0.7 0.43 0.7 0.43 0.93 0.24 0.93  ;
    END
  END Z
  PIN VDD
    DIRECTION INOUT ;
    USE power ;
    SHAPE ABUTMENT ;
    PORT
      LAYER metal1 ;
        POLYGON 0 1.315 0.05 1.315 0.05 1.24 0.185 1.24 0.185 1.315 0.425 1.315 0.425 1.24 0.56 1.24 0.56 1.315 0.805 1.315 0.805 1.24 0.94 1.24 0.94 1.315 1.185 1.315 1.185 1.24 1.32 1.24 1.32 1.315 1.565 1.315 1.565 1.24 1.7 1.24 1.7 1.315 1.945 1.315 1.945 1.24 2.08 1.24 2.08 1.315 2.325 1.315 2.325 1.24 2.46 1.24 2.46 1.315 2.705 1.315 2.705 1.24 2.84 1.24 2.84 1.315 3.085 1.315 3.085 1.24 3.22 1.24 3.22 1.315 3.465 1.315 3.465 1.24 3.6 1.24 3.6 1.315 3.79 1.315 3.845 1.315 3.845 1.24 3.98 1.24 3.98 1.315 4.605 1.315 4.605 1.24 4.74 1.24 4.74 1.315 4.895 1.315 4.94 1.315 4.94 1.485 4.895 1.485 3.79 1.485 0 1.485  ;
    END
  END VDD
  PIN VSS
    DIRECTION INOUT ;
    USE ground ;
    SHAPE ABUTMENT ;
    PORT
      LAYER metal1 ;
        POLYGON 0 -0.085 4.94 -0.085 4.94 0.085 4.74 0.085 4.74 0.16 4.605 0.16 4.605 0.085 4.36 0.085 4.36 0.16 4.225 0.16 4.225 0.085 3.98 0.085 3.98 0.16 3.845 0.16 3.845 0.085 3.22 0.085 3.22 0.16 3.085 0.16 3.085 0.085 2.84 0.085 2.84 0.16 2.705 0.16 2.705 0.085 2.46 0.085 2.46 0.16 2.325 0.16 2.325 0.085 2.08 0.085 2.08 0.16 1.945 0.16 1.945 0.085 1.7 0.085 1.7 0.16 1.565 0.16 1.565 0.085 1.32 0.085 1.32 0.16 1.185 0.16 1.185 0.085 0.94 0.085 0.94 0.16 0.805 0.16 0.805 0.085 0.56 0.085 0.56 0.16 0.425 0.16 0.425 0.085 0.185 0.085 0.185 0.16 0.05 0.16 0.05 0.085 0 0.085  ;
    END
  END VSS
  OBS
      LAYER metal1 ;
        POLYGON 3.165 1.085 3.79 1.085 3.79 1.155 0.105 1.155 0.105 0.65 0.295 0.65 0.295 0.72 0.175 0.72 0.175 1.085 3.095 1.085 3.095 0.36 3.6 0.36 3.6 0.43 3.165 0.43  ;
        POLYGON 4.23 0.86 4.665 0.86 4.665 0.295 0.175 0.295 0.175 0.495 0.29 0.495 0.29 0.565 0.105 0.565 0.105 0.225 4.735 0.225 4.735 0.93 4.23 0.93  ;
        POLYGON 3.23 0.525 3.3 0.525 3.3 0.83 3.805 0.83 3.805 0.525 3.875 0.525 3.875 0.83 3.93 0.83 3.93 0.995 4.825 0.995 4.825 0.26 4.895 0.26 4.895 1.25 4.825 1.25 4.825 1.065 3.86 1.065 3.86 0.9 3.23 0.9  ;
  END
END TBUF_X16

MACRO TBUF_X2
  CLASS core ;
  FOREIGN TBUF_X2 0.0 0.0 ;
  ORIGIN 0 0 ;
  SYMMETRY X Y ;
  SITE FreePDK45_38x28_10R_NP_162NW_34O ;
  SIZE 1.71 BY 1.4 ;
  PIN I
    DIRECTION INPUT ;
    ANTENNAPARTIALMETALAREA 0.0203 LAYER metal1 ;
    ANTENNAPARTIALMETALSIDEAREA 0.0741 LAYER metal1 ;
    ANTENNAGATEAREA 0.1045 ;
    PORT
      LAYER metal1 ;
        POLYGON 0.82 0.56 0.825 0.56 0.965 0.56 0.965 0.7 0.825 0.7 0.82 0.7  ;
    END
  END I
  PIN EN
    DIRECTION INPUT ;
    ANTENNAPARTIALMETALAREA 0.13335 LAYER metal1 ;
    ANTENNAPARTIALMETALSIDEAREA 0.4446 LAYER metal1 ;
    ANTENNAGATEAREA 0.0785 ;
    PORT
      LAYER metal1 ;
        POLYGON 0.685 0.285 0.825 0.285 1.27 0.285 1.27 0.7 1.535 0.7 1.535 0.84 1.2 0.84 1.2 0.355 0.825 0.355 0.755 0.355 0.755 0.66 0.685 0.66  ;
    END
  END EN
  PIN Z
    DIRECTION OUTPUT ;
    ANTENNAPARTIALMETALAREA 0.06475 LAYER metal1 ;
    ANTENNAPARTIALMETALSIDEAREA 0.2587 LAYER metal1 ;
    ANTENNADIFFAREA 0.1253 ;
    PORT
      LAYER metal1 ;
        POLYGON 0.13 0.8 0.335 0.8 0.335 0.87 0.06 0.87 0.06 0.35 0.33 0.35 0.33 0.42 0.13 0.42  ;
    END
  END Z
  PIN VDD
    DIRECTION INOUT ;
    USE power ;
    SHAPE ABUTMENT ;
    PORT
      LAYER metal1 ;
        POLYGON 0 1.315 0.04 1.315 0.04 0.995 0.11 0.995 0.11 1.315 0.415 1.315 0.415 1.135 0.485 1.135 0.485 1.315 0.975 1.315 0.975 1.065 1.045 1.065 1.045 1.315 1.27 1.315 1.39 1.315 1.39 1.065 1.46 1.065 1.46 1.315 1.67 1.315 1.71 1.315 1.71 1.485 1.67 1.485 1.27 1.485 0 1.485  ;
    END
  END VDD
  PIN VSS
    DIRECTION INOUT ;
    USE ground ;
    SHAPE ABUTMENT ;
    PORT
      LAYER metal1 ;
        POLYGON 0 -0.085 1.71 -0.085 1.71 0.085 1.475 0.085 1.475 0.25 1.405 0.25 1.405 0.085 0.98 0.085 0.98 0.2 0.91 0.2 0.91 0.085 0.485 0.085 0.485 0.39 0.415 0.39 0.415 0.085 0.11 0.085 0.11 0.25 0.04 0.25 0.04 0.085 0 0.085  ;
    END
  END VSS
  OBS
      LAYER metal1 ;
        POLYGON 0.235 0.495 0.55 0.495 0.55 0.15 0.825 0.15 0.825 0.22 0.62 0.22 0.62 0.725 0.705 0.725 0.705 0.795 0.55 0.795 0.55 0.565 0.235 0.565  ;
        POLYGON 0.235 0.65 0.47 0.65 0.47 0.925 1.065 0.925 1.065 0.5 1 0.5 1 0.43 1.135 0.43 1.135 0.925 1.27 0.925 1.27 0.995 0.4 0.995 0.4 0.72 0.235 0.72  ;
        POLYGON 1.335 0.56 1.6 0.56 1.6 0.15 1.67 0.15 1.67 1.25 1.6 1.25 1.6 0.63 1.335 0.63  ;
  END
END TBUF_X2

MACRO TBUF_X4
  CLASS core ;
  FOREIGN TBUF_X4 0.0 0.0 ;
  ORIGIN 0 0 ;
  SYMMETRY X Y ;
  SITE FreePDK45_38x28_10R_NP_162NW_34O ;
  SIZE 2.09 BY 1.4 ;
  PIN I
    DIRECTION INPUT ;
    ANTENNAPARTIALMETALAREA 0.01925 LAYER metal1 ;
    ANTENNAPARTIALMETALSIDEAREA 0.0741 LAYER metal1 ;
    ANTENNAGATEAREA 0.1045 ;
    PORT
      LAYER metal1 ;
        POLYGON 1.35 0.525 1.46 0.525 1.46 0.7 1.35 0.7  ;
    END
  END I
  PIN EN
    DIRECTION INPUT ;
    ANTENNAPARTIALMETALAREA 0.01575 LAYER metal1 ;
    ANTENNAPARTIALMETALSIDEAREA 0.0689 LAYER metal1 ;
    ANTENNAGATEAREA 0.0785 ;
    PORT
      LAYER metal1 ;
        POLYGON 1.75 0.525 1.84 0.525 1.84 0.7 1.75 0.7  ;
    END
  END EN
  PIN Z
    DIRECTION OUTPUT ;
    ANTENNAPARTIALMETALAREA 0.127925 LAYER metal1 ;
    ANTENNAPARTIALMETALSIDEAREA 0.4524 LAYER metal1 ;
    ANTENNADIFFAREA 0.2506 ;
    PORT
      LAYER metal1 ;
        POLYGON 0.32 1.065 0.745 1.065 0.745 1.135 0.235 1.135 0.235 0.33 0.745 0.33 0.745 0.4 0.32 0.4  ;
    END
  END Z
  PIN VDD
    DIRECTION INOUT ;
    USE power ;
    SHAPE ABUTMENT ;
    PORT
      LAYER metal1 ;
        POLYGON 0 1.315 0.075 1.315 0.075 1.205 0.145 1.205 0.145 1.315 0.45 1.315 0.45 1.205 0.52 1.205 0.52 1.315 0.83 1.315 0.83 1.205 0.9 1.205 0.9 1.315 1.21 1.315 1.21 1.205 1.28 1.205 1.28 1.315 1.63 1.315 1.745 1.315 1.745 0.86 1.815 0.86 1.815 1.315 2.005 1.315 2.09 1.315 2.09 1.485 2.005 1.485 1.63 1.485 0 1.485  ;
    END
  END VDD
  PIN VSS
    DIRECTION INOUT ;
    USE ground ;
    SHAPE ABUTMENT ;
    PORT
      LAYER metal1 ;
        POLYGON 0 -0.085 2.09 -0.085 2.09 0.085 1.81 0.085 1.81 0.195 1.74 0.195 1.74 0.085 1.435 0.085 1.435 0.195 1.365 0.195 1.365 0.085 0.9 0.085 0.9 0.195 0.83 0.195 0.83 0.085 0.52 0.085 0.52 0.195 0.45 0.195 0.45 0.085 0.145 0.085 0.145 0.335 0.075 0.335 0.075 0.085 0 0.085  ;
    END
  END VSS
  OBS
      LAYER metal1 ;
        POLYGON 0.73 0.615 0.8 0.615 0.8 0.725 1.21 0.725 1.21 0.4 1.28 0.4 1.28 0.795 0.73 0.795  ;
        POLYGON 0.59 0.465 0.66 0.465 0.66 0.895 1.56 0.895 1.56 0.4 1.63 0.4 1.63 0.965 1.435 0.965 1.435 1.14 1.365 1.14 1.365 0.965 0.59 0.965  ;
        POLYGON 0.945 0.265 1.935 0.265 1.935 0.15 2.005 0.15 2.005 0.995 1.935 0.995 1.935 0.335 1.015 0.335 1.015 0.66 0.945 0.66  ;
  END
END TBUF_X4

MACRO TBUF_X8
  CLASS core ;
  FOREIGN TBUF_X8 0.0 0.0 ;
  ORIGIN 0 0 ;
  SYMMETRY X Y ;
  SITE FreePDK45_38x28_10R_NP_162NW_34O ;
  SIZE 3.42 BY 1.4 ;
  PIN I
    DIRECTION INPUT ;
    ANTENNAPARTIALMETALAREA 0.0847 LAYER metal1 ;
    ANTENNAPARTIALMETALSIDEAREA 0.3328 LAYER metal1 ;
    ANTENNAGATEAREA 0.209 ;
    PORT
      LAYER metal1 ;
        POLYGON 1.95 0.56 2.14 0.56 2.14 0.39 2.79 0.39 2.79 0.66 2.72 0.66 2.72 0.46 2.21 0.46 2.21 0.63 1.95 0.63  ;
    END
  END I
  PIN EN
    DIRECTION INPUT ;
    ANTENNAPARTIALMETALAREA 0.08405 LAYER metal1 ;
    ANTENNAPARTIALMETALSIDEAREA 0.2821 LAYER metal1 ;
    ANTENNAGATEAREA 0.15675 ;
    PORT
      LAYER metal1 ;
        POLYGON 2.465 0.525 2.6 0.525 2.6 0.725 3.01 0.725 3.01 0.525 3.08 0.525 3.08 0.795 2.465 0.795  ;
    END
  END EN
  PIN Z
    DIRECTION OUTPUT ;
    ANTENNAPARTIALMETALAREA 0.406725 LAYER metal1 ;
    ANTENNAPARTIALMETALSIDEAREA 1.2363 LAYER metal1 ;
    ANTENNADIFFAREA 0.505675 ;
    PORT
      LAYER metal1 ;
        POLYGON 1.425 0.775 1.43 0.775 1.43 1.01 1.505 1.01 1.505 1.08 1.36 1.08 1.36 0.84 1.09 0.84 1.09 1.25 1.02 1.25 1.02 0.84 0.715 0.84 0.715 1.25 0.645 1.25 0.645 0.84 0.335 0.84 0.335 1.25 0.265 1.25 0.265 0.2 0.335 0.2 0.335 0.7 0.645 0.7 0.645 0.2 0.715 0.2 0.715 0.7 1.02 0.7 1.02 0.2 1.095 0.2 1.095 0.7 1.355 0.7 1.355 0.375 1.505 0.375 1.505 0.445 1.425 0.445  ;
    END
  END Z
  PIN VDD
    DIRECTION INOUT ;
    USE power ;
    SHAPE ABUTMENT ;
    PORT
      LAYER metal1 ;
        POLYGON 0 1.315 0.07 1.315 0.07 0.975 0.14 0.975 0.14 1.315 0.415 1.315 0.415 1.01 0.55 1.01 0.55 1.315 0.83 1.315 0.83 0.975 0.9 0.975 0.9 1.315 1.21 1.315 1.21 0.975 1.28 0.975 1.28 1.315 1.59 1.315 1.59 0.995 1.66 0.995 1.66 1.315 1.97 1.315 1.97 0.995 2.04 0.995 2.04 1.315 2.23 1.315 2.32 1.315 2.32 1.15 2.455 1.15 2.455 1.315 3.085 1.315 3.085 1.13 3.22 1.13 3.22 1.315 3.375 1.315 3.42 1.315 3.42 1.485 3.375 1.485 2.23 1.485 0 1.485  ;
    END
  END VDD
  PIN VSS
    DIRECTION INOUT ;
    USE ground ;
    SHAPE ABUTMENT ;
    PORT
      LAYER metal1 ;
        POLYGON 0 -0.085 3.42 -0.085 3.42 0.085 3.225 0.085 3.225 0.16 3.09 0.16 3.09 0.085 2.835 0.085 2.835 0.16 2.7 0.16 2.7 0.085 2.455 0.085 2.455 0.16 2.32 0.16 2.32 0.085 1.695 0.085 1.695 0.16 1.56 0.16 1.56 0.085 1.315 0.085 1.315 0.16 1.18 0.16 1.18 0.085 0.935 0.085 0.935 0.16 0.8 0.16 0.8 0.085 0.55 0.085 0.55 0.375 0.415 0.375 0.415 0.085 0.14 0.085 0.14 0.41 0.07 0.41 0.07 0.085 0 0.085  ;
    END
  END VSS
  OBS
      LAYER metal1 ;
        POLYGON 1.64 0.86 2.23 0.86 2.23 1.25 2.16 1.25 2.16 0.93 1.85 0.93 1.85 1.25 1.78 1.25 1.78 0.93 1.57 0.93 1.57 0.75 1.49 0.75 1.49 0.615 1.57 0.615 1.57 0.39 2.075 0.39 2.075 0.46 1.64 0.46  ;
        POLYGON 2.705 0.86 3.145 0.86 3.145 0.295 1.275 0.295 1.275 0.6 1.205 0.6 1.205 0.225 3.215 0.225 3.215 0.93 2.705 0.93  ;
        POLYGON 1.705 0.525 1.775 0.525 1.775 0.725 2.275 0.725 2.275 0.525 2.365 0.525 2.365 0.995 3.305 0.995 3.305 0.2 3.375 0.2 3.375 1.25 3.305 1.25 3.305 1.065 2.295 1.065 2.295 0.795 1.705 0.795  ;
  END
END TBUF_X8

MACRO XNOR2_X1
  CLASS core ;
  FOREIGN XNOR2_X1 0.0 0.0 ;
  ORIGIN 0 0 ;
  SYMMETRY X Y ;
  SITE FreePDK45_38x28_10R_NP_162NW_34O ;
  SIZE 1.14 BY 1.4 ;
  PIN A1
    DIRECTION INPUT ;
    ANTENNAPARTIALMETALAREA 0.0688 LAYER metal1 ;
    ANTENNAPARTIALMETALSIDEAREA 0.2496 LAYER metal1 ;
    ANTENNAGATEAREA 0.0785 ;
    PORT
      LAYER metal1 ;
        POLYGON 0.185 0.39 0.72 0.39 0.72 0.555 0.81 0.555 0.81 0.625 0.65 0.625 0.65 0.46 0.32 0.46 0.32 0.56 0.185 0.56  ;
    END
  END A1
  PIN A2
    DIRECTION INPUT ;
    ANTENNAPARTIALMETALAREA 0.0763 LAYER metal1 ;
    ANTENNAPARTIALMETALSIDEAREA 0.2782 LAYER metal1 ;
    ANTENNAGATEAREA 0.0785 ;
    PORT
      LAYER metal1 ;
        POLYGON 0.35 0.84 0.585 0.84 0.895 0.84 0.895 0.525 0.965 0.525 0.965 0.91 0.585 0.91 0.51 0.91 0.51 0.98 0.35 0.98  ;
    END
  END A2
  PIN ZN
    DIRECTION OUTPUT ;
    ANTENNAPARTIALMETALAREA 0.112 LAYER metal1 ;
    ANTENNAPARTIALMETALSIDEAREA 0.4342 LAYER metal1 ;
    ANTENNADIFFAREA 0.1463 ;
    PORT
      LAYER metal1 ;
        POLYGON 0.63 0.98 1.03 0.98 1.03 0.365 0.785 0.365 0.785 0.295 1.1 0.295 1.1 1.05 0.7 1.05 0.7 1.25 0.63 1.25  ;
    END
  END ZN
  PIN VDD
    DIRECTION INOUT ;
    USE power ;
    SHAPE ABUTMENT ;
    PORT
      LAYER metal1 ;
        POLYGON 0 1.315 0.05 1.315 0.05 1.115 0.12 1.115 0.12 1.315 0.43 1.315 0.43 1.115 0.5 1.115 0.5 1.315 0.585 1.315 1 1.315 1 1.115 1.07 1.115 1.07 1.315 1.105 1.315 1.14 1.315 1.14 1.485 1.105 1.485 0.585 1.485 0 1.485  ;
    END
  END VDD
  PIN VSS
    DIRECTION INOUT ;
    USE ground ;
    SHAPE ABUTMENT ;
    PORT
      LAYER metal1 ;
        POLYGON 0 -0.085 1.14 -0.085 1.14 0.085 0.53 0.085 0.53 0.25 0.395 0.25 0.395 0.085 0 0.085  ;
    END
  END VSS
  OBS
      LAYER metal1 ;
        POLYGON 0.05 0.15 0.12 0.15 0.12 0.67 0.515 0.67 0.515 0.525 0.585 0.525 0.585 0.74 0.28 0.74 0.28 1.145 0.345 1.145 0.345 1.215 0.21 1.215 0.21 0.74 0.05 0.74  ;
        POLYGON 0.595 0.16 1.105 0.16 1.105 0.23 0.595 0.23  ;
  END
END XNOR2_X1

MACRO XOR2_X1
  CLASS core ;
  FOREIGN XOR2_X1 0.0 0.0 ;
  ORIGIN 0 0 ;
  SYMMETRY X Y ;
  SITE FreePDK45_38x28_10R_NP_162NW_34O ;
  SIZE 1.14 BY 1.4 ;
  PIN A1
    DIRECTION INPUT ;
    ANTENNAPARTIALMETALAREA 0.063075 LAYER metal1 ;
    ANTENNAPARTIALMETALSIDEAREA 0.2392 LAYER metal1 ;
    ANTENNAGATEAREA 0.0785 ;
    PORT
      LAYER metal1 ;
        POLYGON 0.175 0.665 0.245 0.665 0.245 0.73 0.565 0.73 0.63 0.73 0.63 0.525 0.755 0.525 0.755 0.66 0.7 0.66 0.7 0.8 0.565 0.8 0.175 0.8  ;
    END
  END A1
  PIN A2
    DIRECTION INPUT ;
    ANTENNAPARTIALMETALAREA 0.072875 LAYER metal1 ;
    ANTENNAPARTIALMETALSIDEAREA 0.2756 LAYER metal1 ;
    ANTENNAGATEAREA 0.0785 ;
    PORT
      LAYER metal1 ;
        POLYGON 0.305 0.875 0.565 0.875 0.82 0.875 0.82 0.525 0.945 0.525 0.945 0.66 0.89 0.66 0.89 0.945 0.565 0.945 0.305 0.945  ;
    END
  END A2
  PIN Z
    DIRECTION OUTPUT ;
    ANTENNAPARTIALMETALAREA 0.11095 LAYER metal1 ;
    ANTENNAPARTIALMETALSIDEAREA 0.4303 LAYER metal1 ;
    ANTENNADIFFAREA 0.1463 ;
    PORT
      LAYER metal1 ;
        POLYGON 0.775 1.04 1.01 1.04 1.01 0.42 0.62 0.42 0.62 0.15 0.69 0.15 0.69 0.35 1.08 0.35 1.08 1.11 0.775 1.11  ;
    END
  END Z
  PIN VDD
    DIRECTION INOUT ;
    USE power ;
    SHAPE ABUTMENT ;
    PORT
      LAYER metal1 ;
        POLYGON 0 1.315 0.42 1.315 0.42 1.15 0.49 1.15 0.49 1.315 0.565 1.315 1.095 1.315 1.14 1.315 1.14 1.485 1.095 1.485 0.565 1.485 0 1.485  ;
    END
  END VDD
  PIN VSS
    DIRECTION INOUT ;
    USE ground ;
    SHAPE ABUTMENT ;
    PORT
      LAYER metal1 ;
        POLYGON 0 -0.085 1.14 -0.085 1.14 0.085 1.06 0.085 1.06 0.285 0.99 0.285 0.99 0.085 0.49 0.085 0.49 0.285 0.42 0.285 0.42 0.085 0.11 0.085 0.11 0.285 0.04 0.285 0.04 0.085 0 0.085  ;
    END
  END VSS
  OBS
      LAYER metal1 ;
        POLYGON 0.04 0.525 0.225 0.525 0.225 0.15 0.295 0.15 0.295 0.525 0.565 0.525 0.565 0.66 0.495 0.66 0.495 0.595 0.11 0.595 0.11 1.25 0.04 1.25  ;
        POLYGON 0.585 1.175 1.095 1.175 1.095 1.245 0.585 1.245  ;
  END
END XOR2_X1

